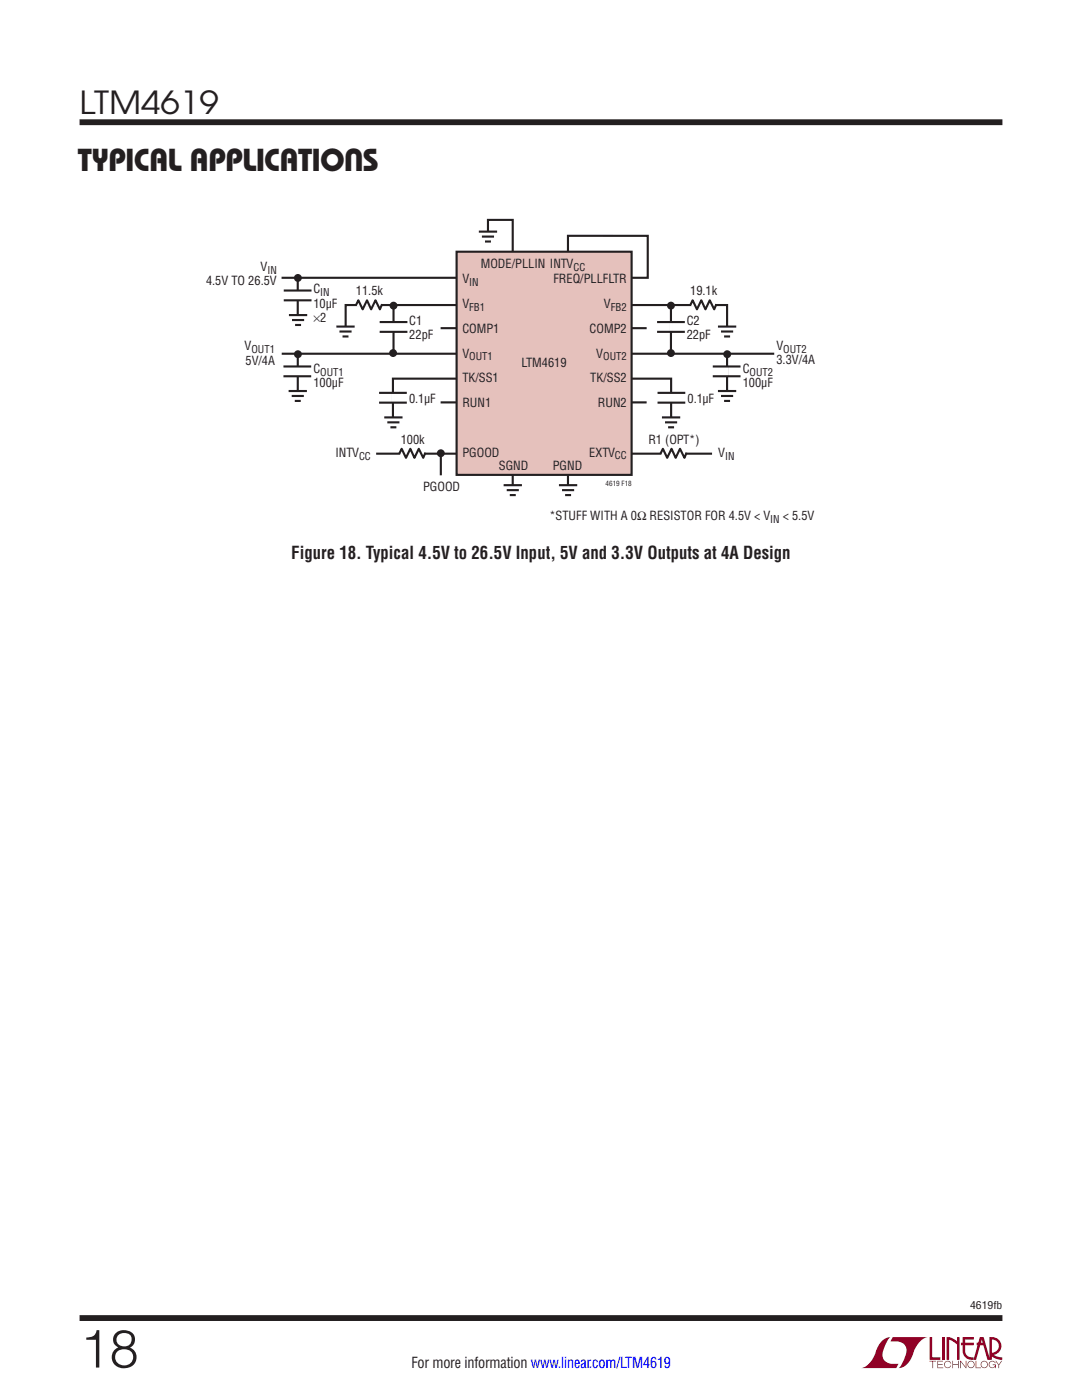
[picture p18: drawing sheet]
<svg xmlns="http://www.w3.org/2000/svg" width="216mm" height="279mm" viewBox="0 0 216 279" stroke-linecap="round" stroke-linejoin="round" font-family="sans-serif">
<defs><g id="words">
<text font-size="10.6" fill="#231f20" x="15.9" y="272.9">18</text>
<g font-size="6.3" fill="#231f20">
<text x="15.9" y="22.8">LTM4619</text>
<text x="15.6" y="34.1">Typical Applications</text>
</g>
<text font-size="3.5" fill="#231f20" x="58.1" y="111.5">Figure 18. Typical 4.5V to 26.5V Input, 5V and 3.3V Outputs at 4A Design</text>
<text font-size="3" fill="#231f20" x="82.1" y="273.1">For more information www.linear.com/LTM4619</text>
<g font-size="2.5" fill="#231f20">
<text x="95.9" y="53.5">MODE/PLLIN INTV</text>
<text x="41.1" y="56.9">4.5V TO 26.5V</text>
<text x="52" y="54.1">V</text>
<text x="62.5" y="58.6">C</text>
<text x="71" y="59">11.5k</text>
<text x="92.3" y="56.6">V</text>
<text x="110.4" y="56.6">FREQ/PLLFLTR</text>
<text x="137.7" y="59">19.1k</text>
<text x="62.5" y="61.4">10µF</text>
<text x="62.5" y="64.2">×2</text>
<text x="81.7" y="64.9">C1</text>
<text x="92.3" y="61.5">V</text>
<text x="120.5" y="61.5">V</text>
<text x="137" y="64.9">C2</text>
<text x="48.8" y="69.9">V</text>
<text x="81.7" y="67.7">22pF</text>
<text x="92.3" y="66.5">COMP1</text>
<text x="92.3" y="71.4">V</text>
<text x="117.7" y="66.5">COMP2</text>
<text x="119" y="71.4">V</text>
<text x="137" y="67.7">22pF</text>
<text x="154.9" y="69.9">V</text>
<text x="49" y="72.7">5V/4A</text>
<text x="62.5" y="74.4">C</text>
<text x="62.5" y="77.2">100µF</text>
<text x="92.3" y="76.3">TK/SS1</text>
<text x="104.1" y="73.3">LTM4619</text>
<text x="117.8" y="76.3">TK/SS2</text>
<text x="148.2" y="74.4">C</text>
<text x="148.2" y="77.2">100µF</text>
<text x="154.9" y="72.7">3.3V/4A</text>
<text x="81.6" y="80.4">0.1µF</text>
<text x="92.3" y="81.3">RUN1</text>
<text x="119.3" y="81.3">RUN2</text>
<text x="137.2" y="80.4">0.1µF</text>
<text x="80" y="88.6">100k</text>
<text x="129.4" y="88.6">R1 (OPT*)</text>
<text x="66.9" y="91.2">INTV</text>
<text x="92.3" y="91.1">PGOOD</text>
<text x="99.5" y="93.8">SGND</text>
<text x="110.3" y="93.8">PGND</text>
<text x="117.6" y="91.1">EXTV</text>
<text x="143.3" y="91.2">V</text>
<text x="84.4" y="97.9">PGOOD</text>
<text x="109.6" y="103.8">*STUFF WITH A 0Ω RESISTOR FOR 4.5V &lt; V</text>
<text x="156.2" y="103.8">&lt; 5.5V</text>
</g>
<g font-size="2.1" fill="#231f20">
<text x="53.4" y="54.6">IN</text>
<text x="63.9" y="59.1">IN</text>
<text x="93.6" y="57.1">IN</text>
<text x="114.4" y="54">CC</text>
<text x="93.6" y="62">FB1</text>
<text x="121.9" y="62">FB2</text>
<text x="50.2" y="70.5">OUT1</text>
<text x="93.6" y="71.9">OUT1</text>
<text x="120.4" y="71.9">OUT2</text>
<text x="156.3" y="70.4">OUT2</text>
<text x="63.9" y="74.9">OUT1</text>
<text x="149.6" y="74.9">OUT2</text>
<text x="71.6" y="91.7">CC</text>
<text x="122.7" y="91.7">CC</text>
<text x="144.7" y="91.7">IN</text>
<text x="153.7" y="104.3">IN</text>
<text x="193.6" y="261.2">4619fb</text>
</g>
<text font-size="1.4" fill="#231f20" x="120.9" y="96.9">4619 F18</text>
</g></defs>
<g fill="#900126">
<path d="M185.5 266.8h.5v4.1h1.6v.5h-2.1z"/>
<path d="M176.2 267.4l1-.5h.5h-.1a6.2 6.2 0 0 0-1.4 4 2.58 2.58 0 0 0 3.1 1.3l-.5 .8h-6.9a4.9 4.9 0 0 0 3-3.8l.4-.7z"/>
<path d="M178.1 266.9h7a4.9 4.9 0 0 0-3.1 3.7 3.2 3.2 0 0 1-2.7 2.4h.1a6.2 6.2 0 0 0 1.4-4.1 2.58 2.58 0 0 0-3.1-1.2z"/>
<path d="M188 266.8h.5v4.6h-.5z"/>
<path d="M188.9 266.8l1 .2 1.1 .7v-.9h.5v4.6h-.5v-3.1l-1.6-.9v4h-.5z"/>
<path d="M185.5 271.6h1.3v.1h-.6v1.3h-.1v-1.3h-.6z"/>
<path d="M187 271.6h1.2v.1h-1v.5h.9v.2h-.9v.5h1v.1h-1.2z"/>
<path d="M190 271.6h.2v.6h1v-.6h.1v1.4h-.1v-.6h-1v.6h-.2z"/>
<path d="M191.6 271.6h.1l1 1.2v-1.2h.1v1.4l-1.1-1.2v1.2h-.1z"/>
<path d="M194.7 271.6h.1v1.3h.9v.1h-1z"/>
<path d="M198.6 271.6h.2l.5 .7 .5-.7h.2l-.6 .8v.6h-.2v-.6z"/>
<path d="M192.1 266.8h2.2v.5h-1.7v.7h1.7v.5h-1.7v1.1a1.32 1.32 0 0 0 1.7 1.3v.5l1.2-4.6h.8l1.1 4.1v-4.1a1.84 1.84 0 0 1 2.4 1.4 1.84 1.84 0 0 1-1.5 2.2l.8 .4 .9 .1v.5l-1.2-.2-1-.6v-.6a1.34 1.34 0 0 0 1.5-1.2 1.34 1.34 0 0 0-1.4-1.5v4.1h-.9l-.8-2.9h-1.3v-.5h1.2l-.2-.7-1.1 4.1a2.06 2.06 0 0 1-2.7-1.3v-1.6h-.4v-.5h.4z"/>
<path d="M193.2 271.8a.72 .72 0 0 1 1.2 .1 .72 .72 0 0 1-.4 1.1 .72 .72 0 0 1-1-.7h.2a.59 .59 0 0 0 .8 .5 .59 .59 0 0 0 .2-.9 .59 .59 0 0 0-1 .2v.2h-.2z"/>
<path d="M195.9 271.8a.72 .72 0 0 1 1.1 .1 .72 .72 0 0 1-.4 1.1 .72 .72 0 0 1-.9-.7h.1a.59 .59 0 0 0 .8 .5 .59 .59 0 0 0 .2-.9 .59 .59 0 0 0-.9 .2l-.1 .2h-.1z"/>
<path d="M197.5 271.8a.72 .72 0 0 1 1.2 .2h-.2a.59 .59 0 0 0-.9-.1 .59 .59 0 0 0 .1 .9 .59 .59 0 0 0 .9-.4h-.5v-.1h.6v.7h-.1v-.3a.73 .73 0 0 1-1.1 .2 .73 .73 0 0 1 0-1.1z"/>
<path d="M188.6 271.8a.71 .71 0 0 1 1.2 .3h-.1a.59 .59 0 0 0-.9-.3 .59 .59 0 0 0-.1 1 .59 .59 0 0 0 1-.3h.1a.73 .73 0 0 1-1.1 .4 .73 .73 0 0 1-.1-1.1z"/>
</g>
<path d="M15.9 24.4h184.1M15.9 263h184.1" fill="none" stroke="#231f20" stroke-width="1.2" stroke-linecap="butt"/>
<path d="M56.2 55.4h73.1v-8.3h-16v51M97.4 47.2v-3.3h4.9v54.4M56.2 70.6h98.3M87.9 65.5h41.1M145.1 66.6v-5.7h-76.1v5.8M75.1 90.5h67M87.9 80.3h41.1M133.9 84.3v-8.7h-55.5v8.9" fill="none" stroke="#231f20" stroke-width=".42"/>
<path d="M91.1 50.2h34.9v44.6h-34.9z" fill="#e5c1bc"/>
<path d="M91.1 50.2h34.9v44.6h-34.9zM76.2 60.7l-.4 1-.9-1.8-.8 1.8-.9-1.8-.8 1.8-.9-1.8-.5 1M142.2 73.1h5.6M142.2 75.1h5.6M142.9 60.7l-.4 1-.9-1.8-.8 1.8-.9-1.8-.8 1.8-.9-1.8-.5 1M143.3 78h3.6M143.9 79h2.4M145.1 70.5v8.8M84.9 90.3l-.5 1.1-.8-1.8-.9 1.8-.8-1.8-.9 1.8-.9-1.8-.4 .9M137 90.3l-.4 1.1-.9-1.8-.9 1.8-.8-1.8-.9 1.8-.8-1.8-.5 .9M144.5 80h1.2" fill="none" stroke="#231f20" stroke-width=".42"/>
<path d="M71.2 60.8h4.8M137.9 60.8h4.8M145 73.2v1.9M79.9 90.5h4.8M132 90.5h4.8" fill="none" stroke="#fff" stroke-width=".71" stroke-linecap="butt"/>
<path d="M145.1 78.1v2.2" fill="none" stroke="#fff" stroke-width=".97" stroke-linecap="butt"/>
<circle cx="145.1" cy="70.7" r=".79" fill="#231f20"/>
<path d="M56.6 73.1h5.5M56.6 75.1h5.5M57.6 78h3.6M58.2 79h2.4M59.4 70.5v8.8M58.8 80h1.2" fill="none" stroke="#231f20" stroke-width=".42"/>
<path d="M59.3 73.2v1.9" fill="none" stroke="#fff" stroke-width=".71" stroke-linecap="butt"/>
<path d="M59.4 78.1v2.2" fill="none" stroke="#fff" stroke-width=".97" stroke-linecap="butt"/>
<circle cx="59.4" cy="70.7" r=".79" fill="#231f20"/>
<path d="M102.3 96.8v2.3M113.4 96.8v2.3" fill="none" stroke="#fff" stroke-width=".97" stroke-linecap="butt"/>
<path d="M59.4 55.6v8.7M100.5 96.8h3.6M101.1 97.8h2.4M101.7 98.8h1.2M111.5 96.8h3.7M112.1 97.8h2.5M112.8 98.8h1.2" fill="none" stroke="#231f20" stroke-width=".42"/>
<circle cx="59.4" cy="55.5" r=".79" fill="#231f20"/>
<path d="M59.4 58v1.9M78.4 78.4v2M134 78.4v2" fill="none" stroke="#fff" stroke-width=".71" stroke-linecap="butt"/>
<g fill="none" stroke="#231f20" stroke-width=".42">
<path d="M56.6 58h5.6M56.6 59.9h5.6M57.7 62.9h3.6M58.3 63.9h2.4M58.9 64.9h1.2M75.6 78.4h5.6M78.5 61v9.6M131.2 78.4h5.5M75.6 80.4h5.6M76.7 83.3h3.6M77.3 84.3h2.4M77.9 85.3h1.2"/>
<path d="M131.2 80.4h5.5M132.1 83.3h3.6M132.7 84.3h2.4M133.3 85.3h1.2"/>
</g>
<path d="M59.5 62.9v2.2M78.5 83.3v2.2M133.9 83.3v2.2" fill="none" stroke="#fff" stroke-width=".97" stroke-linecap="butt"/>
<circle cx="78.5" cy="61" r=".79" fill="#231f20"/>
<path d="M88 90.5v4.4" fill="none" stroke="#231f20" stroke-width=".42"/>
<g fill="#231f20">
<circle cx="88" cy="90.5" r=".79"/>
<circle cx="78.4" cy="70.5" r=".79"/>
</g>
<path d="M69 65.2v2.2M145.1 65.2v2.2" fill="none" stroke="#fff" stroke-width=".97" stroke-linecap="butt"/>
<path d="M67.1 65.2h3.7M67.7 66.2h2.5M68.3 67.2h1.2M75.8 64.3h5.5M75.8 66.2h5.5M133.9 61v9.6M143.3 65.2h3.6M143.9 66.2h2.4M144.5 67.2h1.2" fill="none" stroke="#231f20" stroke-width=".42"/>
<path d="M78.5 64.3v1.9" fill="none" stroke="#fff" stroke-width=".71" stroke-linecap="butt"/>
<g fill="#231f20">
<circle cx="133.9" cy="61" r=".79"/>
<circle cx="133.9" cy="70.5" r=".79"/>
</g>
<path d="M133.9 64.3v1.9" fill="none" stroke="#fff" stroke-width=".71" stroke-linecap="butt"/>
<path d="M95.5 46.2h3.7M96.2 47.2h2.4M96.8 48.2h1.2M131.1 64.3h5.6M131.1 66.2h5.6" fill="none" stroke="#231f20" stroke-width=".42"/>
<path d="M97.4 46.2v2.3" fill="none" stroke="#fff" stroke-width=".97" stroke-linecap="butt"/>
<use href="#words"/>
</svg>
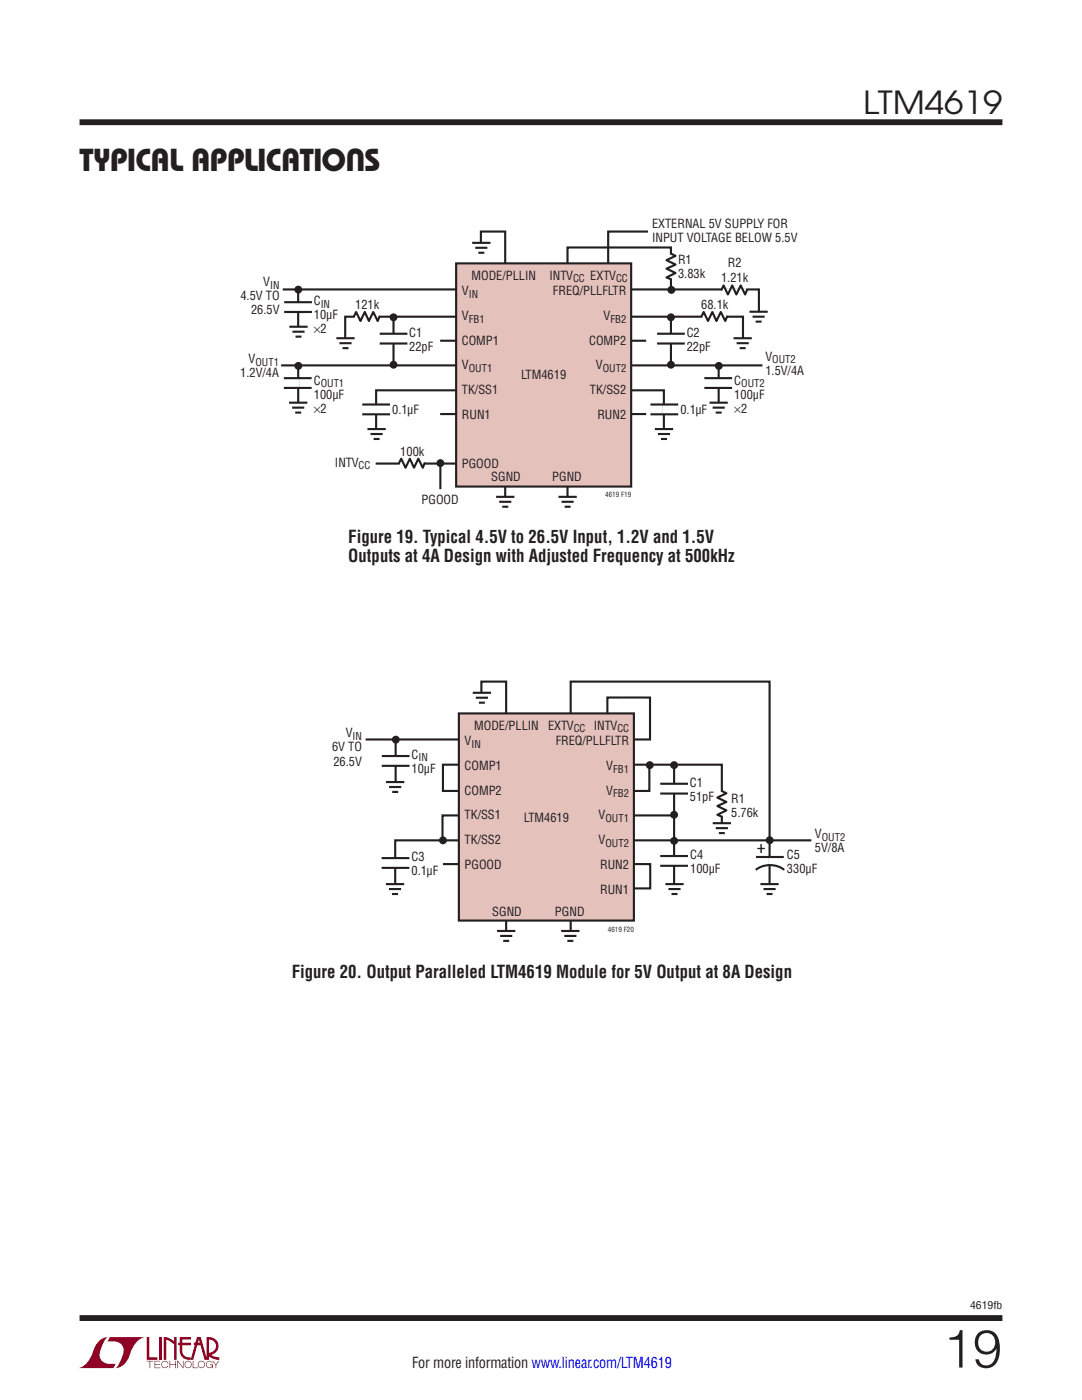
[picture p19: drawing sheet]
<svg xmlns="http://www.w3.org/2000/svg" width="216mm" height="279mm" viewBox="0 0 216 279" stroke-linecap="round" stroke-linejoin="round" font-family="sans-serif">
<defs><g id="words">
<text font-size="10.6" fill="#231f20" x="188.2" y="272.9">19</text>
<g font-size="6.3" fill="#231f20">
<text x="172.2" y="22.8">LTM4619</text>
<text x="15.9" y="34.1">TY</text>
<text x="18.6" y="34.1">P</text>
<text x="18.6" y="34.1">I</text>
<text x="18.6" y="34.1">C</text>
<text x="18.6" y="34.1">A</text>
<text x="18.6" y="34.1">L</text>
<text x="38.1" y="34.1">applications</text>
</g>
<g font-size="3.5" fill="#231f20">
<text x="69.5" y="108.4">Figure 19. Typical 4.5V to 26.5V Input, 1.2V and 1.5V</text>
<text x="69.5" y="112.2">Outputs at 4A Design with Adjusted Frequency at 500kHz</text>
<text x="58.2" y="195.2">Figure 20. Output Paralleled LTM4619 Module for 5V Output at 8A Design</text>
</g>
<text font-size="3.5" x="151" y="170.2">+</text>
<text font-size="3" fill="#231f20" x="82.2" y="273.1">For more information www.linear.com/LTM4619</text>
<g font-size="2.5" fill="#231f20">
<text x="130.1" y="45.5">EXTERNAL 5V SUPPLY FOR</text>
<text x="130.1" y="48.3">INPUT VOLTAGE BELOW 5.5V</text>
<text x="135.3" y="52.7">R1</text>
<text x="145.2" y="53.4">R2</text>
<text x="48" y="59.9">4.5V TO</text>
<text x="52.5" y="57.1">V</text>
<text x="92.2" y="58.9">V</text>
<text x="94.1" y="55.8">MODE/PLLIN</text>
<text x="109.6" y="55.8">INTV</text>
<text x="110.3" y="58.9">FREQ/PLLFLTR</text>
<text x="117.8" y="55.8">EXTV</text>
<text x="135.3" y="55.5">3.83k</text>
<text x="143.9" y="56.2">1.21k</text>
<text x="50.1" y="62.8">26.5V</text>
<text x="62.6" y="60.9">C</text>
<text x="62.6" y="63.7">10µF</text>
<text x="70.9" y="61.7">121k</text>
<text x="92.2" y="63.8">V</text>
<text x="120.4" y="63.8">V</text>
<text x="139.9" y="61.7">68.1k</text>
<text x="62.6" y="66.5">×2</text>
<text x="81.7" y="67.2">C1</text>
<text x="81.7" y="70">22pF</text>
<text x="92.2" y="68.8">COMP1</text>
<text x="117.6" y="68.8">COMP2</text>
<text x="137" y="67.2">C2</text>
<text x="137" y="70">22pF</text>
<text x="152.7" y="72">V</text>
<text x="47.9" y="75.3">1.2V/4A</text>
<text x="49.6" y="72.4">V</text>
<text x="62.6" y="76.7">C</text>
<text x="92.2" y="73.7">V</text>
<text x="104" y="75.6">LTM4619</text>
<text x="118.9" y="73.7">V</text>
<text x="146.5" y="76.7">C</text>
<text x="152.7" y="74.8">1.5V/4A</text>
<text x="62.6" y="79.6">100µF</text>
<text x="62.6" y="82.4">×2</text>
<text x="78.3" y="82.7">0.1µF</text>
<text x="92.2" y="78.7">TK/SS1</text>
<text x="92.2" y="83.6">RUN1</text>
<text x="117.7" y="78.7">TK/SS2</text>
<text x="119.2" y="83.6">RUN2</text>
<text x="135.8" y="82.7">0.1µF</text>
<text x="146.5" y="79.6">100µF</text>
<text x="146.5" y="82.4">×2</text>
<text x="66.8" y="93.2">INTV</text>
<text x="79.9" y="90.9">100k</text>
<text x="92.2" y="93.5">PGOOD</text>
<text x="84.1" y="100.6">PGOOD</text>
<text x="98" y="96.1">SGND</text>
<text x="110.2" y="96.1">PGND</text>
<text x="66.3" y="150">6V TO</text>
<text x="69" y="147.1">V</text>
<text x="92.7" y="148.7">V</text>
<text x="94.6" y="145.6">MODE/PLLIN</text>
<text x="109.4" y="145.6">EXTV</text>
<text x="110.9" y="148.7">FREQ/PLLFLTR</text>
<text x="118.5" y="145.6">INTV</text>
<text x="66.5" y="152.8">26.5V</text>
<text x="82.1" y="151.4">C</text>
<text x="82.1" y="154.2">10µF</text>
<text x="92.7" y="153.7">COMP1</text>
<text x="121" y="153.7">V</text>
<text x="92.7" y="158.6">COMP2</text>
<text x="121" y="158.6">V</text>
<text x="137.7" y="157">C1</text>
<text x="137.7" y="159.8">51pF</text>
<text x="145.9" y="160.3">R1</text>
<text x="92.7" y="163.5">TK/SS1</text>
<text x="104.5" y="164.1">LTM4619</text>
<text x="119.4" y="163.5">V</text>
<text x="145.9" y="163.1">5.76k</text>
<text x="162.6" y="167.3">V</text>
<text x="82.1" y="171.8">C3</text>
<text x="92.7" y="168.5">TK/SS2</text>
<text x="92.7" y="173.4">PGOOD</text>
<text x="119.4" y="168.5">V</text>
<text x="119.8" y="173.4">RUN2</text>
<text x="137.7" y="171.5">C4</text>
<text x="157" y="171.5">C5</text>
<text x="162.6" y="170.1">5V/8A</text>
<text x="82.1" y="174.6">0.1µF</text>
<text x="119.8" y="178.4">RUN1</text>
<text x="137.7" y="174.3">100µF</text>
<text x="157" y="174.3">330µF</text>
<text x="98.2" y="182.7">SGND</text>
<text x="110.7" y="182.7">PGND</text>
</g>
<g font-size="2.1" fill="#231f20">
<text x="53.9" y="57.6">IN</text>
<text x="93.5" y="59.4">IN</text>
<text x="114.4" y="56.3">CC</text>
<text x="122.9" y="56.4">CC</text>
<text x="64" y="61.4">IN</text>
<text x="93.5" y="64.4">FB1</text>
<text x="121.8" y="64.4">FB2</text>
<text x="51" y="73">OUT1</text>
<text x="64" y="77.3">OUT1</text>
<text x="93.5" y="74.3">OUT1</text>
<text x="120.3" y="74.3">OUT2</text>
<text x="147.9" y="77.3">OUT2</text>
<text x="154.1" y="72.5">OUT2</text>
<text x="71.6" y="93.7">CC</text>
<text x="70.3" y="147.7">IN</text>
<text x="94.1" y="149.2">IN</text>
<text x="114.5" y="146.2">CC</text>
<text x="123.2" y="146.2">CC</text>
<text x="83.5" y="151.9">IN</text>
<text x="122.3" y="154.2">FB1</text>
<text x="122.3" y="159.1">FB2</text>
<text x="120.8" y="164.1">OUT1</text>
<text x="164" y="167.8">OUT2</text>
<text x="120.8" y="169">OUT2</text>
<text x="193.6" y="261.2">4619fb</text>
</g>
<g font-size="1.4" fill="#231f20">
<text x="120.8" y="99.3">4619 F19</text>
<text x="121.3" y="185.9">4619 F20</text>
</g>
</g></defs>
<g fill="#900126">
<path d="M29.3 266.8h.5v4.1h1.6v.5h-2.1z"/>
<path d="M20 267.4l1-.5h.5h-.1a6.2 6.2 0 0 0-1.5 4 2.58 2.58 0 0 0 3.2 1.3l-.5 .8h-7a4.9 4.9 0 0 0 3.1-3.8l.4-.7z"/>
<path d="M21.9 266.9h7a4.9 4.9 0 0 0-3.1 3.7 3.2 3.2 0 0 1-2.7 2.4h.1a6.2 6.2 0 0 0 1.4-4.1 2.58 2.58 0 0 0-3.1-1.2z"/>
<path d="M31.8 266.8h.5v4.6h-.5z"/>
<path d="M32.7 266.8l1 .2 1 .7v-.9h.5v4.6h-.5v-3.1l-1.5-.9v4h-.5z"/>
<path d="M29.3 271.6h1.3v.1h-.6v1.3h-.2v-1.3h-.5z"/>
<path d="M30.8 271.6h1.2v.1h-1v.5h.9v.2h-.9v.5h1v.1h-1.2z"/>
<path d="M33.8 271.6h.2v.6h1v-.6h.1v1.4h-.1v-.6h-1v.6h-.2z"/>
<path d="M35.4 271.6h.1l1 1.2v-1.2h.1v1.4l-1.1-1.2v1.2h-.1z"/>
<path d="M38.5 271.6h.1v1.3h.9v.1h-1z"/>
<path d="M42.4 271.6h.1l.6 .7 .5-.7h.2l-.7 .8v.6h-.1v-.6z"/>
<path d="M35.9 266.8h2.2v.5h-1.7v.7h1.7v.5h-1.7v1.1a1.32 1.32 0 0 0 1.6 1.3v.5l1.3-4.6h.8l1.1 4.1v-4.1a1.84 1.84 0 0 1 2.3 1.4 1.84 1.84 0 0 1-1.4 2.2l.7 .4 1 .1v.5l-1.2-.2-1.1-.6v-.6a1.34 1.34 0 0 0 1.6-1.2 1.34 1.34 0 0 0-1.4-1.5v4.1h-.9l-.8-2.9h-1.3v-.5h1.2l-.2-.7-1.1 4.1a2.06 2.06 0 0 1-2.7-1.3v-1.6h-.4v-.5h.4z"/>
<path d="M37 271.8a.72 .72 0 0 1 1.2 .1 .72 .72 0 0 1-.4 1.1 .72 .72 0 0 1-1-.7h.2a.59 .59 0 0 0 .8 .5 .59 .59 0 0 0 .2-.9 .59 .59 0 0 0-1 .2v.2h-.2z"/>
<path d="M39.7 271.8a.72 .72 0 0 1 1.1 .1 .72 .72 0 0 1-.4 1.1 .72 .72 0 0 1-.9-.7h.1a.59 .59 0 0 0 .8 .5 .59 .59 0 0 0 .2-.9 .59 .59 0 0 0-1 .2v.2h-.1z"/>
<path d="M41.3 271.8a.72 .72 0 0 1 1.2 .2h-.2a.59 .59 0 0 0-.9-.1 .59 .59 0 0 0 .1 .9 .59 .59 0 0 0 .9-.4h-.5v-.1h.6v.7h-.1v-.3a.73 .73 0 0 1-1.1 .2 .73 .73 0 0 1 0-1.1z"/>
<path d="M32.4 271.8a.71 .71 0 0 1 1.2 .3h-.1a.59 .59 0 0 0-.9-.3 .59 .59 0 0 0-.1 1 .59 .59 0 0 0 .9-.3h.2a.73 .73 0 0 1-1.1 .4 .73 .73 0 0 1-.1-1.1z"/>
</g>
<path d="M15.9 24.4h184.1M15.9 263h184.1" fill="none" stroke="#231f20" stroke-width="1.2" stroke-linecap="butt"/>
<path d="M56.4 57.8h95v4.9M96 49.5v-3.3h4.8v54.4M129.3 46.2h-7.9v10.2M133.9 57.8v-8.4h-20.7v51.1M56.1 72.9h96M87.8 68h41.1M148.3 68.9v-5.7h-79.4v5.9M75 92.5h19.2M87.8 82.6h41.1M132.5 86.7v-8.8h-57.4v9" fill="none" stroke="#231f20" stroke-width=".42"/>
<path d="M91 52.6h34.9v44.5h-34.9z" fill="#e5c1bc" stroke="#231f20" stroke-width=".42"/>
<path d="M144.1 57.9h4.8M70.8 63.2h4.8M140.1 63.2h4.8M143.3 75.5v1.9M79.8 92.4h4.8" fill="none" stroke="#fff" stroke-width=".71" stroke-linecap="butt"/>
<path d="M149.1 57.7l-.4 1.1-.9-1.8-.9 1.8-.8-1.8-.9 1.8-.8-1.8-.5 .9M75.8 63l-.4 1.1-.9-1.8-.9 1.8-.8-1.8-.9 1.8-.8-1.8-.5 .9M140.5 75.5h5.6M140.5 77.4h5.6M143.4 72.8v8.8M145.1 63l-.4 1.1-.9-1.8-.8 1.8-.9-1.8-.8 1.8-.9-1.8-.5 .9M84.8 92.3l-.4 1-.9-1.8-.9 1.8-.8-1.8-.9 1.8-.8-1.8-.5 1M141.6 80.4h3.6M142.2 81.4h2.4M142.8 82.3h1.2" fill="none" stroke="#231f20" stroke-width=".42"/>
<path d="M143.4 80.4v2.2" fill="none" stroke="#fff" stroke-width=".97" stroke-linecap="butt"/>
<circle cx="143.4" cy="73" r=".79" fill="#231f20"/>
<path d="M56.6 75.5h5.6M56.6 77.4h5.6M59.5 72.8v8.8M57.7 80.4h3.6M58.3 81.4h2.4M58.9 82.3h1.2" fill="none" stroke="#231f20" stroke-width=".42"/>
<path d="M59.4 75.5v1.9" fill="none" stroke="#fff" stroke-width=".71" stroke-linecap="butt"/>
<path d="M59.5 80.4v2.2" fill="none" stroke="#fff" stroke-width=".97" stroke-linecap="butt"/>
<circle cx="59.5" cy="73" r=".79" fill="#231f20"/>
<path d="M100.8 99.2v2.2M113.3 99.2v2.2" fill="none" stroke="#fff" stroke-width=".97" stroke-linecap="butt"/>
<path d="M59.5 58v8.7M99 99.2h3.6M111.4 99.2h3.7M99.6 100.1h2.4M100.2 101.1h1.2M112.1 100.1h2.4M112.7 101.1h1.2" fill="none" stroke="#231f20" stroke-width=".42"/>
<circle cx="59.5" cy="57.8" r=".79" fill="#231f20"/>
<path d="M59.5 60.3v2M75.1 80.8v1.9M132.6 80.8v1.9" fill="none" stroke="#fff" stroke-width=".71" stroke-linecap="butt"/>
<g fill="none" stroke="#231f20" stroke-width=".42">
<path d="M56.7 60.3h5.5M56.7 62.3h5.5M57.7 65.2h3.7M58.4 66.2h2.4M59 67.2h1.2M78.5 63.3v9.6M72.3 80.7h5.5M72.3 82.7h5.5M73.3 85.6h3.7M73.9 86.6h2.5M74.5 87.6h1.2M129.8 80.7h5.5"/>
<path d="M129.8 82.7h5.5M130.7 85.6h3.6M131.3 86.6h2.4M131.9 87.6h1.2"/>
</g>
<path d="M59.6 65.2v2.2M75.1 85.6v2.3M132.5 85.6v2.3" fill="none" stroke="#fff" stroke-width=".97" stroke-linecap="butt"/>
<circle cx="78.5" cy="63.3" r=".79" fill="#231f20"/>
<path d="M87.9 92.4v5.2" fill="none" stroke="#231f20" stroke-width=".42"/>
<g fill="#231f20">
<circle cx="87.9" cy="92.4" r=".79"/>
<circle cx="78.5" cy="72.8" r=".79"/>
</g>
<path d="M68.9 67.5v2.2M148.2 67.5v2.2" fill="none" stroke="#fff" stroke-width=".97" stroke-linecap="butt"/>
<path d="M67.1 67.5h3.7M67.7 68.5h2.5M68.3 69.5h1.2M75.8 66.6h5.5M75.8 68.6h5.5M133.9 63.3v9.6M146.4 67.5h3.6M147 68.5h2.4M147.6 69.5h1.2" fill="none" stroke="#231f20" stroke-width=".42"/>
<path d="M78.5 66.6v1.9" fill="none" stroke="#fff" stroke-width=".71" stroke-linecap="butt"/>
<g fill="#231f20">
<circle cx="133.9" cy="63.3" r=".79"/>
<circle cx="134" cy="57.9" r=".79"/>
<circle cx="133.9" cy="72.8" r=".79"/>
</g>
<path d="M133.9 50.8v4.8M133.9 66.6v1.9" fill="none" stroke="#fff" stroke-width=".71" stroke-linecap="butt"/>
<g fill="none" stroke="#231f20" stroke-width=".42">
<path d="M94.2 48.5h3.7M94.8 49.5h2.5M95.4 50.4h1.2M133.8 50.6l1 .5-1.8 .8 1.8 .9-1.8 .8 1.8 .9-1.8 .9 1 .4M131.1 66.6h5.5M131.1 68.6h5.5M149.5 62.2h3.7M150.2 63.2h2.4M150.8 64.2h1.2M96.1 140v-4h4.9v51.1M73 147.6h56.7v-8.4h-8.5v10.7M129.6 152.6v5.3h-41.2v-5.3h55.6v13"/>
<path d="M88.4 172.5h41.3v4.8h-9.1M134.2 162.7h-45.9v5M153.6 177v-41h-39.7v50.5M161.9 167.7h-83v9.8"/>
</g>
<path d="M96.1 48.5v2.2M151.4 62.2v2.2" fill="none" stroke="#fff" stroke-width=".97" stroke-linecap="butt"/>
<path d="M91.6 142.4h34.9v41.3h-34.9z" fill="#e5c1bc" stroke="#231f20" stroke-width=".42"/>
<path d="M144 158v4.8" fill="none" stroke="#fff" stroke-width=".71" stroke-linecap="butt"/>
<path d="M144 157.8l.9 .5-1.8 .9 1.8 .8-1.8 .9 1.8 .8-1.8 .9 1.1 .4M77 176.4h3.6M77.6 177.4h2.4M78.2 178.4h1.2M151.7 176.4h3.7M152.3 177.4h2.5M153 178.4h1.2" fill="none" stroke="#231f20" stroke-width=".42"/>
<path d="M78.8 176.5v2.2M153.6 176.5v2.2" fill="none" stroke="#fff" stroke-width=".97" stroke-linecap="butt"/>
<circle cx="153.6" cy="167.7" r=".79" fill="#231f20"/>
<path d="M101 185.8v2.2M113.8 185.8v2.2" fill="none" stroke="#fff" stroke-width=".97" stroke-linecap="butt"/>
<path d="M78.9 147.8v8.7M99.2 185.8h3.6M99.8 186.8h2.4M100.4 187.8h1.2M112 185.8h3.6M112.6 186.8h2.4M113.2 187.8h1.2" fill="none" stroke="#231f20" stroke-width=".42"/>
<circle cx="79" cy="147.6" r=".79" fill="#231f20"/>
<path d="M79 150.9v1.9M78.9 171.3v1.9" fill="none" stroke="#fff" stroke-width=".71" stroke-linecap="butt"/>
<path d="M76.2 150.9h5.5M76.2 152.8h5.5M77 156.1h3.7M77.6 157.1h2.5M78.3 158.1h1.1M134.5 152.7v25M76.1 171.3h5.6M76.1 173.2h5.6M142.2 164.3h3.7M142.8 165.3h2.4M143.4 166.3h1.2" fill="none" stroke="#231f20" stroke-width=".42"/>
<path d="M78.9 156.1v2.2M144 164.3v2.2" fill="none" stroke="#fff" stroke-width=".97" stroke-linecap="butt"/>
<g fill="#231f20">
<circle cx="134.5" cy="152.7" r=".79"/>
<circle cx="129.7" cy="152.7" r=".79"/>
<circle cx="134.5" cy="162.6" r=".79"/>
<circle cx="134.5" cy="167.8" r=".79"/>
</g>
<path d="M134.5 156.4v2M134.5 170.9v1.9M153.6 171.1v1.6" fill="none" stroke="#fff" stroke-width=".71" stroke-linecap="butt"/>
<path d="M94.3 138.3h3.7M94.9 139.2h2.5M95.6 140.2h1.2M131.7 156.4h5.6M131.7 158.4h5.6M131.7 170.8h5.6M131.7 172.8h5.6M132.8 176.4h3.6M133.4 177.4h2.4M134 178.4h1.2M150.8 173.6a4.7 4.7 0 0 1 5.7 0M150.9 171h5.5" fill="none" stroke="#231f20" stroke-width=".42"/>
<path d="M96.2 138.3v2.2M134.6 176.5v2.2" fill="none" stroke="#fff" stroke-width=".97" stroke-linecap="butt"/>
<circle cx="88.4" cy="167.7" r=".79" fill="#231f20"/>
<use href="#words"/>
</svg>
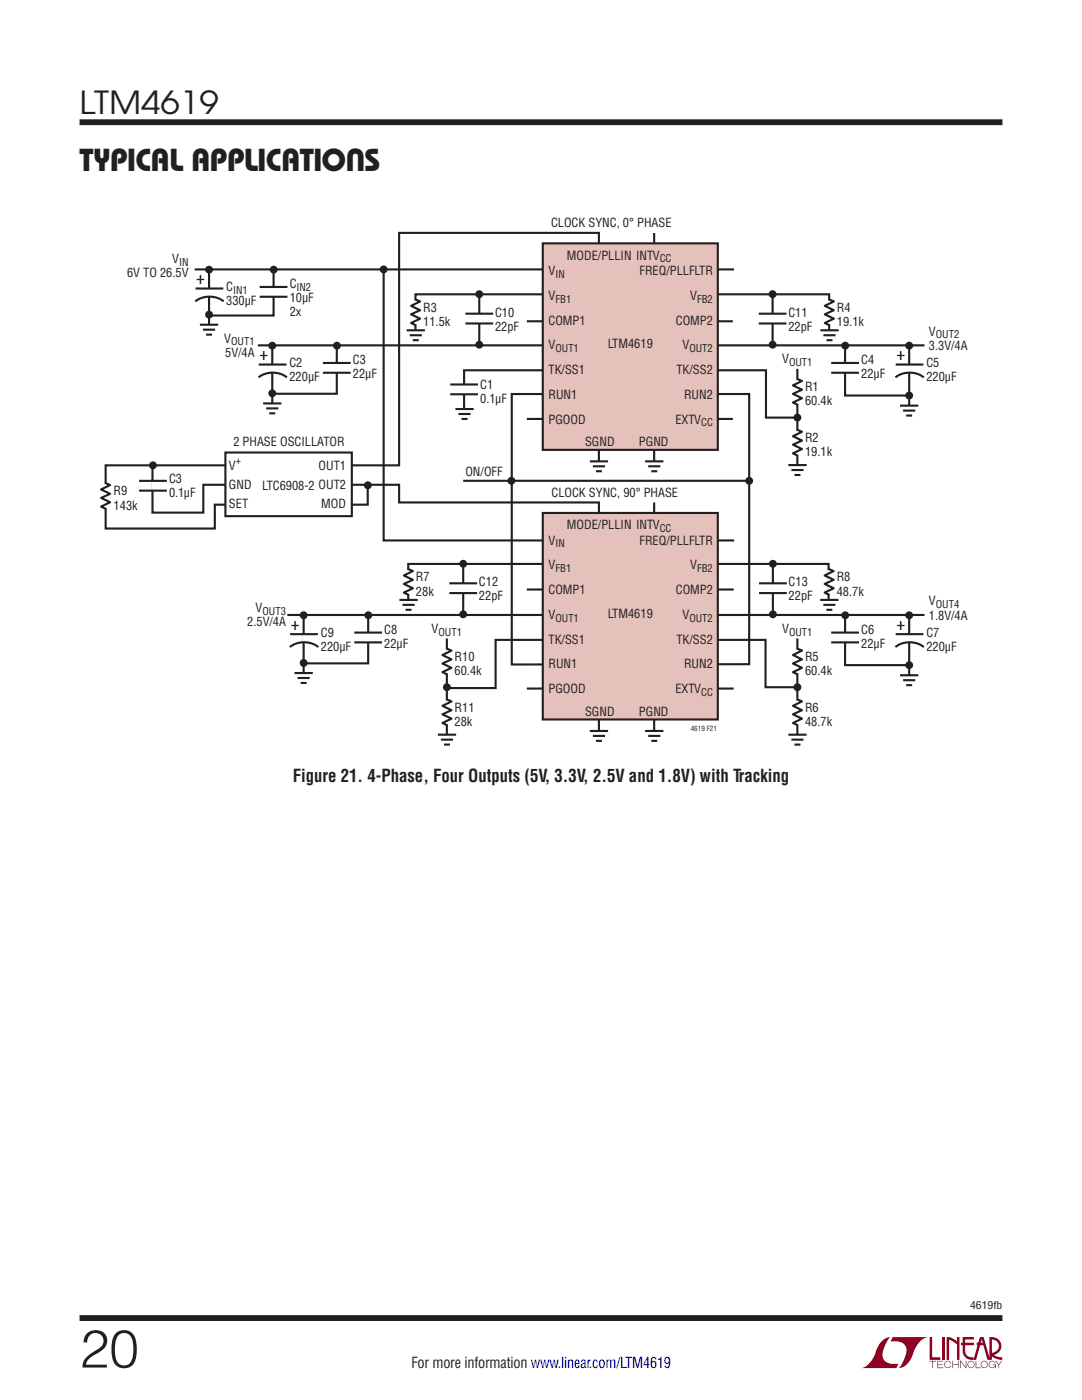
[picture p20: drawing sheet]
<svg xmlns="http://www.w3.org/2000/svg" width="216mm" height="279mm" viewBox="0 0 216 279" stroke-linecap="round" stroke-linejoin="round" font-family="sans-serif">
<defs><g id="words">
<text font-size="10.6" fill="#231f20" x="15.9" y="272.9">20</text>
<g font-size="6.3" fill="#231f20">
<text x="15.9" y="22.8">LTM4619</text>
<text x="15.9" y="34.1">TY</text>
<text x="18.6" y="34.1">P</text>
<text x="18.6" y="34.1">I</text>
<text x="18.6" y="34.1">C</text>
<text x="18.6" y="34.1">A</text>
<text x="18.6" y="34.1">L</text>
<text x="38.1" y="34.1">applications</text>
</g>
<g font-size="3.5">
<text x="39.2" y="56.7">+</text>
<text x="51.8" y="71.9">+</text>
<text x="178.9" y="71.9">+</text>
<text x="58" y="125.7">+</text>
<text x="178.9" y="125.7">+</text>
</g>
<text font-size="3.5" fill="#231f20" x="58.4" y="156">Figure 21. 4-Phase, Four Outputs (5V, 3.3V, 2.5V and 1.8V) with Tracking</text>
<text font-size="3" fill="#231f20" x="82.1" y="273.1">For more information www.linear.com/LTM4619</text>
<g font-size="2.5" fill="#231f20">
<text x="109.9" y="45.2">CLOCK SYNC, 0° PHASE</text>
<text x="34.4" y="52.5">V</text>
<text x="113.1" y="51.8">MODE/PLLIN INTV</text>
<text x="25.3" y="55.3">6V TO 26.5V</text>
<text x="45.1" y="58.1">C</text>
<text x="57.8" y="57.5">C</text>
<text x="109.4" y="54.9">V</text>
<text x="109.4" y="59.8">V</text>
<text x="127.6" y="54.9">FREQ/PLLFLTR</text>
<text x="137.7" y="59.8">V</text>
<text x="45.1" y="60.9">330µF</text>
<text x="57.8" y="60.3">10µF</text>
<text x="57.8" y="63.1">2x</text>
<text x="84.4" y="62.2">R3</text>
<text x="84.4" y="65">11.5k</text>
<text x="98.8" y="63.2">C10</text>
<text x="109.4" y="64.8">COMP1</text>
<text x="134.8" y="64.8">COMP2</text>
<text x="157.3" y="63.2">C11</text>
<text x="167" y="62.2">R4</text>
<text x="167" y="65">19.1k</text>
<text x="44.7" y="68.4">V</text>
<text x="44.9" y="71.2">5V/4A</text>
<text x="98.8" y="66">22pF</text>
<text x="109.4" y="69.7">V</text>
<text x="121.3" y="69.5">LTM4619</text>
<text x="136.2" y="69.7">V</text>
<text x="157.3" y="66">22pF</text>
<text x="185.4" y="67">V</text>
<text x="185.4" y="69.8">3.3V/4A</text>
<text x="57.8" y="73.2">C2</text>
<text x="57.8" y="76.1">220µF</text>
<text x="70.4" y="72.7">C3</text>
<text x="70.4" y="75.5">22µF</text>
<text x="95.8" y="77.6">C1</text>
<text x="109.4" y="74.7">TK/SS1</text>
<text x="135" y="74.7">TK/SS2</text>
<text x="156.1" y="72.5">V</text>
<text x="171.8" y="72.7">C4</text>
<text x="171.8" y="75.5">22µF</text>
<text x="184.8" y="73.2">C5</text>
<text x="184.8" y="76.1">220µF</text>
<text x="95.8" y="80.4">0.1µF</text>
<text x="109.4" y="79.6">RUN1</text>
<text x="136.5" y="79.6">RUN2</text>
<text x="160.6" y="78.1">R1</text>
<text x="160.6" y="80.9">60.4k</text>
<text x="46.6" y="89">2 PHASE OSCILLATOR</text>
<text x="109.4" y="84.5">PGOOD</text>
<text x="116.7" y="89">SGND</text>
<text x="127.5" y="89">PGND</text>
<text x="134.8" y="84.5">EXTV</text>
<text x="160.6" y="88.2">R2</text>
<text x="45.7" y="93.7">V</text>
<text x="63.6" y="93.7">OUT1</text>
<text x="92.9" y="94.9">ON/OFF</text>
<text x="160.6" y="91.1">19.1k</text>
<text x="22.7" y="98.9">R9</text>
<text x="22.7" y="101.7">143k</text>
<text x="33.7" y="96.4">C3</text>
<text x="33.7" y="99.2">0.1µF</text>
<text x="45.7" y="97.6">GND</text>
<text x="45.7" y="101.5">SET</text>
<text x="52.3" y="97.8">LTC6908-2 OUT2</text>
<text x="64.1" y="101.5">MOD</text>
<text x="110" y="99.2">CLOCK SYNC, 90° PHASE</text>
<text x="113.1" y="105.6">MODE/PLLIN INTV</text>
<text x="109.4" y="108.7">V</text>
<text x="109.4" y="113.7">V</text>
<text x="127.6" y="108.7">FREQ/PLLFLTR</text>
<text x="137.7" y="113.7">V</text>
<text x="83" y="116">R7</text>
<text x="83" y="118.9">28k</text>
<text x="95.6" y="117">C12</text>
<text x="95.6" y="119.8">22pF</text>
<text x="109.4" y="118.6">COMP1</text>
<text x="134.8" y="118.6">COMP2</text>
<text x="157.4" y="117">C13</text>
<text x="157.4" y="119.8">22pF</text>
<text x="167" y="116">R8</text>
<text x="167" y="118.9">48.7k</text>
<text x="49.3" y="125">2.5V/4A</text>
<text x="51" y="122.2">V</text>
<text x="109.4" y="123.5">V</text>
<text x="121.3" y="123.3">LTM4619</text>
<text x="136.2" y="123.5">V</text>
<text x="185.4" y="120.8">V</text>
<text x="185.4" y="123.7">1.8V/4A</text>
<text x="64" y="127">C9</text>
<text x="64" y="129.9">220µF</text>
<text x="76.7" y="126.5">C8</text>
<text x="76.7" y="129.3">22µF</text>
<text x="86.1" y="126.3">V</text>
<text x="90.7" y="131.9">R10</text>
<text x="109.4" y="128.5">TK/SS1</text>
<text x="135" y="128.5">TK/SS2</text>
<text x="156.1" y="126.3">V</text>
<text x="160.6" y="131.9">R5</text>
<text x="171.8" y="126.5">C6</text>
<text x="171.8" y="129.3">22µF</text>
<text x="184.8" y="127">C7</text>
<text x="184.8" y="129.9">220µF</text>
<text x="90.7" y="134.7">60.4k</text>
<text x="109.4" y="133.4">RUN1</text>
<text x="136.5" y="133.4">RUN2</text>
<text x="160.6" y="134.7">60.4k</text>
<text x="90.7" y="142">R11</text>
<text x="109.4" y="138.3">PGOOD</text>
<text x="116.7" y="142.8">SGND</text>
<text x="127.5" y="142.8">PGND</text>
<text x="134.8" y="138.3">EXTV</text>
<text x="160.6" y="142">R6</text>
<text x="90.7" y="144.9">28k</text>
<text x="160.6" y="144.9">48.7k</text>
</g>
<g font-size="2.1" fill="#231f20">
<text x="35.7" y="53">IN</text>
<text x="131.6" y="52.3">CC</text>
<text x="46.5" y="58.6">IN1</text>
<text x="59.2" y="58">IN2</text>
<text x="110.8" y="55.4">IN</text>
<text x="110.8" y="60.4">FB1</text>
<text x="139.1" y="60.4">FB2</text>
<text x="46.1" y="68.9">OUT1</text>
<text x="110.8" y="70.3">OUT1</text>
<text x="137.6" y="70.3">OUT2</text>
<text x="186.7" y="67.6">OUT2</text>
<text x="157.4" y="73">OUT1</text>
<text x="139.9" y="85.1">CC</text>
<text x="47.1" y="92.7">+</text>
<text x="131.6" y="106.2">CC</text>
<text x="110.8" y="109.2">IN</text>
<text x="110.8" y="114.2">FB1</text>
<text x="139.1" y="114.2">FB2</text>
<text x="52.4" y="122.7">OUT3</text>
<text x="110.8" y="124.1">OUT1</text>
<text x="137.6" y="124.1">OUT2</text>
<text x="186.7" y="121.4">OUT4</text>
<text x="87.5" y="126.8">OUT1</text>
<text x="157.4" y="126.8">OUT1</text>
<text x="139.9" y="138.9">CC</text>
<text x="193.6" y="261.2">4619fb</text>
</g>
<text font-size="1.4" fill="#231f20" x="137.8" y="145.9">4619 F21</text>
</g></defs>
<g fill="#900126">
<path d="M185.5 266.8h.5v4.1h1.6v.5h-2.1z"/>
<path d="M176.2 267.4l1-.5h.5h-.1a6.2 6.2 0 0 0-1.4 4 2.58 2.58 0 0 0 3.1 1.3l-.5 .8h-6.9a4.9 4.9 0 0 0 3-3.8l.4-.7z"/>
<path d="M178.1 266.9h7a4.9 4.9 0 0 0-3.1 3.7 3.2 3.2 0 0 1-2.7 2.4h.1a6.2 6.2 0 0 0 1.4-4.1 2.58 2.58 0 0 0-3.1-1.2z"/>
<path d="M188 266.8h.5v4.6h-.5z"/>
<path d="M188.9 266.8l1 .2 1.1 .7v-.9h.5v4.6h-.5v-3.1l-1.6-.9v4h-.5z"/>
<path d="M185.5 271.6h1.3v.1h-.6v1.3h-.1v-1.3h-.6z"/>
<path d="M187 271.6h1.2v.1h-1v.5h.9v.2h-.9v.5h1v.1h-1.2z"/>
<path d="M190 271.6h.2v.6h1v-.6h.1v1.4h-.1v-.6h-1v.6h-.2z"/>
<path d="M191.6 271.6h.1l1 1.2v-1.2h.1v1.4l-1.1-1.2v1.2h-.1z"/>
<path d="M194.7 271.6h.1v1.3h.9v.1h-1z"/>
<path d="M198.6 271.6h.2l.5 .7 .5-.7h.2l-.6 .8v.6h-.2v-.6z"/>
<path d="M192.1 266.8h2.2v.5h-1.7v.7h1.7v.5h-1.7v1.1a1.32 1.32 0 0 0 1.7 1.3v.5l1.2-4.6h.8l1.1 4.1v-4.1a1.84 1.84 0 0 1 2.4 1.4 1.84 1.84 0 0 1-1.5 2.2l.8 .4 .9 .1v.5l-1.2-.2-1-.6v-.6a1.34 1.34 0 0 0 1.5-1.2 1.34 1.34 0 0 0-1.4-1.5v4.1h-.9l-.8-2.9h-1.3v-.5h1.2l-.2-.7-1.1 4.1a2.06 2.06 0 0 1-2.7-1.3v-1.6h-.4v-.5h.4z"/>
<path d="M193.2 271.8a.72 .72 0 0 1 1.2 .1 .72 .72 0 0 1-.4 1.1 .72 .72 0 0 1-1-.7h.2a.59 .59 0 0 0 .8 .5 .59 .59 0 0 0 .2-.9 .59 .59 0 0 0-1 .2v.2h-.2z"/>
<path d="M195.9 271.8a.72 .72 0 0 1 1.1 .1 .72 .72 0 0 1-.4 1.1 .72 .72 0 0 1-.9-.7h.1a.59 .59 0 0 0 .8 .5 .59 .59 0 0 0 .2-.9 .59 .59 0 0 0-.9 .2l-.1 .2h-.1z"/>
<path d="M197.5 271.8a.72 .72 0 0 1 1.2 .2h-.2a.59 .59 0 0 0-.9-.1 .59 .59 0 0 0 .1 .9 .59 .59 0 0 0 .9-.4h-.5v-.1h.6v.7h-.1v-.3a.73 .73 0 0 1-1.1 .2 .73 .73 0 0 1 0-1.1z"/>
<path d="M188.6 271.8a.71 .71 0 0 1 1.2 .3h-.1a.59 .59 0 0 0-.9-.3 .59 .59 0 0 0-.1 1 .59 .59 0 0 0 1-.3h.1a.73 .73 0 0 1-1.1 .4 .73 .73 0 0 1-.1-1.1z"/>
</g>
<path d="M15.9 24.4h184.1M15.9 263h184.1" fill="none" stroke="#231f20" stroke-width="1.2" stroke-linecap="butt"/>
<path d="M38.8 53.8h107.6M76.6 53.8v54.1h69.9M130.5 46.5v47M51.4 68.9h133.1M102.1 78.6h47.4v54h-47.4zM105.1 64.1h41.1M165.5 67.3v-8.6h-82.6v8.8M92.4 96h57.1M92.6 82.9v-9h60.2v9.4h6.3M105.1 83.6h41.1M119.5 93.4v-46.9h-39.9v46.4h-58.5v12.6h21.8v-4.8h30.5v-3.8" fill="none" stroke="#231f20" stroke-width=".42"/>
<path d="M108.3 48.6h34.9v41.2h-34.9z" fill="#e5c1bc" stroke="#231f20" stroke-width=".42"/>
<path d="M82.9 59.9v4.9M168.6 72.5v1.9" fill="none" stroke="#fff" stroke-width=".71" stroke-linecap="butt"/>
<path d="M82.8 59.7l1 .5-1.8 .8 1.8 .9-1.8 .8 1.8 .9-1.8 .9 1 .4M165.9 72.4h5.5M165.9 74.4h5.5M168.6 69v9.9h12.8" fill="none" stroke="#231f20" stroke-width=".42"/>
<circle cx="168.7" cy="69" r=".79" fill="#231f20"/>
<path d="M92.7 81.6v2.3M119.5 92.1v2.2M130.6 92.1v2.2" fill="none" stroke="#fff" stroke-width=".97" stroke-linecap="butt"/>
<path d="M95.6 58.8v10.1M89.8 76.7h5.6M89.8 78.7h5.6M90.9 81.6h3.6M91.5 82.6h2.4M92.1 83.6h1.2M117.7 92.1h3.6M118.3 93.1h2.4M118.9 94h1.2M128.7 92.1h3.7M129.3 93.1h2.5M130 94h1.1" fill="none" stroke="#231f20" stroke-width=".42"/>
<path d="M92.6 76.8v1.9" fill="none" stroke="#fff" stroke-width=".71" stroke-linecap="butt"/>
<g fill="#231f20">
<circle cx="95.6" cy="58.7" r=".79"/>
<circle cx="95.6" cy="68.8" r=".79"/>
</g>
<path d="M83 65.9v2.2M165.5 65.9v2.2" fill="none" stroke="#fff" stroke-width=".97" stroke-linecap="butt"/>
<path d="M154.2 58.8v10.1M165.4 59.7l1 .5-1.8 .8 1.8 .9-1.8 .8 1.8 .9-1.8 .9 1 .4M81.1 65.9h3.7M81.8 66.9h2.4M82.4 67.9h1.2M92.9 62.6h5.5M92.9 64.6h5.5M163.7 65.9h3.6M164.3 66.9h2.4M164.9 67.9h1.2" fill="none" stroke="#231f20" stroke-width=".42"/>
<path d="M165.5 59.9v4.9M95.6 62.6v2" fill="none" stroke="#fff" stroke-width=".71" stroke-linecap="butt"/>
<g fill="#231f20">
<circle cx="154.2" cy="58.7" r=".79"/>
<circle cx="154.2" cy="68.8" r=".79"/>
</g>
<path d="M154.2 62.6v2" fill="none" stroke="#fff" stroke-width=".71" stroke-linecap="butt"/>
<path d="M151.4 62.6h5.5M151.4 64.6h5.5M159.1 73.6v20.6" fill="none" stroke="#231f20" stroke-width=".42"/>
<circle cx="159.1" cy="83.3" r=".79" fill="#231f20"/>
<path d="M159.1 75.8v4.8M159.1 86v4.8" fill="none" stroke="#fff" stroke-width=".71" stroke-linecap="butt"/>
<path d="M159 75.6l1 .4-1.8 .9 1.8 .9-1.8 .8 1.8 .9-1.8 .8 1 .5M181.4 69.1v12.7M157.3 92.8h3.7M157.9 93.8h2.4M158.5 94.8h1.2M159 85.7l1 .5-1.8 .9 1.8 .8-1.8 .8 1.8 .9-1.8 .9 1 .5" fill="none" stroke="#231f20" stroke-width=".42"/>
<path d="M159.1 92.8v2.2" fill="none" stroke="#fff" stroke-width=".97" stroke-linecap="butt"/>
<circle cx="181.4" cy="69" r=".79" fill="#231f20"/>
<path d="M181.5 72.8v1.6" fill="none" stroke="#fff" stroke-width=".71" stroke-linecap="butt"/>
<path d="M178.7 75.3a4.7 4.7 0 0 1 5.6 0M178.7 72.8h5.6" fill="none" stroke="#231f20" stroke-width=".42"/>
<circle cx="181.4" cy="78.9" r=".79" fill="#231f20"/>
<path d="M181.4 81v2.2" fill="none" stroke="#fff" stroke-width=".97" stroke-linecap="butt"/>
<path d="M64.4 72.4h5.6M64.4 74.4h5.6M67.2 69v9.6h-12.9M179.6 81h3.6M180.2 81.9h2.4M180.8 82.9h1.2" fill="none" stroke="#231f20" stroke-width=".42"/>
<path d="M67.2 72.5v1.9" fill="none" stroke="#fff" stroke-width=".71" stroke-linecap="butt"/>
<circle cx="67.2" cy="69" r=".79" fill="#231f20"/>
<path d="M54.3 69.1v12.4" fill="none" stroke="#231f20" stroke-width=".42"/>
<circle cx="54.3" cy="69" r=".79" fill="#231f20"/>
<path d="M54.4 72.8v1.6" fill="none" stroke="#fff" stroke-width=".71" stroke-linecap="butt"/>
<path d="M51.6 75.3a4.7 4.7 0 0 1 5.6 0M51.6 72.8h5.6" fill="none" stroke="#231f20" stroke-width=".42"/>
<circle cx="54.3" cy="78.5" r=".79" fill="#231f20"/>
<path d="M54.3 80.5v2.2" fill="none" stroke="#fff" stroke-width=".97" stroke-linecap="butt"/>
<path d="M30.4 92.9v9.4h10.2v-5.6h39v3.6h39.9v47M52.5 80.5h3.6M53.1 81.5h2.4M53.7 82.5h1.2M105.1 117.7h41.3M130.5 100.3v47M57.3 122.7h127.2M105.1 137.4h41.3M159.1 137.2h-6.3v-9.5h-53.9v9.6h-9.8M165.3 121.2v-8.7h-83.8v8.8" fill="none" stroke="#231f20" stroke-width=".42"/>
<path d="M108.3 102.4h34.9v41.2h-34.9z" fill="#e5c1bc" stroke="#231f20" stroke-width=".42"/>
<path d="M81.5 113.7v4.9M168.6 126.3v1.9" fill="none" stroke="#fff" stroke-width=".71" stroke-linecap="butt"/>
<path d="M81.4 113.5l1 .5-1.8 .8 1.8 .9-1.8 .8 1.8 .9-1.8 .9 1 .4M165.9 126.2h5.5M165.9 128.2h5.5M168.6 122.8v9.9h12.8" fill="none" stroke="#231f20" stroke-width=".42"/>
<circle cx="168.7" cy="122.8" r=".79" fill="#231f20"/>
<path d="M119.5 145.9v2.2M130.6 145.9v2.2" fill="none" stroke="#fff" stroke-width=".97" stroke-linecap="butt"/>
<path d="M92.4 112.6v10.1M117.7 145.9h3.6M118.3 146.9h2.4M118.9 147.9h1.2M128.7 145.9h3.7M129.3 146.9h2.5M130 147.9h1.1" fill="none" stroke="#231f20" stroke-width=".42"/>
<g fill="#231f20">
<circle cx="92.4" cy="112.5" r=".79"/>
<circle cx="92.4" cy="122.6" r=".79"/>
</g>
<path d="M81.5 119.7v2.3M165.5 119.7v2.3" fill="none" stroke="#fff" stroke-width=".97" stroke-linecap="butt"/>
<path d="M79.7 119.7h3.6M89.7 116.4h5.5M89.7 118.4h5.5M154.2 112.6v10.1M163.7 119.7h3.6M165.3 113.5l1 .5-1.8 .8 1.8 .9-1.8 .8 1.8 .9-1.8 .9 1 .4M80.3 120.7h2.4M80.9 121.7h1.2M164.3 120.7h2.4M164.9 121.7h1.2" fill="none" stroke="#231f20" stroke-width=".42"/>
<path d="M92.4 116.4v2M165.4 113.7v4.9" fill="none" stroke="#fff" stroke-width=".71" stroke-linecap="butt"/>
<g fill="#231f20">
<circle cx="154.2" cy="112.5" r=".79"/>
<circle cx="154.2" cy="122.6" r=".79"/>
</g>
<path d="M154.2 116.4v2" fill="none" stroke="#fff" stroke-width=".71" stroke-linecap="butt"/>
<path d="M151.5 116.4h5.5M151.5 118.4h5.5M159.1 127.4v20.6" fill="none" stroke="#231f20" stroke-width=".42"/>
<circle cx="159.1" cy="137.2" r=".79" fill="#231f20"/>
<path d="M159.1 129.6v4.8M159.1 139.8v4.8" fill="none" stroke="#fff" stroke-width=".71" stroke-linecap="butt"/>
<path d="M89.2 127.4v20.6M159 129.4l1 .4-1.8 .9 1.8 .9-1.8 .8 1.8 .9-1.8 .8 1 .5M159 139.6l1 .4-1.8 .9 1.8 .8-1.8 .9 1.8 .8-1.8 .9 1 .5M157.3 146.6h3.7M157.9 147.6h2.4M158.5 148.6h1.2" fill="none" stroke="#231f20" stroke-width=".42"/>
<path d="M159.1 146.6v2.3" fill="none" stroke="#fff" stroke-width=".97" stroke-linecap="butt"/>
<circle cx="89.2" cy="137.2" r=".79" fill="#231f20"/>
<path d="M89.2 129.6v4.8M89.2 139.8v4.8" fill="none" stroke="#fff" stroke-width=".71" stroke-linecap="butt"/>
<path d="M89.1 129.4l1 .4-1.8 .9 1.8 .9-1.8 .8 1.8 .9-1.8 .8 1 .5M89.1 139.6l1 .4-1.8 .9 1.8 .8-1.8 .9 1.8 .8-1.8 .9 1 .5M181.4 122.9v12.7M87.4 146.6h3.6M88 147.6h2.4M88.6 148.6h1.2" fill="none" stroke="#231f20" stroke-width=".42"/>
<path d="M89.2 146.6v2.3" fill="none" stroke="#fff" stroke-width=".97" stroke-linecap="butt"/>
<circle cx="181.4" cy="122.8" r=".79" fill="#231f20"/>
<path d="M181.5 126.6v1.6" fill="none" stroke="#fff" stroke-width=".71" stroke-linecap="butt"/>
<path d="M178.7 129.1a4.7 4.7 0 0 1 5.6 0M178.7 126.6h5.6" fill="none" stroke="#231f20" stroke-width=".42"/>
<circle cx="181.4" cy="132.7" r=".79" fill="#231f20"/>
<path d="M181.4 134.8v2.2" fill="none" stroke="#fff" stroke-width=".97" stroke-linecap="butt"/>
<path d="M70.7 126.2h5.5M70.7 128.2h5.5M73.5 122.8v9.6h-12.9M179.6 134.8h3.6M180.2 135.7h2.4M180.8 136.7h1.2" fill="none" stroke="#231f20" stroke-width=".42"/>
<path d="M73.5 126.3v1.9" fill="none" stroke="#fff" stroke-width=".71" stroke-linecap="butt"/>
<circle cx="73.5" cy="122.8" r=".79" fill="#231f20"/>
<path d="M60.6 122.9v12.4" fill="none" stroke="#231f20" stroke-width=".42"/>
<circle cx="60.6" cy="122.8" r=".79" fill="#231f20"/>
<path d="M60.7 126.6v1.6" fill="none" stroke="#fff" stroke-width=".71" stroke-linecap="butt"/>
<path d="M57.8 129.1a4.7 4.7 0 0 1 5.7 0M57.9 126.6h5.5" fill="none" stroke="#231f20" stroke-width=".42"/>
<circle cx="60.6" cy="132.3" r=".79" fill="#231f20"/>
<path d="M60.6 134.3v2.3" fill="none" stroke="#fff" stroke-width=".97" stroke-linecap="butt"/>
<path d="M51.8 57.3h5.6M51.8 59.2h5.6M54.6 53.8v9.2h-12.9M58.8 134.3h3.6M59.4 135.3h2.4M60 136.3h1.2" fill="none" stroke="#231f20" stroke-width=".42"/>
<path d="M54.6 57.3v1.9" fill="none" stroke="#fff" stroke-width=".71" stroke-linecap="butt"/>
<circle cx="54.6" cy="53.8" r=".79" fill="#231f20"/>
<path d="M41.7 53.9v12.2" fill="none" stroke="#231f20" stroke-width=".42"/>
<circle cx="41.7" cy="53.8" r=".79" fill="#231f20"/>
<path d="M41.8 57.6v1.6" fill="none" stroke="#fff" stroke-width=".71" stroke-linecap="butt"/>
<path d="M39 57.6h5.6M39 60.2a4.7 4.7 0 0 1 5.6 0" fill="none" stroke="#231f20" stroke-width=".42"/>
<circle cx="41.7" cy="62.8" r=".79" fill="#231f20"/>
<path d="M41.7 64.8v2.2" fill="none" stroke="#fff" stroke-width=".97" stroke-linecap="butt"/>
<path d="M39.9 64.8h3.6M40.5 65.8h2.4M41.1 66.8h1.2" fill="none" stroke="#231f20" stroke-width=".42"/>
<circle cx="76.6" cy="53.8" r=".79" fill="#231f20"/>
<path d="M45 90.3h25.2v12.7h-25.2z" fill="#fff" stroke="#231f20" stroke-width=".42"/>
<g fill="#231f20">
<circle cx="149.5" cy="96" r=".79"/>
<circle cx="102" cy="96" r=".79"/>
<circle cx="73.4" cy="96.9" r=".79"/>
</g>
<path d="M30.5 96v1.9" fill="none" stroke="#fff" stroke-width=".71" stroke-linecap="butt"/>
<path d="M27.7 96h5.6M27.7 97.9h5.6" fill="none" stroke="#231f20" stroke-width=".42"/>
<circle cx="30.5" cy="92.9" r=".79" fill="#231f20"/>
<path d="M21.1 96.6v4.8" fill="none" stroke="#fff" stroke-width=".71" stroke-linecap="butt"/>
<path d="M21 96.4l1 .4-1.8 .9 1.8 .8-1.8 .9 1.8 .8-1.8 .9 .9 .5" fill="none" stroke="#231f20" stroke-width=".42"/>
<use href="#words"/>
</svg>
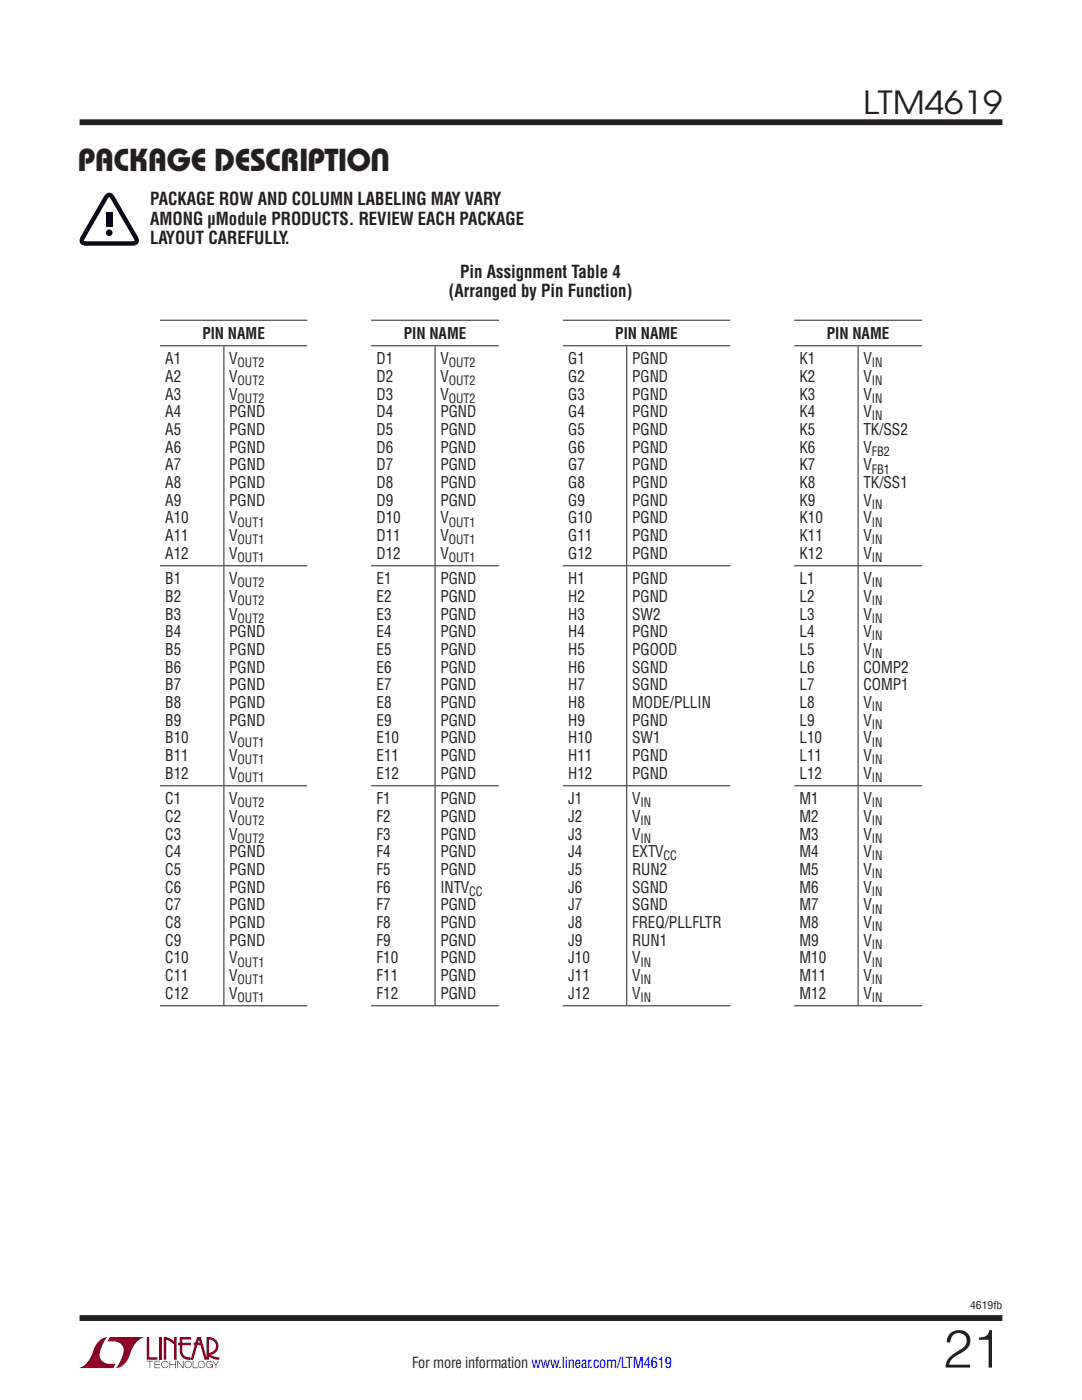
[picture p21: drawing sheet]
<svg xmlns="http://www.w3.org/2000/svg" width="216mm" height="279mm" viewBox="0 0 216 279" stroke-linecap="round" stroke-linejoin="round" font-family="sans-serif">
<defs><g id="words">
<text font-size="10.6" fill="#231f20" x="188.2" y="272.9">21</text>
<g font-size="6.3" fill="#231f20">
<text x="172.2" y="22.8">LTM4619</text>
<text x="15.5" y="34.1">Package Description</text>
</g>
<g font-size="3.5" fill="#231f20">
<text x="30" y="41">PACKAGE ROW AND COLUMN LABELING MAY VARY</text>
<text x="30" y="44.9">AMONG µModule PRODUCTS. REVIEW EACH PACKAGE</text>
<text x="30" y="48.7">LAYOUT CAREFULLY.</text>
<text x="89.6" y="59.3">(Arranged by Pin Function)</text>
<text x="91.8" y="55.4">Pin Assignment Table 4</text>
</g>
<g font-size="3.2" fill="#231f20">
<text x="40.4" y="67.6">PIN NAME</text>
<text x="80.6" y="67.6">PIN NAME</text>
<text x="122.8" y="67.6">PIN NAME</text>
<text x="165" y="67.6">PIN NAME</text>
<text x="33" y="76.2">A2</text>
<text x="33" y="72.7">A1</text>
<text x="45.7" y="72.7">V</text>
<text x="45.7" y="76.2">V</text>
<text x="75.1" y="72.7">D1</text>
<text x="75.1" y="76.2">D2</text>
<text x="87.9" y="76.2">V</text>
<text x="87.9" y="72.7">V</text>
<text x="113.4" y="72.7">G1</text>
<text x="113.4" y="76.2">G2</text>
<text x="126.1" y="72.7">PGND</text>
<text x="126.1" y="76.2">PGND</text>
<text x="159.5" y="72.7">K1</text>
<text x="159.5" y="76.2">K2</text>
<text x="172.3" y="72.7">V</text>
<text x="172.3" y="76.2">V</text>
<text x="33" y="79.8">A3</text>
<text x="33" y="83.3">A4</text>
<text x="45.7" y="79.8">V</text>
<text x="45.7" y="83.3">PGND</text>
<text x="75.1" y="79.8">D3</text>
<text x="75.1" y="83.3">D4</text>
<text x="87.9" y="79.8">V</text>
<text x="87.9" y="83.3">PGND</text>
<text x="113.4" y="79.8">G3</text>
<text x="113.4" y="83.3">G4</text>
<text x="126.1" y="79.7">PGND</text>
<text x="126.1" y="83.3">PGND</text>
<text x="159.5" y="79.7">K3</text>
<text x="159.5" y="83.3">K4</text>
<text x="172.3" y="83.3">V</text>
<text x="172.3" y="79.8">V</text>
<text x="33" y="86.8">A5</text>
<text x="45.7" y="86.8">PGND</text>
<text x="75.1" y="86.8">D5</text>
<text x="87.9" y="86.8">PGND</text>
<text x="113.4" y="86.8">G5</text>
<text x="126.1" y="86.8">PGND</text>
<text x="159.5" y="86.8">K5</text>
<text x="172.3" y="86.8">TK/SS2</text>
<text x="33" y="90.3">A6</text>
<text x="33" y="93.9">A7</text>
<text x="45.7" y="90.3">PGND</text>
<text x="45.7" y="93.9">PGND</text>
<text x="75.1" y="90.3">D6</text>
<text x="75.1" y="93.9">D7</text>
<text x="87.9" y="90.3">PGND</text>
<text x="87.9" y="93.9">PGND</text>
<text x="113.4" y="90.3">G6</text>
<text x="113.4" y="93.9">G7</text>
<text x="126.1" y="90.3">PGND</text>
<text x="126.1" y="93.9">PGND</text>
<text x="159.5" y="90.3">K6</text>
<text x="159.5" y="93.9">K7</text>
<text x="172.3" y="93.9">V</text>
<text x="172.3" y="90.3">V</text>
<text x="33" y="97.4">A8</text>
<text x="33" y="100.9">A9</text>
<text x="45.7" y="97.4">PGND</text>
<text x="45.7" y="100.9">PGND</text>
<text x="75.1" y="97.4">D8</text>
<text x="75.1" y="100.9">D9</text>
<text x="87.9" y="97.4">PGND</text>
<text x="87.9" y="100.9">PGND</text>
<text x="113.4" y="97.4">G8</text>
<text x="113.4" y="100.9">G9</text>
<text x="126.1" y="97.4">PGND</text>
<text x="126.1" y="100.9">PGND</text>
<text x="159.5" y="97.4">K8</text>
<text x="159.5" y="100.9">K9</text>
<text x="172.3" y="97.4">TK/SS1</text>
<text x="172.3" y="100.9">V</text>
<text x="33" y="104.4">A10</text>
<text x="33" y="108">A11</text>
<text x="45.7" y="104.4">V</text>
<text x="45.7" y="108">V</text>
<text x="75.1" y="104.4">D10</text>
<text x="75.1" y="108">D11</text>
<text x="87.9" y="104.4">V</text>
<text x="87.9" y="108">V</text>
<text x="113.4" y="104.4">G10</text>
<text x="113.4" y="108">G11</text>
<text x="126.1" y="104.4">PGND</text>
<text x="126.1" y="108">PGND</text>
<text x="159.5" y="104.4">K10</text>
<text x="159.5" y="108">K11</text>
<text x="172.3" y="104.4">V</text>
<text x="172.3" y="108">V</text>
<text x="33" y="111.5">A12</text>
<text x="45.7" y="111.5">V</text>
<text x="75.1" y="111.5">D12</text>
<text x="87.9" y="111.5">V</text>
<text x="113.4" y="111.5">G12</text>
<text x="126.1" y="111.5">PGND</text>
<text x="159.5" y="111.5">K12</text>
<text x="172.3" y="111.5">V</text>
<text x="33" y="116.6">B1</text>
<text x="45.7" y="116.6">V</text>
<text x="75.1" y="116.6">E1</text>
<text x="87.9" y="116.6">PGND</text>
<text x="113.4" y="116.6">H1</text>
<text x="126.1" y="116.6">PGND</text>
<text x="159.5" y="116.6">L1</text>
<text x="172.3" y="116.6">V</text>
<text x="33" y="120.1">B2</text>
<text x="33" y="123.7">B3</text>
<text x="45.7" y="120.1">V</text>
<text x="45.7" y="123.7">V</text>
<text x="75.1" y="120.1">E2</text>
<text x="75.1" y="123.7">E3</text>
<text x="87.9" y="120.1">PGND</text>
<text x="87.9" y="123.7">PGND</text>
<text x="113.4" y="120.1">H2</text>
<text x="113.4" y="123.7">H3</text>
<text x="126.1" y="120.1">PGND</text>
<text x="126.1" y="123.6">SW2</text>
<text x="159.5" y="120.1">L2</text>
<text x="159.5" y="123.6">L3</text>
<text x="172.3" y="120.1">V</text>
<text x="172.3" y="123.7">V</text>
<text x="33" y="127.2">B4</text>
<text x="33" y="130.7">B5</text>
<text x="45.7" y="127.2">PGND</text>
<text x="45.7" y="130.7">PGND</text>
<text x="75.1" y="127.2">E4</text>
<text x="75.1" y="130.7">E5</text>
<text x="87.9" y="127.2">PGND</text>
<text x="87.9" y="130.7">PGND</text>
<text x="113.4" y="127.2">H4</text>
<text x="113.4" y="130.7">H5</text>
<text x="126.1" y="127.2">PGND</text>
<text x="126.1" y="130.7">PGOOD</text>
<text x="159.5" y="127.2">L4</text>
<text x="159.5" y="130.7">L5</text>
<text x="172.3" y="127.2">V</text>
<text x="172.3" y="130.7">V</text>
<text x="33" y="134.2">B6</text>
<text x="33" y="137.8">B7</text>
<text x="45.7" y="134.2">PGND</text>
<text x="45.7" y="137.8">PGND</text>
<text x="75.1" y="134.2">E6</text>
<text x="75.1" y="137.8">E7</text>
<text x="87.9" y="134.2">PGND</text>
<text x="87.9" y="137.8">PGND</text>
<text x="113.4" y="134.2">H6</text>
<text x="113.4" y="137.8">H7</text>
<text x="126.1" y="134.2">SGND</text>
<text x="126.1" y="137.8">SGND</text>
<text x="159.5" y="134.2">L6</text>
<text x="159.5" y="137.8">L7</text>
<text x="172.3" y="134.2">COMP2</text>
<text x="172.3" y="137.8">COMP1</text>
<text x="33" y="141.3">B8</text>
<text x="45.7" y="141.3">PGND</text>
<text x="75.1" y="141.3">E8</text>
<text x="87.9" y="141.3">PGND</text>
<text x="113.4" y="141.3">H8</text>
<text x="126.1" y="141.3">MODE/PLLIN</text>
<text x="159.5" y="141.3">L8</text>
<text x="172.3" y="141.3">V</text>
<text x="33" y="144.8">B9</text>
<text x="33" y="148.3">B10</text>
<text x="45.7" y="144.8">PGND</text>
<text x="45.7" y="148.4">V</text>
<text x="75.1" y="144.8">E9</text>
<text x="75.1" y="148.3">E10</text>
<text x="87.9" y="144.8">PGND</text>
<text x="87.9" y="148.3">PGND</text>
<text x="113.4" y="144.8">H9</text>
<text x="113.4" y="148.3">H10</text>
<text x="126.1" y="144.8">PGND</text>
<text x="126.1" y="148.3">SW1</text>
<text x="159.5" y="144.8">L9</text>
<text x="159.5" y="148.3">L10</text>
<text x="172.3" y="144.8">V</text>
<text x="172.3" y="148.4">V</text>
<text x="33" y="151.9">B11</text>
<text x="33" y="155.4">B12</text>
<text x="45.7" y="151.9">V</text>
<text x="45.7" y="155.4">V</text>
<text x="75.1" y="151.9">E11</text>
<text x="75.1" y="155.4">E12</text>
<text x="87.9" y="151.9">PGND</text>
<text x="87.9" y="155.4">PGND</text>
<text x="113.4" y="151.9">H11</text>
<text x="113.4" y="155.4">H12</text>
<text x="126.1" y="151.9">PGND</text>
<text x="126.1" y="155.4">PGND</text>
<text x="159.5" y="151.9">L11</text>
<text x="159.5" y="155.4">L12</text>
<text x="172.3" y="151.9">V</text>
<text x="172.3" y="155.4">V</text>
<text x="33" y="160.5">C1</text>
<text x="45.7" y="160.5">V</text>
<text x="75.1" y="160.5">F1</text>
<text x="87.9" y="160.5">PGND</text>
<text x="113.4" y="160.5">J1</text>
<text x="126.1" y="160.5">V</text>
<text x="159.5" y="160.5">M1</text>
<text x="172.3" y="160.5">V</text>
<text x="33" y="164">C2</text>
<text x="33" y="167.6">C3</text>
<text x="45.7" y="164">V</text>
<text x="45.7" y="167.6">V</text>
<text x="75.1" y="164">F2</text>
<text x="75.1" y="167.6">F3</text>
<text x="87.9" y="164">PGND</text>
<text x="87.9" y="167.6">PGND</text>
<text x="113.4" y="164">J2</text>
<text x="113.4" y="167.6">J3</text>
<text x="126.1" y="164">V</text>
<text x="126.1" y="167.6">V</text>
<text x="159.5" y="164">M2</text>
<text x="159.5" y="167.6">M3</text>
<text x="172.3" y="164">V</text>
<text x="172.3" y="167.6">V</text>
<text x="33" y="171.1">C4</text>
<text x="45.7" y="171.1">PGND</text>
<text x="75.1" y="171.1">F4</text>
<text x="87.9" y="171.1">PGND</text>
<text x="113.4" y="171.1">J4</text>
<text x="126.1" y="171.1">EXTV</text>
<text x="159.5" y="171.1">M4</text>
<text x="172.3" y="171.1">V</text>
<text x="33" y="174.6">C5</text>
<text x="33" y="178.1">C6</text>
<text x="45.7" y="174.6">PGND</text>
<text x="45.7" y="178.1">PGND</text>
<text x="75.1" y="174.6">F5</text>
<text x="75.1" y="178.1">F6</text>
<text x="87.9" y="174.6">PGND</text>
<text x="87.9" y="178.1">INTV</text>
<text x="113.4" y="174.6">J5</text>
<text x="113.4" y="178.1">J6</text>
<text x="126.1" y="174.6">RUN2</text>
<text x="126.1" y="178.1">SGND</text>
<text x="159.5" y="174.6">M5</text>
<text x="159.5" y="178.1">M6</text>
<text x="172.3" y="174.6">V</text>
<text x="172.3" y="178.1">V</text>
<text x="33" y="181.7">C7</text>
<text x="33" y="185.2">C8</text>
<text x="45.7" y="181.7">PGND</text>
<text x="45.7" y="185.2">PGND</text>
<text x="75.1" y="181.7">F7</text>
<text x="75.1" y="185.2">F8</text>
<text x="87.9" y="181.7">PGND</text>
<text x="87.9" y="185.2">PGND</text>
<text x="113.4" y="181.7">J7</text>
<text x="113.4" y="185.2">J8</text>
<text x="126.1" y="181.7">SGND</text>
<text x="126.1" y="185.2">FREQ/PLLFLTR</text>
<text x="159.5" y="181.7">M7</text>
<text x="159.5" y="185.2">M8</text>
<text x="172.3" y="181.7">V</text>
<text x="172.3" y="185.2">V</text>
<text x="33" y="188.7">C9</text>
<text x="45.7" y="188.7">PGND</text>
<text x="75.1" y="188.7">F9</text>
<text x="87.9" y="188.7">PGND</text>
<text x="113.4" y="188.7">J9</text>
<text x="126.1" y="188.7">RUN1</text>
<text x="159.5" y="188.7">M9</text>
<text x="172.3" y="188.7">V</text>
<text x="33" y="192.3">C10</text>
<text x="33" y="195.8">C11</text>
<text x="45.7" y="192.3">V</text>
<text x="45.7" y="195.8">V</text>
<text x="75.1" y="192.3">F10</text>
<text x="75.1" y="195.8">F11</text>
<text x="87.9" y="192.3">PGND</text>
<text x="87.9" y="195.8">PGND</text>
<text x="113.4" y="192.3">J10</text>
<text x="113.4" y="195.8">J11</text>
<text x="126.1" y="192.3">V</text>
<text x="126.1" y="195.8">V</text>
<text x="159.5" y="192.3">M10</text>
<text x="159.5" y="195.8">M11</text>
<text x="172.3" y="192.3">V</text>
<text x="172.3" y="195.8">V</text>
<text x="33" y="199.3">C12</text>
<text x="45.7" y="199.3">V</text>
<text x="75.1" y="199.3">F12</text>
<text x="87.9" y="199.3">PGND</text>
<text x="113.4" y="199.3">J12</text>
<text x="126.1" y="199.3">V</text>
<text x="159.5" y="199.3">M12</text>
<text x="172.3" y="199.3">V</text>
</g>
<text font-size="3" fill="#231f20" x="82.2" y="273.1">For more information www.linear.com/LTM4619</text>
<g font-size="2.5" fill="#231f20">
<text x="47.4" y="73.3">OUT2</text>
<text x="47.4" y="76.9">OUT2</text>
<text x="89.5" y="73.3">OUT2</text>
<text x="89.5" y="76.9">OUT2</text>
<text x="174" y="73.3">IN</text>
<text x="174" y="76.9">IN</text>
<text x="47.4" y="80.4">OUT2</text>
<text x="89.5" y="80.4">OUT2</text>
<text x="174" y="80.4">IN</text>
<text x="174" y="83.9">IN</text>
<text x="174" y="91">FB2</text>
<text x="174" y="94.5">FB1</text>
<text x="174" y="101.6">IN</text>
<text x="47.4" y="105.1">OUT1</text>
<text x="89.5" y="105.1">OUT1</text>
<text x="174" y="105.1">IN</text>
<text x="47.4" y="108.6">OUT1</text>
<text x="47.4" y="112.1">OUT1</text>
<text x="89.5" y="108.6">OUT1</text>
<text x="89.5" y="112.1">OUT1</text>
<text x="174" y="108.6">IN</text>
<text x="174" y="112.1">IN</text>
<text x="47.4" y="117.2">OUT2</text>
<text x="174" y="117.2">IN</text>
<text x="47.4" y="120.8">OUT2</text>
<text x="47.4" y="124.3">OUT2</text>
<text x="174" y="120.8">IN</text>
<text x="174" y="124.3">IN</text>
<text x="174" y="127.8">IN</text>
<text x="174" y="131.3">IN</text>
<text x="174" y="141.9">IN</text>
<text x="47.4" y="149">OUT1</text>
<text x="174" y="145.5">IN</text>
<text x="174" y="149">IN</text>
<text x="47.4" y="152.5">OUT1</text>
<text x="174" y="152.5">IN</text>
<text x="47.4" y="156">OUT1</text>
<text x="47.4" y="161.1">OUT2</text>
<text x="127.8" y="161.1">IN</text>
<text x="174" y="156">IN</text>
<text x="174" y="161.1">IN</text>
<text x="47.4" y="164.7">OUT2</text>
<text x="127.8" y="164.7">IN</text>
<text x="174" y="164.7">IN</text>
<text x="47.4" y="168.2">OUT2</text>
<text x="127.8" y="168.2">IN</text>
<text x="132.4" y="171.7">CC</text>
<text x="174" y="168.2">IN</text>
<text x="174" y="171.7">IN</text>
<text x="93.6" y="178.8">CC</text>
<text x="174" y="175.3">IN</text>
<text x="174" y="178.8">IN</text>
<text x="174" y="182.3">IN</text>
<text x="174" y="185.8">IN</text>
<text x="174" y="189.4">IN</text>
<text x="47.4" y="192.9">OUT1</text>
<text x="47.4" y="196.4">OUT1</text>
<text x="127.8" y="192.9">IN</text>
<text x="127.8" y="196.4">IN</text>
<text x="174" y="192.9">IN</text>
<text x="174" y="196.4">IN</text>
<text x="47.4" y="200">OUT1</text>
<text x="127.8" y="200">IN</text>
<text x="174" y="200">IN</text>
</g>
<text font-size="2.1" fill="#231f20" x="193.6" y="261.2">4619fb</text>
</g></defs>
<g fill="#900126">
<path d="M29.3 266.8h.5v4.1h1.6v.5h-2.1z"/>
<path d="M20 267.4l1-.5h.5h-.1a6.2 6.2 0 0 0-1.5 4 2.58 2.58 0 0 0 3.2 1.3l-.5 .8h-7a4.9 4.9 0 0 0 3.1-3.8l.4-.7z"/>
<path d="M21.9 266.9h7a4.9 4.9 0 0 0-3.1 3.7 3.2 3.2 0 0 1-2.7 2.4h.1a6.2 6.2 0 0 0 1.4-4.1 2.58 2.58 0 0 0-3.1-1.2z"/>
<path d="M31.8 266.8h.5v4.6h-.5z"/>
<path d="M32.7 266.8l1 .2 1 .7v-.9h.5v4.6h-.5v-3.1l-1.5-.9v4h-.5z"/>
<path d="M29.3 271.6h1.3v.1h-.6v1.3h-.2v-1.3h-.5z"/>
<path d="M30.8 271.6h1.2v.1h-1v.5h.9v.2h-.9v.5h1v.1h-1.2z"/>
<path d="M33.8 271.6h.2v.6h1v-.6h.1v1.4h-.1v-.6h-1v.6h-.2z"/>
<path d="M35.4 271.6h.1l1 1.2v-1.2h.1v1.4l-1.1-1.2v1.2h-.1z"/>
<path d="M38.5 271.6h.1v1.3h.9v.1h-1z"/>
<path d="M42.4 271.6h.1l.6 .7 .5-.7h.2l-.7 .8v.6h-.1v-.6z"/>
<path d="M35.9 266.8h2.2v.5h-1.7v.7h1.7v.5h-1.7v1.1a1.32 1.32 0 0 0 1.6 1.3v.5l1.3-4.6h.8l1.1 4.1v-4.1a1.84 1.84 0 0 1 2.3 1.4 1.84 1.84 0 0 1-1.4 2.2l.7 .4 1 .1v.5l-1.2-.2-1.1-.6v-.6a1.34 1.34 0 0 0 1.6-1.2 1.34 1.34 0 0 0-1.4-1.5v4.1h-.9l-.8-2.9h-1.3v-.5h1.2l-.2-.7-1.1 4.1a2.06 2.06 0 0 1-2.7-1.3v-1.6h-.4v-.5h.4z"/>
<path d="M37 271.8a.72 .72 0 0 1 1.2 .1 .72 .72 0 0 1-.4 1.1 .72 .72 0 0 1-1-.7h.2a.59 .59 0 0 0 .8 .5 .59 .59 0 0 0 .2-.9 .59 .59 0 0 0-1 .2v.2h-.2z"/>
<path d="M39.7 271.8a.72 .72 0 0 1 1.1 .1 .72 .72 0 0 1-.4 1.1 .72 .72 0 0 1-.9-.7h.1a.59 .59 0 0 0 .8 .5 .59 .59 0 0 0 .2-.9 .59 .59 0 0 0-1 .2v.2h-.1z"/>
<path d="M41.3 271.8a.72 .72 0 0 1 1.2 .2h-.2a.59 .59 0 0 0-.9-.1 .59 .59 0 0 0 .1 .9 .59 .59 0 0 0 .9-.4h-.5v-.1h.6v.7h-.1v-.3a.73 .73 0 0 1-1.1 .2 .73 .73 0 0 1 0-1.1z"/>
<path d="M32.4 271.8a.71 .71 0 0 1 1.2 .3h-.1a.59 .59 0 0 0-.9-.3 .59 .59 0 0 0-.1 1 .59 .59 0 0 0 .9-.3h.2a.73 .73 0 0 1-1.1 .4 .73 .73 0 0 1-.1-1.1z"/>
</g>
<path d="M15.9 24.4h184.1M15.9 263h184.1" fill="none" stroke="#231f20" stroke-width="1.2" stroke-linecap="butt"/>
<g fill="none" stroke="#231f20" stroke-width=".2">
<path d="M31.9 69h29.4M31.9 63.9h29.4M44.7 69.1v43.7M74.1 69h25.5M74.1 63.9h25.5M86.8 69.1v43.7M112.3 69h33.4M112.3 63.9h33.4M125.1 69.1v43.7M158.5 69h25.5M158.5 63.9h25.5M171.2 69.1v43.7"/>
<path d="M31.9 112.9h29.4M44.7 113v43.7M74.1 112.9h25.5M86.8 113v43.7M112.3 112.9h33.4M125.1 113v43.7M158.5 112.9h25.5M171.2 113v43.7M31.9 156.8h29.4M44.7 156.9v43.7M74.1 156.8h25.5M86.8 156.9v43.7"/>
<path d="M112.3 156.8h33.4M125.1 156.9v43.7M158.5 156.8h25.5M171.2 156.9v43.7M31.9 200.7h29.4M74.1 200.7h25.5M112.3 200.7h33.4M158.5 200.7h25.5"/>
</g>
<g fill="#040503">
<path d="M21.2 42.5h1.2v2.8h-1.2z"/>
<path d="M21.7 39.4h.2l.2 .2 4.7 8.5h-10zM21 38.9l-4.9 8.3a1.11 1.11 0 0 0-.1 1.3 1.11 1.11 0 0 0 1.2 .5h9.2a1.11 1.11 0 0 0 1.2-.5 1.11 1.11 0 0 0-.1-1.3l-4.7-8a1.08 1.08 0 0 0-1.8-.3z"/>
<circle cx="21.8" cy="46.5" r=".66"/>
</g>
<use href="#words"/>
</svg>
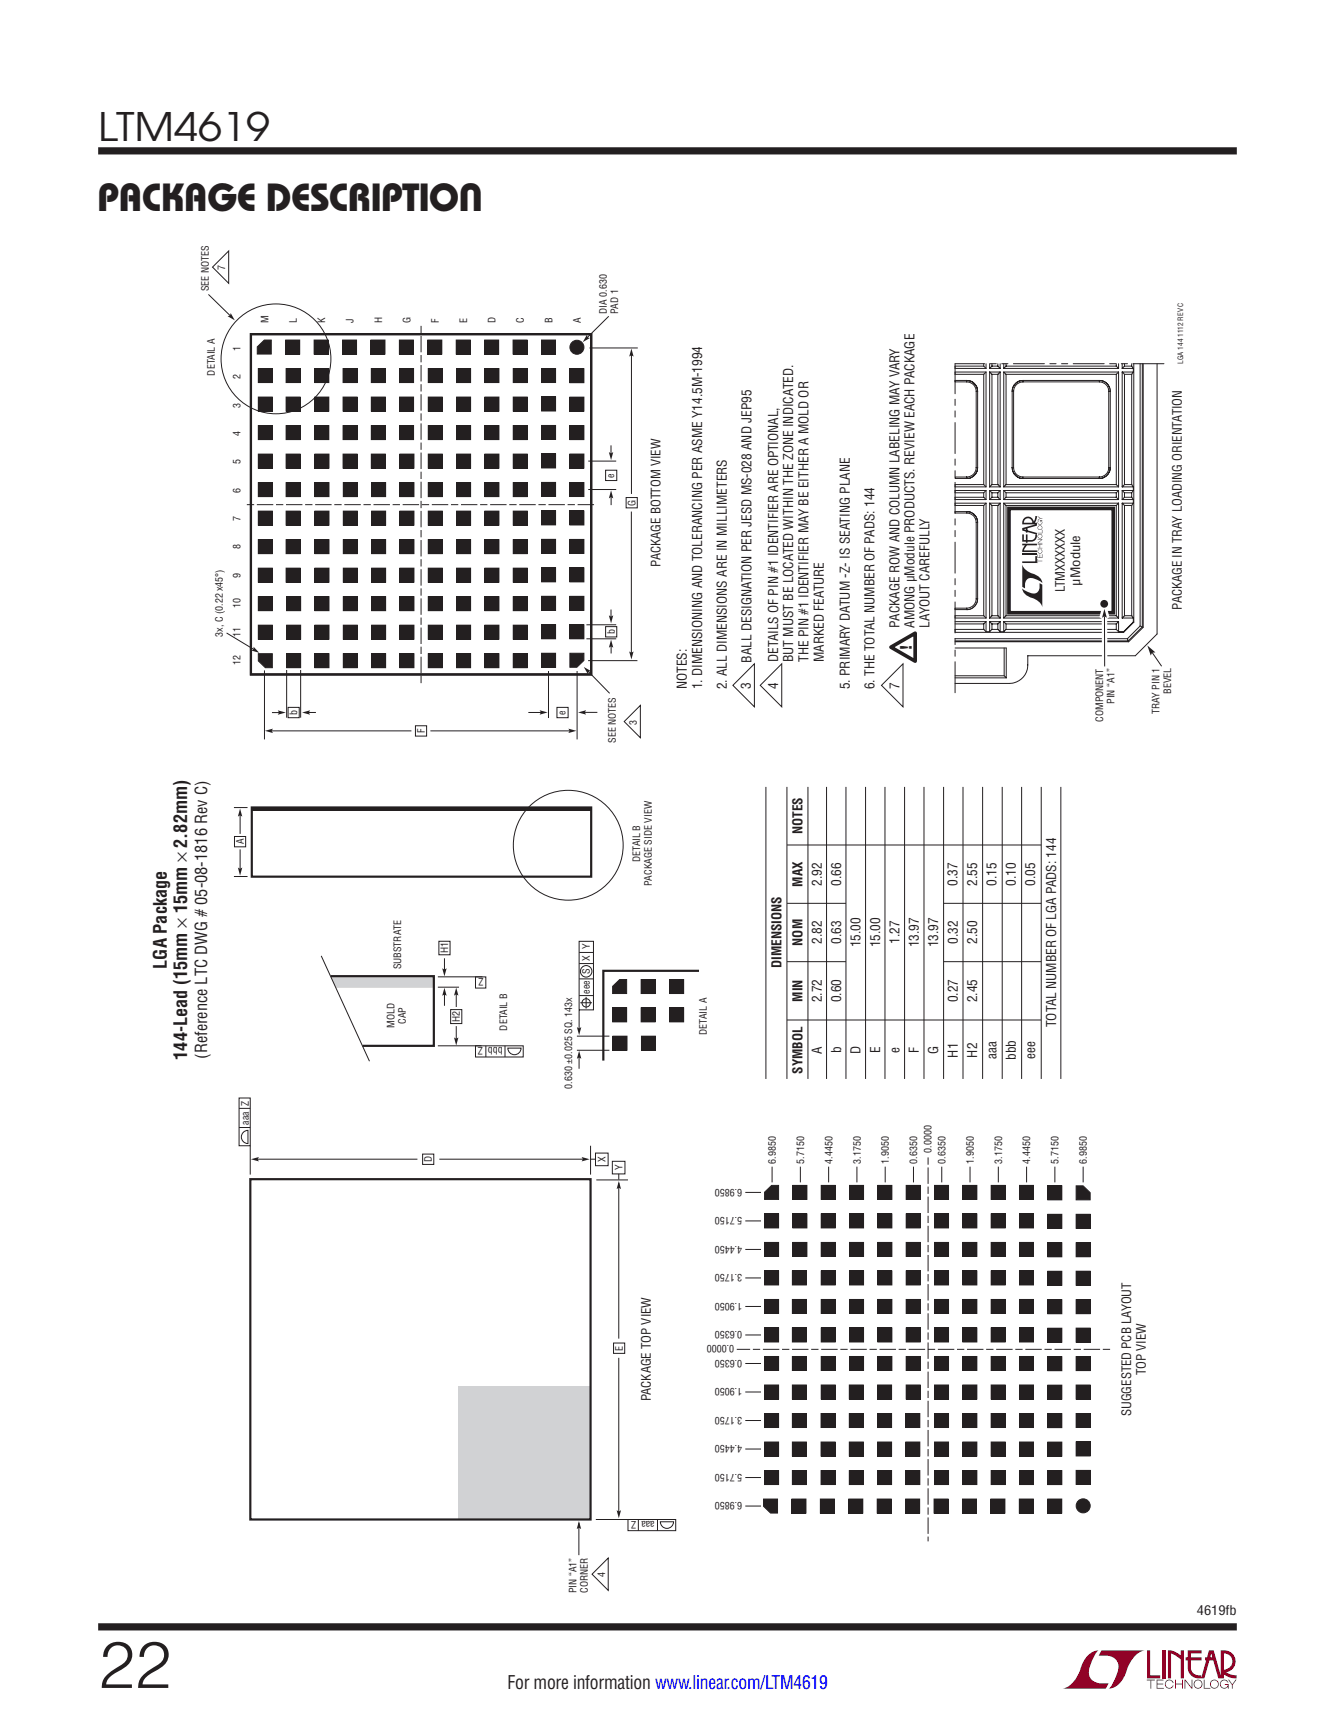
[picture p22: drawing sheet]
<svg xmlns="http://www.w3.org/2000/svg" width="216mm" height="279mm" viewBox="0 0 216 279" stroke-linecap="round" stroke-linejoin="round" font-family="sans-serif">
<defs><g id="words">
<text font-size="10.6" fill="#231f20" x="15.9" y="272.9">22</text>
<g font-size="6.3" fill="#231f20">
<text x="15.9" y="22.8">LTM4619</text>
<text x="15.8" y="34.1">Package Description</text>
</g>
<text font-size="3" fill="#231f20" x="82.1" y="273.1">For more information www.linear.com/LTM4619</text>
<g font-size="2.9" fill="#231f20">
<text x="27" y="156.6" transform="rotate(-90 27 156.6)">LGA Package</text>
<text x="30.2" y="171.3" transform="rotate(-90 30.2 171.3)">144-Lead (15mm × 15mm × 2.82mm)</text>
</g>
<text font-size="2.7" fill="#231f20" x="33.5" y="171.2" transform="rotate(-90 33.5 171.2)">(Reference LTC DWG # 05-08-1816 Rev C)</text>
<text font-size="2.5" fill="#231f20" x="147.5" y="105.1" transform="rotate(-90 147.5 105.1)">!</text>
<g font-size="2.2" fill="#231f20">
<text x="145.4" y="101.5" transform="rotate(-90 145.4 101.5)">PACKAGE ROW AND COLUMN LABELING MAY VARY</text>
<text x="147.9" y="101.5" transform="rotate(-90 147.9 101.5)">AMONG µModule PRODUCTS. REVIEW EACH PACKAGE</text>
<text x="150.3" y="101.5" transform="rotate(-90 150.3 101.5)">LAYOUT CAREFULLY</text>
<text x="121.5" y="107.1" transform="rotate(-90 121.5 107.1)">BALL DESIGNATION PER JESD MS-028 AND JEP95</text>
<text x="125.8" y="107.1" transform="rotate(-90 125.8 107.1)">DETAILS OF PIN #1 IDENTIFIER ARE OPTIONAL,</text>
<text x="128.3" y="107.1" transform="rotate(-90 128.3 107.1)">BUT MUST BE LOCATED WITHIN THE ZONE INDICATED.</text>
<text x="130.8" y="107.1" transform="rotate(-90 130.8 107.1)">THE PIN #1 IDENTIFIER MAY BE EITHER A MOLD OR</text>
<text x="133.2" y="107.1" transform="rotate(-90 133.2 107.1)">MARKED FEATURE</text>
<text x="111.1" y="111.5" transform="rotate(-90 111.1 111.5)">NOTES:</text>
<text x="113.5" y="111.5" transform="rotate(-90 113.5 111.5)">1. DIMENSIONING AND TOLERANCING PER ASME Y14.5M-1994</text>
<text x="117.5" y="111.5" transform="rotate(-90 117.5 111.5)">2. ALL DIMENSIONS ARE IN MILLIMETERS</text>
<text x="121.4" y="111.4" transform="rotate(-90 121.4 111.4)">3</text>
<text x="125.8" y="111.4" transform="rotate(-90 125.8 111.4)">4</text>
<text x="137.4" y="111.5" transform="rotate(-90 137.4 111.5)">5. PRIMARY DATUM -Z- IS SEATING PLANE</text>
<text x="141.4" y="111.5" transform="rotate(-90 141.4 111.5)">6. THE TOTAL NUMBER OF PADS: 144</text>
<text x="145.4" y="111.4" transform="rotate(-90 145.4 111.4)">7</text>
<text x="129.8" y="134.9" transform="rotate(-90 129.8 134.9)">NOTES</text>
<text x="129.8" y="143.4" transform="rotate(-90 129.8 143.4)">MAX</text>
<text x="132.9" y="143.2" transform="rotate(-90 132.9 143.2)">2.92</text>
<text x="136" y="143.2" transform="rotate(-90 136 143.2)">0.66</text>
<text x="154.9" y="143.2" transform="rotate(-90 154.9 143.2)">0.37</text>
<text x="158" y="143.2" transform="rotate(-90 158 143.2)">2.55</text>
<text x="161.2" y="143.2" transform="rotate(-90 161.2 143.2)">0.15</text>
<text x="164.3" y="143.2" transform="rotate(-90 164.3 143.2)">0.10</text>
<text x="167.4" y="143.2" transform="rotate(-90 167.4 143.2)">0.05</text>
<text x="129.8" y="152.9" transform="rotate(-90 129.8 152.9)">NOM</text>
<text x="132.9" y="152.6" transform="rotate(-90 132.9 152.6)">2.82</text>
<text x="136" y="152.6" transform="rotate(-90 136 152.6)">0.63</text>
<text x="139.2" y="153.2" transform="rotate(-90 139.2 153.2)">15.00</text>
<text x="142.3" y="153.2" transform="rotate(-90 142.3 153.2)">15.00</text>
<text x="145.5" y="152.6" transform="rotate(-90 145.5 152.6)">1.27</text>
<text x="148.6" y="153.2" transform="rotate(-90 148.6 153.2)">13.97</text>
<text x="151.7" y="153.2" transform="rotate(-90 151.7 153.2)">13.97</text>
<text x="154.9" y="152.6" transform="rotate(-90 154.9 152.6)">0.32</text>
<text x="158" y="152.6" transform="rotate(-90 158 152.6)">2.50</text>
<text x="126.4" y="156.6" transform="rotate(-90 126.4 156.6)">DIMENSIONS</text>
<text x="129.8" y="162" transform="rotate(-90 129.8 162)">MIN</text>
<text x="132.9" y="162.1" transform="rotate(-90 132.9 162.1)">2.72</text>
<text x="136.1" y="162.1" transform="rotate(-90 136.1 162.1)">0.60</text>
<text x="154.9" y="162.1" transform="rotate(-90 154.9 162.1)">0.27</text>
<text x="158" y="162.1" transform="rotate(-90 158 162.1)">2.45</text>
<text x="170.8" y="166.1" transform="rotate(-90 170.8 166.1)">TOTAL NUMBER OF LGA PADS: 144</text>
<text x="129.8" y="173.6" transform="rotate(-90 129.8 173.6)">SYMBOL</text>
<text x="132.9" y="170.4" transform="rotate(-90 132.9 170.4)">A</text>
<text x="136" y="170.3" transform="rotate(-90 136 170.3)">b</text>
<text x="139.2" y="170.5" transform="rotate(-90 139.2 170.5)">D</text>
<text x="142.3" y="170.3" transform="rotate(-90 142.3 170.3)">E</text>
<text x="145.5" y="170.3" transform="rotate(-90 145.5 170.3)">e</text>
<text x="148.6" y="170.3" transform="rotate(-90 148.6 170.3)">F</text>
<text x="151.7" y="170.5" transform="rotate(-90 151.7 170.5)">G</text>
<text x="154.9" y="171" transform="rotate(-90 154.9 171)">H1</text>
<text x="158" y="171" transform="rotate(-90 158 171)">H2</text>
<text x="161.2" y="171.2" transform="rotate(-90 161.2 171.2)">aaa</text>
<text x="164.3" y="171.4" transform="rotate(-90 164.3 171.4)">bbb</text>
<text x="167.4" y="171.2" transform="rotate(-90 167.4 171.2)">eee</text>
</g>
<g font-size="2.1" fill="#231f20">
<text x="106.8" y="91.6" transform="rotate(-90 106.8 91.6)">PACKAGE BOTTOM VIEW</text>
<text x="172.2" y="95.7" transform="rotate(-90 172.2 95.7)">LTMXXXXXX</text>
<text x="174.7" y="94.7" transform="rotate(-90 174.7 94.7)">µModule</text>
<text x="191.1" y="98.6" transform="rotate(-90 191.1 98.6)">PACKAGE IN TRAY LOADING ORIENTATION</text>
<text x="105.2" y="226.6" transform="rotate(-90 105.2 226.6)">PACKAGE TOP VIEW</text>
<text x="185.3" y="222.4" transform="rotate(-90 185.3 222.4)">TOP VIEW</text>
<text x="183" y="229" transform="rotate(-90 183 229)">SUGGESTED PCB LAYOUT</text>
<text x="193.6" y="261.2">4619fb</text>
</g>
<g font-size="1.6" fill="#231f20">
<text x="33.7" y="47.1" transform="rotate(-90 33.7 47.1)">SEE NOTES</text>
<text x="36.4" y="43.7" transform="rotate(-90 36.4 43.7)">7</text>
<text x="43.4" y="52.2" transform="rotate(-90 43.4 52.2)">M</text>
<text x="48" y="52.2" transform="rotate(-90 48 52.2)">L</text>
<text x="52.6" y="52.2" transform="rotate(-90 52.6 52.2)">K</text>
<text x="57.2" y="52.2" transform="rotate(-90 57.2 52.2)">J</text>
<text x="61.8" y="52.2" transform="rotate(-90 61.8 52.2)">H</text>
<text x="66.4" y="52.2" transform="rotate(-90 66.4 52.2)">G</text>
<text x="71" y="52.2" transform="rotate(-90 71 52.2)">F</text>
<text x="75.6" y="52.2" transform="rotate(-90 75.6 52.2)">E</text>
<text x="80.1" y="52.2" transform="rotate(-90 80.1 52.2)">D</text>
<text x="84.7" y="52.2" transform="rotate(-90 84.7 52.2)">C</text>
<text x="89.3" y="52.2" transform="rotate(-90 89.3 52.2)">B</text>
<text x="93.9" y="52.2" transform="rotate(-90 93.9 52.2)">A</text>
<text x="98.1" y="50.7" transform="rotate(-90 98.1 50.7)">DIA 0.630</text>
<text x="100" y="50.7" transform="rotate(-90 100 50.7)">PAD 1</text>
<text x="38.9" y="56.8" transform="rotate(-90 38.9 56.8)">1</text>
<text x="34.8" y="60.7" transform="rotate(-90 34.8 60.7)">DETAIL A</text>
<text x="38.9" y="65.9" transform="rotate(-90 38.9 65.9)">3</text>
<text x="38.9" y="61.3" transform="rotate(-90 38.9 61.3)">2</text>
<text x="38.9" y="70.5" transform="rotate(-90 38.9 70.5)">4</text>
<text x="38.9" y="75.1" transform="rotate(-90 38.9 75.1)">5</text>
<text x="99.3" y="77.2" transform="rotate(-90 99.3 77.2)">e</text>
<text x="38.9" y="79.7" transform="rotate(-90 38.9 79.7)">6</text>
<text x="102.8" y="81.8" transform="rotate(-90 102.8 81.8)">G</text>
<text x="38.9" y="88.8" transform="rotate(-90 38.9 88.8)">8</text>
<text x="38.9" y="84.2" transform="rotate(-90 38.9 84.2)">7</text>
<text x="38.9" y="93.4" transform="rotate(-90 38.9 93.4)">9</text>
<text x="38.9" y="98.4" transform="rotate(-90 38.9 98.4)">10</text>
<text x="36" y="103" transform="rotate(-90 36 103)">3x, C (0.22 x45°)</text>
<text x="38.9" y="107.5" transform="rotate(-90 38.9 107.5)">12</text>
<text x="38.9" y="103" transform="rotate(-90 38.9 103)">11</text>
<text x="99.4" y="102.5" transform="rotate(-90 99.4 102.5)">b</text>
<text x="180.2" y="113.8" transform="rotate(-90 180.2 113.8)">PIN “A1”</text>
<text x="189.4" y="112.2" transform="rotate(-90 189.4 112.2)">BEVEL</text>
<text x="48.1" y="115.6" transform="rotate(-90 48.1 115.6)">b</text>
<text x="68.7" y="118.5" transform="rotate(-90 68.7 118.5)">F</text>
<text x="91.4" y="115.6" transform="rotate(-90 91.4 115.6)">e</text>
<text x="103" y="117.2" transform="rotate(-90 103 117.2)">3</text>
<text x="178.4" y="116.7" transform="rotate(-90 178.4 116.7)">COMPONENT</text>
<text x="187.5" y="115.4" transform="rotate(-90 187.5 115.4)">TRAY PIN 1</text>
<text x="99.6" y="120.1" transform="rotate(-90 99.6 120.1)">SEE NOTES</text>
<text x="39.4" y="136.5" transform="rotate(-90 39.4 136.5)">A</text>
<text x="103.5" y="139.4" transform="rotate(-90 103.5 139.4)">DETAIL B</text>
<text x="105.4" y="143.2" transform="rotate(-90 105.4 143.2)">PACKAGE SIDE VIEW</text>
<text x="72.5" y="154.1" transform="rotate(-90 72.5 154.1)">H1</text>
<text x="95.4" y="155.4" transform="rotate(-90 95.4 155.4)">X</text>
<text x="95.4" y="153.5" transform="rotate(-90 95.4 153.5)">Y</text>
<text x="64.9" y="156.7" transform="rotate(-90 64.9 156.7)">SUBSTRATE</text>
<text x="78.2" y="158.2" transform="rotate(-180 78.2 158.2)">Z</text>
<text x="95.4" y="157.5" transform="rotate(-90 95.4 157.5)">S</text>
<text x="95.4" y="160.7" transform="rotate(-90 95.4 160.7)">eee</text>
<text x="63.8" y="166.2" transform="rotate(-90 63.8 166.2)">MOLD</text>
<text x="65.6" y="165.5" transform="rotate(-90 65.6 165.5)">CAP</text>
<text x="74.4" y="165.3" transform="rotate(-90 74.4 165.3)">H2</text>
<text x="82" y="166.6" transform="rotate(-90 82 166.6)">DETAIL B</text>
<text x="114.3" y="167.3" transform="rotate(-90 114.3 167.3)">DETAIL A</text>
<text x="81.3" y="169.3" transform="rotate(-180 81.3 169.3)">bbb Z</text>
<text x="92.5" y="176" transform="rotate(-90 92.5 176)">0.630 ±0.025 SQ. 143x</text>
<text x="40.2" y="181.8" transform="rotate(-90 40.2 181.8)">aaa Z</text>
<text x="69.8" y="187.9" transform="rotate(-90 69.8 187.9)">D</text>
<text x="97.9" y="187.9" transform="rotate(-90 97.9 187.9)">X</text>
<text x="100.7" y="189.2" transform="rotate(-90 100.7 189.2)">Y</text>
<text x="125.5" y="188.1" transform="rotate(-90 125.5 188.1)">6.9850</text>
<text x="130.1" y="188.1" transform="rotate(-90 130.1 188.1)">5.7150</text>
<text x="134.6" y="188.1" transform="rotate(-90 134.6 188.1)">4.4450</text>
<text x="139.2" y="188.1" transform="rotate(-90 139.2 188.1)">3.1750</text>
<text x="143.8" y="188.1" transform="rotate(-90 143.8 188.1)">1.9050</text>
<text x="148.3" y="188.1" transform="rotate(-90 148.3 188.1)">0.6350</text>
<text x="150.6" y="186.4" transform="rotate(-90 150.6 186.4)">0.0000</text>
<text x="152.9" y="188.1" transform="rotate(-90 152.9 188.1)">0.6350</text>
<text x="157.5" y="188.1" transform="rotate(-90 157.5 188.1)">1.9050</text>
<text x="162.1" y="188.1" transform="rotate(-90 162.1 188.1)">3.1750</text>
<text x="166.6" y="188.1" transform="rotate(-90 166.6 188.1)">4.4450</text>
<text x="171.2" y="188.1" transform="rotate(-90 171.2 188.1)">5.7150</text>
<text x="175.8" y="188.1" transform="rotate(-90 175.8 188.1)">6.9850</text>
<text x="120.1" y="192.2" transform="rotate(-180 120.1 192.2)">6.9850</text>
<text x="120.1" y="196.8" transform="rotate(-180 120.1 196.8)">5.7150</text>
<text x="120.1" y="201.4" transform="rotate(-180 120.1 201.4)">4.4450</text>
<text x="120.1" y="206" transform="rotate(-180 120.1 206)">3.1750</text>
<text x="120.1" y="210.6" transform="rotate(-180 120.1 210.6)">1.9050</text>
<text x="120.1" y="215.2" transform="rotate(-180 120.1 215.2)">0.6350</text>
<text x="100.7" y="218.4" transform="rotate(-90 100.7 218.4)">E</text>
<text x="118.7" y="217.5" transform="rotate(-180 118.7 217.5)">0.0000</text>
<text x="120.1" y="219.9" transform="rotate(-180 120.1 219.9)">0.6350</text>
<text x="120.1" y="224.5" transform="rotate(-180 120.1 224.5)">1.9050</text>
<text x="120.1" y="233.7" transform="rotate(-180 120.1 233.7)">4.4450</text>
<text x="120.1" y="229.1" transform="rotate(-180 120.1 229.1)">3.1750</text>
<text x="120.1" y="238.3" transform="rotate(-180 120.1 238.3)">5.7150</text>
<text x="105.9" y="245.9" transform="rotate(-180 105.9 245.9)">aaa Z</text>
<text x="120.1" y="242.9" transform="rotate(-180 120.1 242.9)">6.9850</text>
<text x="93.2" y="257.6" transform="rotate(-90 93.2 257.6)">PIN “A1”</text>
<text x="95.1" y="257.6" transform="rotate(-90 95.1 257.6)">CORNER</text>
<text x="97.9" y="255" transform="rotate(-90 97.9 255)">4</text>
</g>
<text font-size="1.2" fill="#231f20" x="191.3" y="58.8" transform="rotate(-90 191.3 58.8)">LGA 144 1112 REV C</text>
</g></defs>
<g fill="#900126">
<path d="M185.5 266.8h.5v4.1h1.6v.5h-2.1z"/>
<path d="M176.2 267.4a2.28 2.28 0 0 1 1.5-.5 5.1 5.1 0 0 0-1.5 4 2.58 2.58 0 0 0 3.1 1.3l-.5 .8h-6.9a4.2 4.2 0 0 0 2.7-2.9 5.1 5.1 0 0 1 1.6-2.7z"/>
<path d="M178.1 266.9h7a4.2 4.2 0 0 0-2.8 2.8 4.1 4.1 0 0 1-2.5 3.3h-.5a5.1 5.1 0 0 0 1.5-4.1 2.58 2.58 0 0 0-3.1-1.2z"/>
<path d="M188 266.8h.5v4.6h-.5z"/>
<path d="M188.9 266.8a2.92 2.92 0 0 1 2.1 .9v-.9h.5v4.6h-.5v-3.1l-.9-.6-.7-.3v4h-.5z"/>
<path d="M185.5 271.6h1.3v.1h-.6v1.3h-.1v-1.3h-.6z"/>
<path d="M187 271.6h1.2v.1h-1v.5h.9v.2h-.9v.5h1v.1h-1.2z"/>
<path d="M190 271.6h.2v.6h1v-.6h.1v1.4h-.1v-.6h-1v.6h-.2z"/>
<path d="M191.6 271.6h.1l1 1.2v-1.2h.1v1.4h-.1l-1-1.2v1.2h-.1z"/>
<path d="M194.7 271.6h.1v1.3h.9v.1h-1z"/>
<path d="M198.6 271.6h.2l.5 .7 .5-.7h.2l-.6 .8v.6h-.2v-.6z"/>
<path d="M192.1 266.8h2.2v.5h-1.7v.7h1.7v.5h-1.7v1.1a1.32 1.32 0 0 0 1.7 1.3v.5l1.2-4.6h.8l1.1 4.1v-4.1a1.84 1.84 0 0 1 2.2 1 1.84 1.84 0 0 1-.6 2.3l-.7 .3 .8 .4 .9 .1v.5a3.2 3.2 0 0 1-2.2-.8v-.6a1.34 1.34 0 0 0 1.5-1.2 1.34 1.34 0 0 0-1.4-1.5v4.1h-.9l-.8-2.9h-1.3v-.5h1.2l-.2-.7-1.1 4.1a2.25 2.25 0 0 1-2.5-.9l-.2-.9v-1.1h-.4v-.5h.4z"/>
<path d="M193.2 271.8a.72 .72 0 0 1 1.2 .1 .72 .72 0 0 1-.4 1.1 .72 .72 0 0 1-1-.7h.2a.59 .59 0 0 0 .8 .5 .59 .59 0 0 0 .2-.9 .59 .59 0 0 0-1 .2v.2h-.2z"/>
<path d="M195.9 271.8a.72 .72 0 0 1 1.1 .1 .72 .72 0 0 1-.4 1.1 .72 .72 0 0 1-.9-.7h.1a.59 .59 0 0 0 .8 .5 .59 .59 0 0 0 .2-.9 .59 .59 0 0 0-.9 .2l-.1 .2h-.1z"/>
<path d="M197.5 271.8a.72 .72 0 0 1 1.2 .2h-.2a.59 .59 0 0 0-.9-.1 .59 .59 0 0 0 .1 .9 .59 .59 0 0 0 .9-.4h-.5v-.1h.6v.7h-.1v-.3a.73 .73 0 0 1-1.1 .2 .73 .73 0 0 1 0-1.1z"/>
<path d="M188.6 271.8a.71 .71 0 0 1 1.2 .3h-.1a.59 .59 0 0 0-.9-.3 .59 .59 0 0 0-.1 1 .59 .59 0 0 0 1-.3h.1a.73 .73 0 0 1-1.1 .4 .73 .73 0 0 1-.1-1.1z"/>
</g>
<path d="M15.9 24.4h184.1M15.9 263h184.1" fill="none" stroke="#231f20" stroke-width="1.2" stroke-linecap="butt"/>
<path d="M74.1 224.1h21.3v21.6h-21.3z" fill="#d1d2d4"/>
<path d="M39.9 81.6h56.2M68.1 110.5v-57.9" fill="none" stroke="#231f20" stroke-width=".16" stroke-dasharray="1.2 .4 2.7 .4" stroke-linecap="butt"/>
<path d="M122 107.3v7l-3.5-3.5zM126.4 107.3v7l-3.5-3.5zM100.1 191.3v25.1M100.1 219.5v25.4" fill="none" stroke="#231f20" stroke-width=".16"/>
<g fill="#231f20">
<path d="M99.7 244.2l.4 .2 .3-.2-.3 1.3z"/>
<path d="M100.1 191l.3 1.3-.3-.3-.4 .3z"/>
</g>
<path d="M93.6 246.2v5.3" fill="none" stroke="#231f20" stroke-width=".16"/>
<path d="M93.6 245.9l.4 1.3-.4-.2-.3 .2z" fill="#231f20"/>
<path d="M40.5 185.3v4.6M41.5 187.4h26" fill="none" stroke="#231f20" stroke-width=".16"/>
<path d="M40.6 187.4l1.3-.3-.2 .3 .2 .4z" fill="#231f20"/>
<path d="M71.1 187.4h23.3" fill="none" stroke="#231f20" stroke-width=".16"/>
<path d="M94.1 187.1l1.3 .3-1.3 .4 .2-.4z" fill="#231f20"/>
<g fill="none" stroke="#231f20" stroke-width=".16">
<path d="M159.1 59.2l.4 .4M159.1 59.2h-4.6v.4h5M159.1 58.8v.4M159.5 58.8v.8M160 58.8v.8M160 59.6h1.7M160.4 58.8v.4M160.4 59.2h1M160.4 59.2l-.4 .4M161.4 58.8v.4M161.4 59.2l.3 .4M161.7 58.8v.8"/>
<path d="M162.3 58.8v.8M162.3 59.6h18.6M162.7 58.8v.4M162.7 59.2h17.8M162.7 59.2l-.4 .4M180.5 58.8v.4M180.5 59.2l.4 .4M180.9 58.8v.8M181.5 58.8v.8M181.5 59.6h1.8M181.9 59.2l-.4 .4M181.9 58.8v.4"/>
<path d="M181.9 59.2h1.1M183 58.8v.4M183 59.2l.3 .4M183.3 59.6v.6l-.3 .3M183.4 58.8v41.8M184.4 58.8v42.4M184.7 58.8v42.6l-2.2 2.2h-28M184.9 58.8v42.6M187.1 58.8v43.7l-3.5 3.5M156.3 61.7a1.53 1.53 0 0 1 1.6 1.6M156.3 77.1h-1.8v.3h1.9M156.3 77.1l.1 .3"/>
<path d="M156.4 61.5v.2M156.4 61.5a1.75 1.75 0 0 1 1.7 1.8M156.4 61.5h-1.9v.2h1.8M157.9 75.6a1.53 1.53 0 0 1-1.6 1.5M157.9 63.3v12.3M157.9 75.6h.2M157.9 63.3h.2M158.1 75.6a1.75 1.75 0 0 1-1.7 1.8M158.1 63.3v12.3M159.1 78.4l.4 .3M159.1 78.4h-4.6v.3h5M159.1 60.5v17.9"/>
<path d="M159.1 79.7v.7M159.5 60.2v18.5M159.5 79.3v1.5M159.5 79.3l-.4 .4M159.5 60.2l-.4 .3M159.5 60.2h-5v.3h4.6M159.5 79.3h-5v.4h4.6M160 79.3l.4 .4M160 79.3v1.5M160 60.2v18.5M160 60.2h1.7M160 78.7h1.7"/>
<path d="M160 79.3h1.7M160 60.2l.4 .3M160.4 78.4l-.4 .3M160.4 60.5v17.9M160.4 60.5h1M160.4 78.4h1M160.4 79.7h1M160.4 79.7v.7M161.4 79.7v.7M161.4 78.4l.3 .3M161.4 60.5v17.9M161.7 60.2v18.5"/>
<path d="M161.7 60.2l-.3 .3M161.7 79.3v1.5M161.7 79.3l-.3 .4M162.3 79.3l.4 .4M162.3 60.2v18.5M162.3 60.2l.4 .3M162.3 79.3v1.5M162.3 60.2h18.6M162.3 78.7h18.6M162.3 79.3h18.6M162.7 79.7v.7M162.7 78.4l-.4 .3"/>
<path d="M162.7 60.5v17.9M162.7 60.5h17.8M162.7 78.4h17.8M162.7 79.7h17.8M163.7 75.6a1.75 1.75 0 0 0 1.7 1.8v-.3M163.7 75.6a1.75 1.75 0 0 0 1.7 1.8h12.4M163.7 75.6h.2M163.9 75.6a1.53 1.53 0 0 0 1.5 1.5M163.9 63.3v12.3M165.4 61.5a1.74 1.74 0 0 0-1.7 1.8h.2M165.4 61.5a1.74 1.74 0 0 0-1.7 1.8v12.3M165.4 61.7a1.53 1.53 0 0 0-1.5 1.6"/>
<path d="M165.4 61.5h12.4M165.4 61.7h12.4M165.4 61.5v.2M165.4 77.1h12.4M177.8 61.5a1.78 1.78 0 0 1 1.8 1.8M177.8 61.7a1.52 1.52 0 0 1 1.5 1.6M177.8 61.5a1.76 1.76 0 0 1 1.8 1.8M177.8 61.5v.2M177.8 77.1v.3M179.3 75.6a1.5 1.5 0 0 1-1.5 1.5M179.3 63.3h.3M179.3 75.6h.3"/>
<path d="M179.3 63.3v12.3M179.6 75.6a1.77 1.77 0 0 1-1.8 1.8M179.6 63.3v12.3M180.5 79.7v.7M180.5 78.4l.4 .3M180.5 60.5v17.9M180.9 79.3v1.5M180.9 79.3l-.4 .4M180.9 60.2l-.4 .3M180.9 60.2v18.5M181.5 79.3l.4 .4M181.5 60.2l.4 .3h1.1"/>
<path d="M181.5 60.2v18.5M181.5 60.2h1.8M181.5 78.7h1.8M181.5 79.3h1.8M181.5 79.3v1.5M181.9 79.7h1.1M181.9 79.7v.7M181.9 78.4l-.4 .3M181.9 60.5v17.9M181.9 78.4h1.1M183 60.5v17.9M183 78.4l.3 .3"/>
<path d="M183 79.7v.7M183.3 78.7v.6M183.3 79.3l-.3 .4M156.3 83a1.51 1.51 0 0 1 1.6 1.5M156.4 82.7a1.74 1.74 0 0 1 1.7 1.8h-.2M156.4 82.7a1.74 1.74 0 0 1 1.7 1.8v12.3M156.4 82.7h-1.9v.3h1.8M156.4 82.7v.3M157.9 96.8a1.53 1.53 0 0 1-1.6 1.5M157.9 84.5v12.3M157.9 96.8h.2M158.1 96.8a1.75 1.75 0 0 1-1.7 1.8h-1.9v-.3h1.8"/>
<path d="M158.1 96.8a1.75 1.75 0 0 1-1.7 1.8l-.1-.3M159.1 80.4h-4.6v.4h5M159.1 99.6h-4.6v.3h5M159.1 81.7v17.9M159.1 80.4l.4 .4M159.1 99.6l.4 .3M159.5 81.4l-.4 .3M159.5 81.4h-5v.3h4.6M159.5 81.4v18.5M160 81.4v18.5M160 80.8h1.7M160 81.4h1.7"/>
<path d="M160 99.9h1.7M160 81.4l.4 .3M160.4 80.4h1M160.4 99.6h1M160.4 81.7h1M160.4 99.6l-.4 .3M160.4 80.4l-.4 .4M160.4 81.7v17.9M161.4 80.4l.3 .4M161.4 81.7v17.9M161.4 99.6l.3 .3M161.7 81.4v18.5"/>
<path d="M161.7 81.4l-.3 .3M162.3 81.4v18.5M162.3 81.4l.4 .3M162.3 80.8h18.6M162.3 81.4h18.6M162.3 99.9h18.6M162.7 99.6l-.4 .3M162.7 80.4l-.4 .4M162.7 81.7v17.9M162.7 80.4h17.8M162.7 99.6h17.8M162.7 81.7h17.8"/>
<path d="M180.5 80.4l.4 .4M180.5 81.7v17.9M180.5 99.6l.4 .3M180.9 81.4v18.5M180.9 81.4l-.4 .3M181.5 81.4l.4 .3h1.1M181.5 81.4v18.5M181.5 80.8h1.8M181.5 81.4h1.8M181.5 99.9h1.8M181.9 80.4l-.4 .4M181.9 80.4h1.1"/>
<path d="M181.9 81.7v17.9M181.9 99.6l-.4 .3M181.9 99.6h1.1M183 80.4l.3 .4M183 81.7v17.9M183 99.6l.3 .3M183.3 80.8v.6l-.3 .3M183.3 99.9v.7M100.9 116.7l2.7-2.6v5.2zM154.5 109.3h7.9M154.5 104.8h8.2v4.8M154.5 109.6h8.2"/>
<path d="M154.5 100.5h5M154.5 100.9h4.6M154.5 102.2h27.2M154.5 103.3h27.8M154.5 103.8h28M159.1 101.8h-4.6v.3M159.1 101.8l.4 .3M159.1 100.9v.9M159.5 102.1h.5M159.5 100.5v1.6M159.5 100.5l-.4 .4M160 100.5v1.6"/>
<path d="M160 100.5h1.7M160 100.5l.4 .4M160.4 100.9h1M160.4 101.8h1M160.4 100.9v.9M160.4 101.8l-.4 .3M161.4 100.9v.9M161.4 101.8l.3 .3M161.7 100.5v1.6M161.7 102.1h.6M161.7 100.5l-.3 .4M162.3 100.5v1.6"/>
<path d="M162.3 100.5l.4 .4M162.3 100.5h18.6M162.4 104.8v4.5l.3 .3M162.7 100.9v.9M162.7 101.8l-.4 .3M162.7 100.9h17.8M162.7 101.8h17.8M180.5 100.9v.9M180.5 101.8l.4 .3M180.9 100.5v1.6M180.9 102.1h.8M180.9 100.5l-.4 .4"/>
<path d="M181.7 102.1v.1M182.3 103.3l.2 .5M183.3 100.6l-1.6 1.5M183.3 100.6h.1M183.4 100.6l-1.7 1.6M183.6 106h-17.4a4.4 4.4 0 0 1-.7 3.4 3.1 3.1 0 0 1-2.3 1.1h-8.7M184.4 101.2l-2.1 2.1M184.4 101.2l.5 .2-2.4 2.4M38.7 179.2h1.8M38.7 177.5h1.8v7.8h-1.8zM38.7 182.3h1.8M39.5 183l.6-.2v2.1a1.07 1.07 0 0 1-1-.7 1.07 1.07 0 0 1 .4-1.2z"/>
<path d="M95.5 187.4h.8M95.5 185.3v4.6M96.3 186.4h2v2.1h-2zM96.4 190.8h5.2M99 187.8h2.1v2h-2.1zM100.1 189.8v.9M95.7 254.5l2.7-2.6v5.2zM96.4 245.7h5.2M101.6 245.7h7.7v1.8h-7.7zM103.2 245.7v1.8M106.3 245.7v1.8M106.8 246.1h2.1a1.07 1.07 0 0 1-1 1 1.07 1.07 0 0 1-1.1-1z"/>
</g>
<path d="M40.6 54h55v55.1h-55z" fill="none" stroke="#231f20" stroke-width=".35"/>
<path d="M163.2 82.2h16.8v16.9h-16.8z" fill="none" stroke="#231f20" stroke-width=".59"/>
<g fill="#231f20">
<path d="M167.8 83.4l.5 .4h.3h-.3l-.5 .4 .4-.4z"/>
<path d="M165.3 90.8h2.1v-.9h.3v1.1h-2.4z"/>
<path d="M165.3 95.1a2.57 2.57 0 0 0 2 .9 .99 .99 0 0 0 .8-1v-.7l.5 .2v3.7a2.76 2.76 0 0 0-2.2-1.7 1.62 1.62 0 0 1-1.1-1.4z"/>
<path d="M165.3 91.2a2.76 2.76 0 0 0 2.2 1.7 1.62 1.62 0 0 1 1.1 1.4 2.58 2.58 0 0 0-2-.8 .99 .99 0 0 0-.8 .9v.7l-.5-.2z"/>
</g>
<path d="M165.3 89.6h2.4" fill="none" stroke="#231f20" stroke-width=".26"/>
<g fill="#231f20">
<path d="M165.3 87.9h2.4v.3h-1.6l-.5 .8h2.1v.3h-2.4l.1-.4 .4-.7h-.5z"/>
<path d="M167.8 90.4l.1 .3h.7h-.7l-.1 .4z"/>
<path d="M167.8 89.6l.1 .6h.2v-.5l.1 .5h.3l.1-.6v.6h-.8z"/>
<path d="M167.8 88h.8l-.4 .1v.5l.4 .1h-.8l.3-.1v-.5z"/>
<path d="M167.8 87.2h.8l-.7 .6 .7 .1h-.8l.7-.6z"/>
<path d="M167.8 86.2h.7l.1-.5v.5z"/>
<path d="M165.6 83.8a.94 .94 0 0 1 1.6 .5l.2-.9h.3l-.1 .6-.3 .6h-.3a.78 .78 0 0 0-.8-.8l-.3 .1-.2 .2-.1 .4h2.1v.5l-1.5 .4v.7h-.3v-.6l-.3 .1 2.1 .6a1.14 1.14 0 0 1-.3 1.2 1.14 1.14 0 0 1-1.2 .2v.2h-.3v-.2h-.6v-1.2h.3v.9h.3v-.9h.3v.9h.6a.69 .69 0 0 0 .6-.9h.3l-2.4-.6v-.4l2.2-.6h-2.2l.1-.7z"/>
<path d="M167.9 86.5a.38 .38 0 0 1 .6 0 .38 .38 0 0 1-.3 .6 .34 .34 0 0 0 .3-.4 .34 .34 0 0 0-.5-.3 .36 .36 0 0 0-.1 .4 .36 .36 0 0 0 .3 .3 .37 .37 0 0 1-.3-.6z"/>
<path d="M167.9 85.1a.38 .38 0 0 1 .6 0 .38 .38 0 0 1-.3 .6 .34 .34 0 0 0 .3-.4 .34 .34 0 0 0-.5-.2 .36 .36 0 0 0-.1 .3 .36 .36 0 0 0 .3 .3 .37 .37 0 0 1-.3-.6z"/>
<path d="M167.9 84.2l.1-.1a.34 .34 0 0 0-.1 .6 .34 .34 0 0 0 .6-.1 .3 .3 0 0 0-.2-.4l-.1 .2v-.3h.4l-.2 .1a.38 .38 0 0 1 .1 .5 .38 .38 0 0 1-.6 .1 .38 .38 0 0 1 0-.6z"/>
<path d="M167.9 88.9l.2-.1-.2 .3a.31 .31 0 0 0 .5 .3 .31 .31 0 0 0-.1-.5v-.1a.38 .38 0 0 1 .2 .5 .38 .38 0 0 1-.6 .1 .38 .38 0 0 1 0-.5z"/>
</g>
<path d="M186.2 105.3l1.7 2.4" fill="none" stroke="#231f20" stroke-width=".16"/>
<path d="M185.6 104.4l1.3 1.1h-.6l-.2 .5z" fill="#231f20"/>
<path d="M178.6 99.7v8.1" fill="none" stroke="#fff" stroke-width=".88" stroke-linecap="butt"/>
<path d="M178.6 98.5l.4 1.4-.4-.2-.4 .2z" fill="#fff"/>
<path d="M178.6 98.5l.4 1.4-.4-.2-.4 .2z" fill="none" stroke="#fff" stroke-width=".88" stroke-linecap="butt"/>
<path d="M178.6 98.5l.4 1.4-.4-.2-.4 .2z" fill="#231f20"/>
<path d="M95.3 56.3h7.8M178.6 99.7v8.1M95.1 108.5l3.5 3.6M95.1 106.8h8" fill="none" stroke="#231f20" stroke-width=".16"/>
<path d="M94.4 107.8l1.2 .7-.4 .1-.1 .4z" fill="#231f20"/>
<path d="M69.6 118.2h22.7M93.3 108.5v11.1" fill="none" stroke="#231f20" stroke-width=".16"/>
<path d="M91.9 117.8l1.3 .4-1.3 .3 .2-.3z" fill="#231f20"/>
<path d="M98.8 80.2v1.5" fill="none" stroke="#231f20" stroke-width=".16"/>
<path d="M98.8 79.3l.4 1.3-.4-.2-.3 .2z" fill="#231f20"/>
<path d="M98.8 72v1.5" fill="none" stroke="#231f20" stroke-width=".16"/>
<path d="M98.5 73.1l.3 .2 .4-.2-.4 1.3z" fill="#231f20"/>
<path d="M102.1 57.3v22.6" fill="none" stroke="#231f20" stroke-width=".16"/>
<path d="M102.1 56.4l.4 1.3-.4-.3-.3 .3z" fill="#231f20"/>
<path d="M102.1 82.7v23" fill="none" stroke="#231f20" stroke-width=".16"/>
<path d="M101.8 105.3l.3 .2 .4-.2-.4 1.3z" fill="#231f20"/>
<path d="M98.8 104.3v1.4" fill="none" stroke="#231f20" stroke-width=".16"/>
<path d="M98.8 103.4l.4 1.3-.4-.2-.3 .2z" fill="#231f20"/>
<path d="M98.8 98.6v1.3" fill="none" stroke="#231f20" stroke-width=".16"/>
<path d="M98.5 99.5l.3 .2 .4-.2-.4 1.3z" fill="#231f20"/>
<path d="M43.8 118.2h22.7" fill="none" stroke="#231f20" stroke-width=".16"/>
<path d="M42.8 118.2l1.3-.4-.2 .4 .2 .3z" fill="#231f20"/>
<path d="M95.1 79.1h4.6M95.1 74.6h4.6M42.8 108.4v11.2M44 115.2h1.3M94.8 103.3h4.9M94.8 101h4.9" fill="none" stroke="#231f20" stroke-width=".16"/>
<path d="M44.9 114.9l1.3 .3-1.3 .4 .2-.4z" fill="#231f20"/>
<path d="M49.8 115.2h1.3" fill="none" stroke="#231f20" stroke-width=".16"/>
<path d="M48.9 115.2l1.3-.4-.3 .4 .3 .4z" fill="#231f20"/>
<path d="M46.4 108.3v7.7M48.6 108.3v7.7M85.4 115.2h2.3M68.3 186.6h1.9v1.7h-1.9z" fill="none" stroke="#231f20" stroke-width=".16"/>
<path d="M150.1 187.1v62.1M179.5 218.2h-60.3" fill="none" stroke="#231f20" stroke-width=".16" stroke-dasharray="1.2 .4 2.7 .4" stroke-linecap="butt"/>
<path d="M87.3 114.8l1.3 .4-1.3 .4 .2-.4z" fill="#231f20"/>
<path d="M94.4 115.2h2.2" fill="none" stroke="#231f20" stroke-width=".16"/>
<path d="M93.5 115.2l1.3-.4-.2 .4 .2 .3z" fill="#231f20"/>
<path d="M88.7 108.5v7.6" fill="none" stroke="#231f20" stroke-width=".16"/>
<circle cx="178.6" cy="97.6" r=".63" fill="#231f20"/>
<g fill="none" stroke="#231f20" stroke-width=".16">
<path d="M97.9 76h1.8v1.7h-1.8zM101.3 80.4h1.8v1.7h-1.8zM46.6 114.4h1.8v1.6h-1.8zM67.2 117.3h1.8v1.7h-1.8zM90.1 114.4h1.8v1.6h-1.8zM97.9 101.3h1.8v1.7h-1.8zM120.5 197.4h2.6M120.5 192.8h2.6M124.9 188.6v2.6M129.4 188.6v2.6M134 188.6v2.6M138.6 188.6v2.6"/>
<path d="M143.2 188.6v2.6M147.7 188.6v2.6M152.3 188.6v2.6M156.9 188.6v2.6M161.5 188.6v2.6M166 188.6v2.6M170.6 188.6v2.6M175.2 188.6v2.6M99.2 217.2h1.8v1.6h-1.8zM120.5 215.9h2.6M120.5 211.2h2.6M120.5 206.6h2.6"/>
<path d="M120.5 202h2.6M120.5 238.9h2.6M120.5 234.3h2.6M120.5 229.7h2.6M120.5 225.1h2.6M120.5 220.5h2.6M120.5 243.5h2.6"/>
</g>
<path d="M188.2 58.8h-33.7M154.5 112v-53.2" fill="none" stroke="#231f20" stroke-width=".16" stroke-dasharray="5 .9 1 .9 1 .9"/>
<path d="M40.7 130.6h54.9v11.1h-54.9zM40.5 190.7h55v55h-55z" fill="none" stroke="#231f20" stroke-width=".35"/>
<path d="M40.7 130.6h54.8v.6h-54.8z" fill="#231f20"/>
<g fill="none" stroke="#231f20" stroke-width=".16">
<path d="M123.9 127.2v47.3M127.3 127.2v47.3M127.3 136.6h41.1M130.7 127.2v47.3M133.7 127.2v47.3M136.8 127.2v47.3M140 127.2v47.3M143.1 127.2v47.3M146.3 127.2v47.3M149.4 127.2v47.3M152.6 127.2v47.3M155.7 127.2v47.3"/>
<path d="M158.9 127.2v47.3M162.1 127.2v47.3M165.2 127.2v47.3M168.4 127.2v47.3M171.6 127.2v47.3M127.3 155.5h9.5M127.3 146.1h9.5M152.6 155.5h15.8M152.6 146.1h15.8M70.8 169.1h7.1M76.9 169.1h7.7v1.8h-7.7zM78.6 169.1v1.8"/>
<path d="M81.7 169.1v1.8M82.1 169.5h2.2a1.07 1.07 0 0 1-1.1 1 1.07 1.07 0 0 1-1.1-1zM127.3 164.9h41.1"/>
<circle cx="91.9" cy="136.7" r="8.9"/>
</g>
<path d="M53.5 157.9h16.7v1.8h-15.9z" fill="#d1d2d4"/>
<path d="M53.5 157.8h16.7v11.3h-11.6" fill="none" stroke="#231f20" stroke-width=".35"/>
<path d="M52 154.6l7.8 17M70.8 159.6h3.4M70.8 157.9h7.2M71.9 160.6v2" fill="none" stroke="#231f20" stroke-width=".16"/>
<path d="M71.9 159.7l.3 1.3-.3-.2-.4 .2z" fill="#231f20"/>
<path d="M71.9 154.9v2" fill="none" stroke="#231f20" stroke-width=".16"/>
<path d="M71.5 156.6l.4 .2 .3-.2-.3 1.3z" fill="#231f20"/>
<path d="M76.9 158h1.7v1.8h-1.7zM73.8 160.6v2.2M73.8 165.9v2.2" fill="none" stroke="#231f20" stroke-width=".16"/>
<g fill="#231f20">
<path d="M73.8 159.7l.3 1.3-.3-.2-.4 .2z"/>
<path d="M73.4 167.7l.4 .3 .3-.3-.3 1.3z"/>
</g>
<path d="M38.8 131.7v3.1M38.8 137.3v3.4M71 152.2h1.8v2.2h-1.8zM72.9 163.2h1.8v2.3h-1.8z" fill="none" stroke="#231f20" stroke-width=".16"/>
<g fill="#231f20">
<path d="M38.8 130.7l.4 1.3-.4-.2-.3 .2z"/>
<path d="M38.5 140.3l.3 .2 .4-.2-.4 1.3z"/>
</g>
<path d="M37.8 130.6h2.2M37.9 135.3h1.8v1.6h-1.8zM37.8 141.7h2.2" fill="none" stroke="#231f20" stroke-width=".16"/>
<path d="M169.5 191.7h2.2v2.3h-2.2z" fill="#231f20"/>
<path d="M169.5 191.7h2.2v2.3h-2.2z" fill="none" stroke="#231f20" stroke-width=".16"/>
<path d="M128.2 191.7h2.3v2.2h-2.3z" fill="#231f20"/>
<path d="M128.2 191.7h2.3v2.2h-2.3z" fill="none" stroke="#231f20" stroke-width=".16"/>
<path d="M132.8 191.7h2.3v2.2h-2.3z" fill="#231f20"/>
<path d="M132.8 191.7h2.3v2.2h-2.3z" fill="none" stroke="#231f20" stroke-width=".16"/>
<path d="M137.4 191.7h2.3v2.2h-2.3z" fill="#231f20"/>
<path d="M137.4 191.7h2.3v2.2h-2.3z" fill="none" stroke="#231f20" stroke-width=".16"/>
<path d="M142 191.7h2.2v2.2h-2.2z" fill="#231f20"/>
<path d="M142 191.7h2.2v2.2h-2.2z" fill="none" stroke="#231f20" stroke-width=".16"/>
<path d="M146.6 191.7h2.2v2.2h-2.2z" fill="#231f20"/>
<path d="M146.6 191.7h2.2v2.2h-2.2z" fill="none" stroke="#231f20" stroke-width=".16"/>
<path d="M151.1 191.7h2.3v2.2h-2.3z" fill="#231f20"/>
<path d="M151.1 191.7h2.3v2.2h-2.3z" fill="none" stroke="#231f20" stroke-width=".16"/>
<path d="M155.7 191.7h2.3v2.2h-2.3z" fill="#231f20"/>
<path d="M155.7 191.7h2.3v2.2h-2.3z" fill="none" stroke="#231f20" stroke-width=".16"/>
<path d="M160.3 191.7h2.3v2.2h-2.3z" fill="#231f20"/>
<path d="M160.3 191.7h2.3v2.2h-2.3z" fill="none" stroke="#231f20" stroke-width=".16"/>
<path d="M164.9 191.7h2.2v2.2h-2.2z" fill="#231f20"/>
<path d="M164.9 191.7h2.2v2.2h-2.2z" fill="none" stroke="#231f20" stroke-width=".16"/>
<path d="M169.5 196.3h2.2v2.3h-2.2z" fill="#231f20"/>
<path d="M169.5 196.3h2.2v2.3h-2.2z" fill="none" stroke="#231f20" stroke-width=".16"/>
<path d="M174 196.3h2.3v2.3h-2.3z" fill="#231f20"/>
<path d="M174 196.3h2.3v2.3h-2.3z" fill="none" stroke="#231f20" stroke-width=".16"/>
<path d="M123.6 196.3h2.3v2.2h-2.3z" fill="#231f20"/>
<path d="M123.6 196.3h2.3v2.2h-2.3z" fill="none" stroke="#231f20" stroke-width=".16"/>
<path d="M128.2 196.3h2.3v2.2h-2.3z" fill="#231f20"/>
<path d="M128.2 196.3h2.3v2.2h-2.3z" fill="none" stroke="#231f20" stroke-width=".16"/>
<path d="M132.8 196.3h2.3v2.2h-2.3z" fill="#231f20"/>
<path d="M132.8 196.3h2.3v2.2h-2.3z" fill="none" stroke="#231f20" stroke-width=".16"/>
<path d="M137.4 196.3h2.3v2.2h-2.3z" fill="#231f20"/>
<path d="M137.4 196.3h2.3v2.2h-2.3z" fill="none" stroke="#231f20" stroke-width=".16"/>
<path d="M142 196.3h2.2v2.2h-2.2z" fill="#231f20"/>
<path d="M142 196.3h2.2v2.2h-2.2z" fill="none" stroke="#231f20" stroke-width=".16"/>
<path d="M146.6 196.3h2.2v2.2h-2.2z" fill="#231f20"/>
<path d="M146.6 196.3h2.2v2.2h-2.2z" fill="none" stroke="#231f20" stroke-width=".16"/>
<path d="M151.1 196.3h2.3v2.2h-2.3z" fill="#231f20"/>
<path d="M151.1 196.3h2.3v2.2h-2.3z" fill="none" stroke="#231f20" stroke-width=".16"/>
<path d="M155.7 196.3h2.3v2.2h-2.3z" fill="#231f20"/>
<path d="M155.7 196.3h2.3v2.2h-2.3z" fill="none" stroke="#231f20" stroke-width=".16"/>
<path d="M160.3 196.3h2.3v2.2h-2.3z" fill="#231f20"/>
<path d="M160.3 196.3h2.3v2.2h-2.3z" fill="none" stroke="#231f20" stroke-width=".16"/>
<path d="M164.9 196.3h2.2v2.2h-2.2z" fill="#231f20"/>
<path d="M164.9 196.3h2.2v2.2h-2.2z" fill="none" stroke="#231f20" stroke-width=".16"/>
<path d="M169.5 200.9h2.2v2.3h-2.2z" fill="#231f20"/>
<path d="M169.5 200.9h2.2v2.3h-2.2z" fill="none" stroke="#231f20" stroke-width=".16"/>
<path d="M174 200.9h2.3v2.3h-2.3z" fill="#231f20"/>
<path d="M174 200.9h2.3v2.3h-2.3z" fill="none" stroke="#231f20" stroke-width=".16"/>
<path d="M123.6 200.9h2.3v2.3h-2.3z" fill="#231f20"/>
<path d="M123.6 200.9h2.3v2.3h-2.3z" fill="none" stroke="#231f20" stroke-width=".16"/>
<path d="M128.2 200.9h2.3v2.3h-2.3z" fill="#231f20"/>
<path d="M128.2 200.9h2.3v2.3h-2.3z" fill="none" stroke="#231f20" stroke-width=".16"/>
<path d="M132.8 200.9h2.3v2.3h-2.3z" fill="#231f20"/>
<path d="M132.8 200.9h2.3v2.3h-2.3z" fill="none" stroke="#231f20" stroke-width=".16"/>
<path d="M137.4 200.9h2.3v2.3h-2.3z" fill="#231f20"/>
<path d="M137.4 200.9h2.3v2.3h-2.3z" fill="none" stroke="#231f20" stroke-width=".16"/>
<path d="M142 200.9h2.2v2.3h-2.2z" fill="#231f20"/>
<path d="M142 200.9h2.2v2.3h-2.2z" fill="none" stroke="#231f20" stroke-width=".16"/>
<path d="M146.6 200.9h2.2v2.3h-2.2z" fill="#231f20"/>
<path d="M146.6 200.9h2.2v2.3h-2.2z" fill="none" stroke="#231f20" stroke-width=".16"/>
<path d="M151.1 200.9h2.3v2.3h-2.3z" fill="#231f20"/>
<path d="M151.1 200.9h2.3v2.3h-2.3z" fill="none" stroke="#231f20" stroke-width=".16"/>
<path d="M155.7 200.9h2.3v2.3h-2.3z" fill="#231f20"/>
<path d="M155.7 200.9h2.3v2.3h-2.3z" fill="none" stroke="#231f20" stroke-width=".16"/>
<path d="M160.3 200.9h2.3v2.3h-2.3z" fill="#231f20"/>
<path d="M160.3 200.9h2.3v2.3h-2.3z" fill="none" stroke="#231f20" stroke-width=".16"/>
<path d="M164.9 200.9h2.2v2.3h-2.2z" fill="#231f20"/>
<path d="M164.9 200.9h2.2v2.3h-2.2z" fill="none" stroke="#231f20" stroke-width=".16"/>
<path d="M169.5 205.6h2.2v2.2h-2.2z" fill="#231f20"/>
<path d="M169.5 205.6h2.2v2.2h-2.2z" fill="none" stroke="#231f20" stroke-width=".16"/>
<path d="M174 205.5h2.3v2.3h-2.3z" fill="#231f20"/>
<path d="M174 205.5h2.3v2.3h-2.3z" fill="none" stroke="#231f20" stroke-width=".16"/>
<path d="M123.6 205.5h2.3v2.3h-2.3z" fill="#231f20"/>
<path d="M123.6 205.5h2.3v2.3h-2.3z" fill="none" stroke="#231f20" stroke-width=".16"/>
<path d="M132.8 205.5h2.3v2.3h-2.3z" fill="#231f20"/>
<path d="M132.8 205.5h2.3v2.3h-2.3z" fill="none" stroke="#231f20" stroke-width=".16"/>
<path d="M137.4 205.5h2.3v2.3h-2.3z" fill="#231f20"/>
<path d="M137.4 205.5h2.3v2.3h-2.3z" fill="none" stroke="#231f20" stroke-width=".16"/>
<path d="M142 205.5h2.2v2.3h-2.2z" fill="#231f20"/>
<path d="M142 205.5h2.2v2.3h-2.2z" fill="none" stroke="#231f20" stroke-width=".16"/>
<path d="M146.6 205.5h2.2v2.3h-2.2z" fill="#231f20"/>
<path d="M146.6 205.5h2.2v2.3h-2.2z" fill="none" stroke="#231f20" stroke-width=".16"/>
<path d="M155.7 205.5h2.3v2.3h-2.3z" fill="#231f20"/>
<path d="M155.7 205.5h2.3v2.3h-2.3z" fill="none" stroke="#231f20" stroke-width=".16"/>
<path d="M160.3 205.5h2.3v2.3h-2.3z" fill="#231f20"/>
<path d="M160.3 205.5h2.3v2.3h-2.3z" fill="none" stroke="#231f20" stroke-width=".16"/>
<path d="M164.9 205.5h2.2v2.3h-2.2z" fill="#231f20"/>
<path d="M164.9 205.5h2.2v2.3h-2.2z" fill="none" stroke="#231f20" stroke-width=".16"/>
<path d="M169.5 210.2h2.2v2.2h-2.2z" fill="#231f20"/>
<path d="M169.5 210.2h2.2v2.2h-2.2z" fill="none" stroke="#231f20" stroke-width=".16"/>
<path d="M174 210.1h2.3v2.3h-2.3z" fill="#231f20"/>
<path d="M174 210.1h2.3v2.3h-2.3z" fill="none" stroke="#231f20" stroke-width=".16"/>
<path d="M123.6 210.1h2.3v2.3h-2.3z" fill="#231f20"/>
<path d="M123.6 210.1h2.3v2.3h-2.3z" fill="none" stroke="#231f20" stroke-width=".16"/>
<path d="M137.4 210.1h2.3v2.3h-2.3z" fill="#231f20"/>
<path d="M137.4 210.1h2.3v2.3h-2.3z" fill="none" stroke="#231f20" stroke-width=".16"/>
<path d="M142 210.1h2.2v2.3h-2.2z" fill="#231f20"/>
<path d="M142 210.1h2.2v2.3h-2.2z" fill="none" stroke="#231f20" stroke-width=".16"/>
<path d="M146.6 210.1h2.2v2.3h-2.2z" fill="#231f20"/>
<path d="M146.6 210.1h2.2v2.3h-2.2z" fill="none" stroke="#231f20" stroke-width=".16"/>
<path d="M155.7 210.1h2.3v2.3h-2.3z" fill="#231f20"/>
<path d="M155.7 210.1h2.3v2.3h-2.3z" fill="none" stroke="#231f20" stroke-width=".16"/>
<path d="M160.3 210.1h2.3v2.3h-2.3z" fill="#231f20"/>
<path d="M160.3 210.1h2.3v2.3h-2.3z" fill="none" stroke="#231f20" stroke-width=".16"/>
<path d="M164.9 210.1h2.2v2.3h-2.2z" fill="#231f20"/>
<path d="M164.9 210.1h2.2v2.3h-2.2z" fill="none" stroke="#231f20" stroke-width=".16"/>
<path d="M169.5 214.8h2.2v2.2h-2.2z" fill="#231f20"/>
<path d="M169.5 214.8h2.2v2.2h-2.2z" fill="none" stroke="#231f20" stroke-width=".16"/>
<path d="M174 214.7h2.3v2.3h-2.3z" fill="#231f20"/>
<path d="M174 214.7h2.3v2.3h-2.3z" fill="none" stroke="#231f20" stroke-width=".16"/>
<path d="M123.6 214.7h2.3v2.3h-2.3z" fill="#231f20"/>
<path d="M123.6 214.7h2.3v2.3h-2.3z" fill="none" stroke="#231f20" stroke-width=".16"/>
<path d="M137.4 214.7h2.3v2.3h-2.3z" fill="#231f20"/>
<path d="M137.4 214.7h2.3v2.3h-2.3z" fill="none" stroke="#231f20" stroke-width=".16"/>
<path d="M142 214.7h2.2v2.3h-2.2z" fill="#231f20"/>
<path d="M142 214.7h2.2v2.3h-2.2z" fill="none" stroke="#231f20" stroke-width=".16"/>
<path d="M146.6 214.7h2.2v2.3h-2.2z" fill="#231f20"/>
<path d="M146.6 214.7h2.2v2.3h-2.2z" fill="none" stroke="#231f20" stroke-width=".16"/>
<path d="M155.7 214.7h2.3v2.3h-2.3z" fill="#231f20"/>
<path d="M155.7 214.7h2.3v2.3h-2.3z" fill="none" stroke="#231f20" stroke-width=".16"/>
<path d="M160.3 214.7h2.3v2.3h-2.3z" fill="#231f20"/>
<path d="M160.3 214.7h2.3v2.3h-2.3z" fill="none" stroke="#231f20" stroke-width=".16"/>
<path d="M164.9 214.7h2.2v2.3h-2.2z" fill="#231f20"/>
<path d="M164.9 214.7h2.2v2.3h-2.2z" fill="none" stroke="#231f20" stroke-width=".16"/>
<path d="M169.5 219.4h2.2v2.2h-2.2z" fill="#231f20"/>
<path d="M169.5 219.4h2.2v2.2h-2.2z" fill="none" stroke="#231f20" stroke-width=".16"/>
<path d="M174 219.3h2.3v2.3h-2.3z" fill="#231f20"/>
<path d="M174 219.3h2.3v2.3h-2.3z" fill="none" stroke="#231f20" stroke-width=".16"/>
<path d="M123.6 219.3h2.3v2.3h-2.3z" fill="#231f20"/>
<path d="M123.6 219.3h2.3v2.3h-2.3z" fill="none" stroke="#231f20" stroke-width=".16"/>
<path d="M128.1 210.1h2.3v2.3h-2.3z" fill="#231f20"/>
<path d="M128.1 210.1h2.3v2.3h-2.3z" fill="none" stroke="#231f20" stroke-width=".16"/>
<path d="M128.1 214.7h2.3v2.3h-2.3z" fill="#231f20"/>
<path d="M128.1 214.7h2.3v2.3h-2.3z" fill="none" stroke="#231f20" stroke-width=".16"/>
<path d="M128.1 219.3h2.3v2.3h-2.3z" fill="#231f20"/>
<path d="M128.1 219.3h2.3v2.3h-2.3z" fill="none" stroke="#231f20" stroke-width=".16"/>
<path d="M137.4 219.3h2.3v2.3h-2.3z" fill="#231f20"/>
<path d="M137.4 219.3h2.3v2.3h-2.3z" fill="none" stroke="#231f20" stroke-width=".16"/>
<path d="M142 219.3h2.2v2.3h-2.2z" fill="#231f20"/>
<path d="M142 219.3h2.2v2.3h-2.2z" fill="none" stroke="#231f20" stroke-width=".16"/>
<path d="M146.6 219.3h2.2v2.3h-2.2z" fill="#231f20"/>
<path d="M146.6 219.3h2.2v2.3h-2.2z" fill="none" stroke="#231f20" stroke-width=".16"/>
<path d="M151.1 205.5h2.3v2.3h-2.3z" fill="#231f20"/>
<path d="M151.1 205.5h2.3v2.3h-2.3z" fill="none" stroke="#231f20" stroke-width=".16"/>
<path d="M151.1 210.1h2.3v2.3h-2.3z" fill="#231f20"/>
<path d="M151.1 210.1h2.3v2.3h-2.3z" fill="none" stroke="#231f20" stroke-width=".16"/>
<path d="M151.1 214.7h2.3v2.3h-2.3z" fill="#231f20"/>
<path d="M151.1 214.7h2.3v2.3h-2.3z" fill="none" stroke="#231f20" stroke-width=".16"/>
<path d="M151.1 219.3h2.3v2.3h-2.3z" fill="#231f20"/>
<path d="M151.1 219.3h2.3v2.3h-2.3z" fill="none" stroke="#231f20" stroke-width=".16"/>
<path d="M155.7 219.3h2.3v2.3h-2.3z" fill="#231f20"/>
<path d="M155.7 219.3h2.3v2.3h-2.3z" fill="none" stroke="#231f20" stroke-width=".16"/>
<path d="M160.3 219.3h2.3v2.3h-2.3z" fill="#231f20"/>
<path d="M160.3 219.3h2.3v2.3h-2.3z" fill="none" stroke="#231f20" stroke-width=".16"/>
<path d="M164.9 219.3h2.2v2.3h-2.2z" fill="#231f20"/>
<path d="M164.9 219.3h2.2v2.3h-2.2z" fill="none" stroke="#231f20" stroke-width=".16"/>
<path d="M169.5 224h2.2v2.2h-2.2z" fill="#231f20"/>
<path d="M169.5 224h2.2v2.2h-2.2z" fill="none" stroke="#231f20" stroke-width=".16"/>
<path d="M174 223.9h2.3v2.3h-2.3z" fill="#231f20"/>
<path d="M174 223.9h2.3v2.3h-2.3z" fill="none" stroke="#231f20" stroke-width=".16"/>
<path d="M123.6 223.9h2.3v2.3h-2.3z" fill="#231f20"/>
<path d="M123.6 223.9h2.3v2.3h-2.3z" fill="none" stroke="#231f20" stroke-width=".16"/>
<path d="M128.1 205.5h2.3v2.3h-2.3z" fill="#231f20"/>
<path d="M128.1 205.5h2.3v2.3h-2.3z" fill="none" stroke="#231f20" stroke-width=".16"/>
<path d="M128.1 223.9h2.3v2.3h-2.3z" fill="#231f20"/>
<path d="M128.1 223.9h2.3v2.3h-2.3z" fill="none" stroke="#231f20" stroke-width=".16"/>
<path d="M132.8 210.1h2.3v2.3h-2.3z" fill="#231f20"/>
<path d="M132.8 210.1h2.3v2.3h-2.3z" fill="none" stroke="#231f20" stroke-width=".16"/>
<path d="M132.8 214.7h2.3v2.3h-2.3z" fill="#231f20"/>
<path d="M132.8 214.7h2.3v2.3h-2.3z" fill="none" stroke="#231f20" stroke-width=".16"/>
<path d="M132.8 219.3h2.3v2.3h-2.3z" fill="#231f20"/>
<path d="M132.8 219.3h2.3v2.3h-2.3z" fill="none" stroke="#231f20" stroke-width=".16"/>
<path d="M132.8 223.9h2.3v2.3h-2.3z" fill="#231f20"/>
<path d="M132.8 223.9h2.3v2.3h-2.3z" fill="none" stroke="#231f20" stroke-width=".16"/>
<path d="M146.6 223.9h2.2v2.3h-2.2z" fill="#231f20"/>
<path d="M146.6 223.9h2.2v2.3h-2.2z" fill="none" stroke="#231f20" stroke-width=".16"/>
<path d="M151.1 223.9h2.3v2.3h-2.3z" fill="#231f20"/>
<path d="M151.1 223.9h2.3v2.3h-2.3z" fill="none" stroke="#231f20" stroke-width=".16"/>
<path d="M155.7 223.9h2.3v2.3h-2.3z" fill="#231f20"/>
<path d="M155.7 223.9h2.3v2.3h-2.3z" fill="none" stroke="#231f20" stroke-width=".16"/>
<path d="M160.3 223.9h2.3v2.3h-2.3z" fill="#231f20"/>
<path d="M160.3 223.9h2.3v2.3h-2.3z" fill="none" stroke="#231f20" stroke-width=".16"/>
<path d="M164.9 223.9h2.2v2.3h-2.2z" fill="#231f20"/>
<path d="M164.9 223.9h2.2v2.3h-2.2z" fill="none" stroke="#231f20" stroke-width=".16"/>
<path d="M169.5 228.6h2.2v2.2h-2.2z" fill="#231f20"/>
<path d="M169.5 228.6h2.2v2.2h-2.2z" fill="none" stroke="#231f20" stroke-width=".16"/>
<path d="M174 228.5h2.3v2.3h-2.3z" fill="#231f20"/>
<path d="M174 228.5h2.3v2.3h-2.3z" fill="none" stroke="#231f20" stroke-width=".16"/>
<path d="M123.6 228.6h2.3v2.2h-2.3z" fill="#231f20"/>
<path d="M123.6 228.6h2.3v2.2h-2.3z" fill="none" stroke="#231f20" stroke-width=".16"/>
<path d="M151.1 228.6h2.3v2.2h-2.3z" fill="#231f20"/>
<path d="M151.1 228.6h2.3v2.2h-2.3z" fill="none" stroke="#231f20" stroke-width=".16"/>
<path d="M155.7 228.6h2.3v2.2h-2.3z" fill="#231f20"/>
<path d="M155.7 228.6h2.3v2.2h-2.3z" fill="none" stroke="#231f20" stroke-width=".16"/>
<path d="M160.3 228.6h2.3v2.2h-2.3z" fill="#231f20"/>
<path d="M160.3 228.6h2.3v2.2h-2.3z" fill="none" stroke="#231f20" stroke-width=".16"/>
<path d="M164.9 228.6h2.2v2.2h-2.2z" fill="#231f20"/>
<path d="M164.9 228.6h2.2v2.2h-2.2z" fill="none" stroke="#231f20" stroke-width=".16"/>
<path d="M169.5 233.2h2.2v2.2h-2.2z" fill="#231f20"/>
<path d="M169.5 233.2h2.2v2.2h-2.2z" fill="none" stroke="#231f20" stroke-width=".16"/>
<path d="M174 233.1h2.3v2.3h-2.3z" fill="#231f20"/>
<path d="M174 233.1h2.3v2.3h-2.3z" fill="none" stroke="#231f20" stroke-width=".16"/>
<path d="M123.6 233.2h2.3v2.2h-2.3z" fill="#231f20"/>
<path d="M123.6 233.2h2.3v2.2h-2.3z" fill="none" stroke="#231f20" stroke-width=".16"/>
<path d="M151.1 233.2h2.3v2.2h-2.3z" fill="#231f20"/>
<path d="M151.1 233.2h2.3v2.2h-2.3z" fill="none" stroke="#231f20" stroke-width=".16"/>
<path d="M155.7 233.2h2.3v2.2h-2.3z" fill="#231f20"/>
<path d="M155.7 233.2h2.3v2.2h-2.3z" fill="none" stroke="#231f20" stroke-width=".16"/>
<path d="M160.3 233.2h2.3v2.2h-2.3z" fill="#231f20"/>
<path d="M160.3 233.2h2.3v2.2h-2.3z" fill="none" stroke="#231f20" stroke-width=".16"/>
<path d="M164.9 233.2h2.2v2.2h-2.2z" fill="#231f20"/>
<path d="M164.9 233.2h2.2v2.2h-2.2z" fill="none" stroke="#231f20" stroke-width=".16"/>
<path d="M169.5 237.8h2.2v2.2h-2.2z" fill="#231f20"/>
<path d="M169.5 237.8h2.2v2.2h-2.2z" fill="none" stroke="#231f20" stroke-width=".16"/>
<path d="M174 237.8h2.3v2.2h-2.3z" fill="#231f20"/>
<path d="M174 237.8h2.3v2.2h-2.3z" fill="none" stroke="#231f20" stroke-width=".16"/>
<path d="M123.6 237.8h2.3v2.2h-2.3z" fill="#231f20"/>
<path d="M123.6 237.8h2.3v2.2h-2.3z" fill="none" stroke="#231f20" stroke-width=".16"/>
<path d="M137.4 223.9h2.2v2.3h-2.2z" fill="#231f20"/>
<path d="M137.4 223.9h2.2v2.3h-2.2z" fill="none" stroke="#231f20" stroke-width=".16"/>
<path d="M137.4 228.6h2.2v2.2h-2.2z" fill="#231f20"/>
<path d="M137.4 228.6h2.2v2.2h-2.2z" fill="none" stroke="#231f20" stroke-width=".16"/>
<path d="M141.9 228.6h2.3v2.2h-2.3z" fill="#231f20"/>
<path d="M141.9 228.6h2.3v2.2h-2.3z" fill="none" stroke="#231f20" stroke-width=".16"/>
<path d="M137.4 233.2h2.2v2.2h-2.2z" fill="#231f20"/>
<path d="M137.4 233.2h2.2v2.2h-2.2z" fill="none" stroke="#231f20" stroke-width=".16"/>
<path d="M137.4 237.8h2.2v2.2h-2.2z" fill="#231f20"/>
<path d="M137.4 237.8h2.2v2.2h-2.2z" fill="none" stroke="#231f20" stroke-width=".16"/>
<path d="M132.8 237.8h2.3v2.2h-2.3z" fill="#231f20"/>
<path d="M132.8 237.8h2.3v2.2h-2.3z" fill="none" stroke="#231f20" stroke-width=".16"/>
<path d="M141.9 223.9h2.3v2.3h-2.3z" fill="#231f20"/>
<path d="M141.9 223.9h2.3v2.3h-2.3z" fill="none" stroke="#231f20" stroke-width=".16"/>
<path d="M141.9 233.2h2.3v2.2h-2.3z" fill="#231f20"/>
<path d="M141.9 233.2h2.3v2.2h-2.3z" fill="none" stroke="#231f20" stroke-width=".16"/>
<path d="M146.5 228.6h2.3v2.2h-2.3z" fill="#231f20"/>
<path d="M146.5 228.6h2.3v2.2h-2.3z" fill="none" stroke="#231f20" stroke-width=".16"/>
<path d="M141.9 237.8h2.3v2.2h-2.3z" fill="#231f20"/>
<path d="M141.9 237.8h2.3v2.2h-2.3z" fill="none" stroke="#231f20" stroke-width=".16"/>
<path d="M128.1 228.6h2.3v2.2h-2.3z" fill="#231f20"/>
<path d="M128.1 228.6h2.3v2.2h-2.3z" fill="none" stroke="#231f20" stroke-width=".16"/>
<path d="M128.1 233.2h2.3v2.2h-2.3z" fill="#231f20"/>
<path d="M128.1 233.2h2.3v2.2h-2.3z" fill="none" stroke="#231f20" stroke-width=".16"/>
<path d="M132.8 228.6h2.3v2.2h-2.3z" fill="#231f20"/>
<path d="M132.8 228.6h2.3v2.2h-2.3z" fill="none" stroke="#231f20" stroke-width=".16"/>
<path d="M132.8 233.2h2.3v2.2h-2.3z" fill="#231f20"/>
<path d="M132.8 233.2h2.3v2.2h-2.3z" fill="none" stroke="#231f20" stroke-width=".16"/>
<path d="M128.1 237.8h2.3v2.2h-2.3z" fill="#231f20"/>
<path d="M128.1 237.8h2.3v2.2h-2.3z" fill="none" stroke="#231f20" stroke-width=".16"/>
<path d="M151.1 237.8h2.3v2.2h-2.3z" fill="#231f20"/>
<path d="M151.1 237.8h2.3v2.2h-2.3z" fill="none" stroke="#231f20" stroke-width=".16"/>
<path d="M146.5 233.2h2.3v2.2h-2.3z" fill="#231f20"/>
<path d="M146.5 233.2h2.3v2.2h-2.3z" fill="none" stroke="#231f20" stroke-width=".16"/>
<path d="M146.5 237.8h2.3v2.2h-2.3z" fill="#231f20"/>
<path d="M146.5 237.8h2.3v2.2h-2.3z" fill="none" stroke="#231f20" stroke-width=".16"/>
<path d="M155.7 237.8h2.3v2.2h-2.3z" fill="#231f20"/>
<path d="M155.7 237.8h2.3v2.2h-2.3z" fill="none" stroke="#231f20" stroke-width=".16"/>
<path d="M160.3 237.8h2.3v2.2h-2.3z" fill="#231f20"/>
<path d="M160.3 237.8h2.3v2.2h-2.3z" fill="none" stroke="#231f20" stroke-width=".16"/>
<path d="M164.9 237.8h2.2v2.2h-2.2z" fill="#231f20"/>
<path d="M164.9 237.8h2.2v2.2h-2.2z" fill="none" stroke="#231f20" stroke-width=".16"/>
<path d="M169.4 242.4h2.3v2.2h-2.3z" fill="#231f20"/>
<path d="M169.4 242.4h2.3v2.2h-2.3z" fill="none" stroke="#231f20" stroke-width=".16"/>
<path d="M164.8 242.4h2.3v2.2h-2.3z" fill="#231f20"/>
<path d="M164.8 242.4h2.3v2.2h-2.3z" fill="none" stroke="#231f20" stroke-width=".16"/>
<path d="M160.3 242.4h2.2v2.2h-2.2z" fill="#231f20"/>
<path d="M160.3 242.4h2.2v2.2h-2.2z" fill="none" stroke="#231f20" stroke-width=".16"/>
<path d="M155.7 242.4h2.2v2.2h-2.2z" fill="#231f20"/>
<path d="M155.7 242.4h2.2v2.2h-2.2z" fill="none" stroke="#231f20" stroke-width=".16"/>
<path d="M151.1 242.4h2.2v2.2h-2.2z" fill="#231f20"/>
<path d="M151.1 242.4h2.2v2.2h-2.2z" fill="none" stroke="#231f20" stroke-width=".16"/>
<path d="M146.5 242.4h2.2v2.2h-2.2z" fill="#231f20"/>
<path d="M146.5 242.4h2.2v2.2h-2.2z" fill="none" stroke="#231f20" stroke-width=".16"/>
<path d="M141.9 242.4h2.2v2.2h-2.2z" fill="#231f20"/>
<path d="M141.9 242.4h2.2v2.2h-2.2z" fill="none" stroke="#231f20" stroke-width=".16"/>
<path d="M137.3 242.4h2.2v2.2h-2.2z" fill="#231f20"/>
<path d="M137.3 242.4h2.2v2.2h-2.2z" fill="none" stroke="#231f20" stroke-width=".16"/>
<path d="M132.7 242.4h2.2v2.2h-2.2z" fill="#231f20"/>
<path d="M132.7 242.4h2.2v2.2h-2.2z" fill="none" stroke="#231f20" stroke-width=".16"/>
<path d="M128.1 242.4h2.2v2.2h-2.2z" fill="#231f20"/>
<path d="M128.1 242.4h2.2v2.2h-2.2z" fill="none" stroke="#231f20" stroke-width=".16"/>
<path d="M123.5 242.4h2.2v2.2h-1.1l-1.1-1.1z" fill="#231f20"/>
<path d="M123.5 242.4h2.2v2.2h-1.1l-1.1-1.1z" fill="none" stroke="#231f20" stroke-width=".16"/>
<path d="M123.6 192.8l1.2-1.1h1.1v2.2h-2.3z" fill="#231f20"/>
<path d="M123.6 192.8l1.2-1.1h1.1v2.2h-2.3z" fill="none" stroke="#231f20" stroke-width=".16"/>
<path d="M174 191.7h1.2l1.1 1.1v1.2h-2.3z" fill="#231f20"/>
<path d="M174 191.7h1.2l1.1 1.1v1.2h-2.3z" fill="none" stroke="#231f20" stroke-width=".16"/>
<circle cx="175.2" cy="243.5" r="1.13" fill="#231f20"/>
<g fill="none" stroke="#231f20" stroke-width=".16">
<path d="M98.4 51.1l-3.5 3.6"/>
<circle cx="175.2" cy="243.5" r="1.13"/>
</g>
<path d="M94.9 54.1l.1 .5 .4 .1-1.2 .6z" fill="#231f20"/>
<path d="M36.6 102.3l4.6 2.8" fill="none" stroke="#231f20" stroke-width=".16"/>
<g fill="#231f20">
<path d="M41 104.6l.9 1-1.3-.4 .4-.2z"/>
<path d="M87.6 105.6h2.2v2.3h-2.2z"/>
</g>
<path d="M87.6 105.6h2.2v2.3h-2.2z" fill="none" stroke="#231f20" stroke-width=".16"/>
<path d="M46.4 105.7h2.2v2.3h-2.2z" fill="#231f20"/>
<path d="M46.4 105.7h2.2v2.3h-2.2z" fill="none" stroke="#231f20" stroke-width=".16"/>
<path d="M50.9 105.7h2.3v2.3h-2.3z" fill="#231f20"/>
<path d="M50.9 105.7h2.3v2.3h-2.3z" fill="none" stroke="#231f20" stroke-width=".16"/>
<path d="M55.5 105.7h2.3v2.3h-2.3z" fill="#231f20"/>
<path d="M55.5 105.7h2.3v2.3h-2.3z" fill="none" stroke="#231f20" stroke-width=".16"/>
<path d="M60.1 105.7h2.3v2.3h-2.3z" fill="#231f20"/>
<path d="M60.1 105.7h2.3v2.3h-2.3z" fill="none" stroke="#231f20" stroke-width=".16"/>
<path d="M64.7 105.7h2.2v2.3h-2.2z" fill="#231f20"/>
<path d="M64.7 105.7h2.2v2.3h-2.2z" fill="none" stroke="#231f20" stroke-width=".16"/>
<path d="M69.3 105.7h2.2v2.3h-2.2z" fill="#231f20"/>
<path d="M69.3 105.7h2.2v2.3h-2.2z" fill="none" stroke="#231f20" stroke-width=".16"/>
<path d="M73.8 105.7h2.3v2.3h-2.3z" fill="#231f20"/>
<path d="M73.8 105.7h2.3v2.3h-2.3z" fill="none" stroke="#231f20" stroke-width=".16"/>
<path d="M78.4 105.7h2.3v2.3h-2.3z" fill="#231f20"/>
<path d="M78.4 105.7h2.3v2.3h-2.3z" fill="none" stroke="#231f20" stroke-width=".16"/>
<path d="M83 105.7h2.3v2.3h-2.3z" fill="#231f20"/>
<path d="M83 105.7h2.3v2.3h-2.3z" fill="none" stroke="#231f20" stroke-width=".16"/>
<path d="M87.6 101h2.2v2.3h-2.2z" fill="#231f20"/>
<path d="M87.6 101h2.2v2.3h-2.2z" fill="none" stroke="#231f20" stroke-width=".16"/>
<path d="M92.2 101h2.2v2.3h-2.2z" fill="#231f20"/>
<path d="M92.2 101h2.2v2.3h-2.2z" fill="none" stroke="#231f20" stroke-width=".16"/>
<path d="M41.8 101.1h2.2v2.2h-2.2z" fill="#231f20"/>
<path d="M41.8 101.1h2.2v2.3h-2.2z" fill="none" stroke="#231f20" stroke-width=".16"/>
<path d="M46.4 101.1h2.2v2.2h-2.2z" fill="#231f20"/>
<path d="M46.4 101.1h2.2v2.3h-2.2z" fill="none" stroke="#231f20" stroke-width=".16"/>
<path d="M50.9 101.1h2.3v2.2h-2.3z" fill="#231f20"/>
<path d="M50.9 101.1h2.3v2.3h-2.3z" fill="none" stroke="#231f20" stroke-width=".16"/>
<path d="M55.5 101.1h2.3v2.2h-2.3z" fill="#231f20"/>
<path d="M55.5 101.1h2.3v2.3h-2.3z" fill="none" stroke="#231f20" stroke-width=".16"/>
<path d="M60.1 101.1h2.3v2.2h-2.3z" fill="#231f20"/>
<path d="M60.1 101.1h2.3v2.3h-2.3z" fill="none" stroke="#231f20" stroke-width=".16"/>
<path d="M64.7 101.1h2.2v2.2h-2.2z" fill="#231f20"/>
<path d="M64.7 101.1h2.2v2.3h-2.2z" fill="none" stroke="#231f20" stroke-width=".16"/>
<path d="M69.3 101.1h2.2v2.2h-2.2z" fill="#231f20"/>
<path d="M69.3 101.1h2.2v2.3h-2.2z" fill="none" stroke="#231f20" stroke-width=".16"/>
<path d="M73.8 101.1h2.3v2.2h-2.3z" fill="#231f20"/>
<path d="M73.8 101.1h2.3v2.3h-2.3z" fill="none" stroke="#231f20" stroke-width=".16"/>
<path d="M78.4 101.1h2.3v2.2h-2.3z" fill="#231f20"/>
<path d="M78.4 101.1h2.3v2.3h-2.3z" fill="none" stroke="#231f20" stroke-width=".16"/>
<path d="M83 101.1h2.3v2.2h-2.3z" fill="#231f20"/>
<path d="M83 101.1h2.3v2.3h-2.3z" fill="none" stroke="#231f20" stroke-width=".16"/>
<path d="M87.6 96.4h2.2v2.3h-2.2z" fill="#231f20"/>
<path d="M87.6 96.4h2.2v2.3h-2.2z" fill="none" stroke="#231f20" stroke-width=".16"/>
<path d="M92.2 96.4h2.2v2.3h-2.2z" fill="#231f20"/>
<path d="M92.2 96.4h2.2v2.3h-2.2z" fill="none" stroke="#231f20" stroke-width=".16"/>
<path d="M41.8 96.5h2.2v2.2h-2.2z" fill="#231f20"/>
<path d="M41.8 96.5h2.2v2.2h-2.2z" fill="none" stroke="#231f20" stroke-width=".16"/>
<path d="M46.4 96.5h2.2v2.2h-2.2z" fill="#231f20"/>
<path d="M46.4 96.5h2.2v2.2h-2.2z" fill="none" stroke="#231f20" stroke-width=".16"/>
<path d="M50.9 96.5h2.3v2.2h-2.3z" fill="#231f20"/>
<path d="M50.9 96.5h2.3v2.2h-2.3z" fill="none" stroke="#231f20" stroke-width=".16"/>
<path d="M55.5 96.5h2.3v2.2h-2.3z" fill="#231f20"/>
<path d="M55.5 96.5h2.3v2.2h-2.3z" fill="none" stroke="#231f20" stroke-width=".16"/>
<path d="M60.1 96.5h2.3v2.2h-2.3z" fill="#231f20"/>
<path d="M60.1 96.5h2.3v2.2h-2.3z" fill="none" stroke="#231f20" stroke-width=".16"/>
<path d="M64.7 96.5h2.2v2.2h-2.2z" fill="#231f20"/>
<path d="M64.7 96.5h2.2v2.2h-2.2z" fill="none" stroke="#231f20" stroke-width=".16"/>
<path d="M69.3 96.5h2.2v2.2h-2.2z" fill="#231f20"/>
<path d="M69.3 96.5h2.2v2.2h-2.2z" fill="none" stroke="#231f20" stroke-width=".16"/>
<path d="M73.8 96.5h2.3v2.2h-2.3z" fill="#231f20"/>
<path d="M73.8 96.5h2.3v2.2h-2.3z" fill="none" stroke="#231f20" stroke-width=".16"/>
<path d="M78.4 96.5h2.3v2.2h-2.3z" fill="#231f20"/>
<path d="M78.4 96.5h2.3v2.2h-2.3z" fill="none" stroke="#231f20" stroke-width=".16"/>
<path d="M83 96.5h2.3v2.2h-2.3z" fill="#231f20"/>
<path d="M83 96.5h2.3v2.2h-2.3z" fill="none" stroke="#231f20" stroke-width=".16"/>
<path d="M87.6 91.8h2.2v2.3h-2.2z" fill="#231f20"/>
<path d="M87.6 91.8h2.2v2.3h-2.2z" fill="none" stroke="#231f20" stroke-width=".16"/>
<path d="M92.2 91.8h2.2v2.3h-2.2z" fill="#231f20"/>
<path d="M92.2 91.8h2.2v2.3h-2.2z" fill="none" stroke="#231f20" stroke-width=".16"/>
<path d="M41.8 91.9h2.2v2.2h-2.2z" fill="#231f20"/>
<path d="M41.8 91.9h2.2v2.2h-2.2z" fill="none" stroke="#231f20" stroke-width=".16"/>
<path d="M50.9 91.9h2.3v2.2h-2.3z" fill="#231f20"/>
<path d="M50.9 91.9h2.3v2.2h-2.3z" fill="none" stroke="#231f20" stroke-width=".16"/>
<path d="M55.5 91.9h2.3v2.2h-2.3z" fill="#231f20"/>
<path d="M55.5 91.9h2.3v2.2h-2.3z" fill="none" stroke="#231f20" stroke-width=".16"/>
<path d="M60.1 91.9h2.3v2.2h-2.3z" fill="#231f20"/>
<path d="M60.1 91.9h2.3v2.2h-2.3z" fill="none" stroke="#231f20" stroke-width=".16"/>
<path d="M64.7 91.9h2.2v2.2h-2.2z" fill="#231f20"/>
<path d="M64.7 91.9h2.2v2.2h-2.2z" fill="none" stroke="#231f20" stroke-width=".16"/>
<path d="M73.8 91.9h2.3v2.2h-2.3z" fill="#231f20"/>
<path d="M73.8 91.9h2.3v2.2h-2.3z" fill="none" stroke="#231f20" stroke-width=".16"/>
<path d="M78.4 91.9h2.3v2.2h-2.3z" fill="#231f20"/>
<path d="M78.4 91.9h2.3v2.2h-2.3z" fill="none" stroke="#231f20" stroke-width=".16"/>
<path d="M83 91.9h2.3v2.2h-2.3z" fill="#231f20"/>
<path d="M83 91.9h2.3v2.2h-2.3z" fill="none" stroke="#231f20" stroke-width=".16"/>
<path d="M87.6 87.2h2.2v2.3h-2.2z" fill="#231f20"/>
<path d="M87.6 87.2h2.2v2.3h-2.2z" fill="none" stroke="#231f20" stroke-width=".16"/>
<path d="M92.2 87.2h2.2v2.3h-2.2z" fill="#231f20"/>
<path d="M92.2 87.2h2.2v2.3h-2.2z" fill="none" stroke="#231f20" stroke-width=".16"/>
<path d="M41.8 87.3h2.2v2.2h-2.2z" fill="#231f20"/>
<path d="M41.8 87.3h2.2v2.2h-2.2z" fill="none" stroke="#231f20" stroke-width=".16"/>
<path d="M55.5 87.3h2.3v2.2h-2.3z" fill="#231f20"/>
<path d="M55.5 87.3h2.3v2.2h-2.3z" fill="none" stroke="#231f20" stroke-width=".16"/>
<path d="M60.1 87.3h2.3v2.2h-2.3z" fill="#231f20"/>
<path d="M60.1 87.3h2.3v2.2h-2.3z" fill="none" stroke="#231f20" stroke-width=".16"/>
<path d="M64.7 87.3h2.2v2.2h-2.2z" fill="#231f20"/>
<path d="M64.7 87.3h2.2v2.2h-2.2z" fill="none" stroke="#231f20" stroke-width=".16"/>
<path d="M73.8 87.3h2.3v2.2h-2.3z" fill="#231f20"/>
<path d="M73.8 87.3h2.3v2.2h-2.3z" fill="none" stroke="#231f20" stroke-width=".16"/>
<path d="M78.4 87.3h2.3v2.2h-2.3z" fill="#231f20"/>
<path d="M78.4 87.3h2.3v2.2h-2.3z" fill="none" stroke="#231f20" stroke-width=".16"/>
<path d="M83 87.3h2.3v2.2h-2.3z" fill="#231f20"/>
<path d="M83 87.3h2.3v2.2h-2.3z" fill="none" stroke="#231f20" stroke-width=".16"/>
<path d="M87.6 82.6h2.2v2.3h-2.2z" fill="#231f20"/>
<path d="M87.6 82.6h2.2v2.3h-2.2z" fill="none" stroke="#231f20" stroke-width=".16"/>
<path d="M92.2 82.6h2.2v2.3h-2.2z" fill="#231f20"/>
<path d="M92.2 82.6h2.2v2.3h-2.2z" fill="none" stroke="#231f20" stroke-width=".16"/>
<path d="M41.8 82.6h2.2v2.3h-2.2z" fill="#231f20"/>
<path d="M41.8 82.6h2.2v2.3h-2.2z" fill="none" stroke="#231f20" stroke-width=".16"/>
<path d="M55.5 82.6h2.3v2.3h-2.3z" fill="#231f20"/>
<path d="M55.5 82.6h2.3v2.3h-2.3z" fill="none" stroke="#231f20" stroke-width=".16"/>
<path d="M60.1 82.6h2.3v2.3h-2.3z" fill="#231f20"/>
<path d="M60.1 82.6h2.3v2.3h-2.3z" fill="none" stroke="#231f20" stroke-width=".16"/>
<path d="M64.7 82.6h2.2v2.3h-2.2z" fill="#231f20"/>
<path d="M64.7 82.6h2.2v2.3h-2.2z" fill="none" stroke="#231f20" stroke-width=".16"/>
<path d="M73.8 82.6h2.3v2.3h-2.3z" fill="#231f20"/>
<path d="M73.8 82.6h2.3v2.3h-2.3z" fill="none" stroke="#231f20" stroke-width=".16"/>
<path d="M78.4 82.6h2.3v2.3h-2.3z" fill="#231f20"/>
<path d="M78.4 82.6h2.3v2.3h-2.3z" fill="none" stroke="#231f20" stroke-width=".16"/>
<path d="M83 82.6h2.3v2.3h-2.3z" fill="#231f20"/>
<path d="M83 82.6h2.3v2.3h-2.3z" fill="none" stroke="#231f20" stroke-width=".16"/>
<path d="M87.6 78h2.2v2.3h-2.2z" fill="#231f20"/>
<path d="M87.6 78h2.2v2.3h-2.2z" fill="none" stroke="#231f20" stroke-width=".16"/>
<path d="M92.2 78h2.2v2.3h-2.2z" fill="#231f20"/>
<path d="M92.2 78h2.2v2.3h-2.2z" fill="none" stroke="#231f20" stroke-width=".16"/>
<path d="M41.8 78h2.2v2.3h-2.2z" fill="#231f20"/>
<path d="M41.8 78h2.2v2.3h-2.2z" fill="none" stroke="#231f20" stroke-width=".16"/>
<path d="M46.3 87.3h2.2v2.2h-2.2z" fill="#231f20"/>
<path d="M46.3 87.3h2.2v2.2h-2.2z" fill="none" stroke="#231f20" stroke-width=".16"/>
<path d="M46.3 82.6h2.2v2.3h-2.2z" fill="#231f20"/>
<path d="M46.3 82.6h2.2v2.3h-2.2z" fill="none" stroke="#231f20" stroke-width=".16"/>
<path d="M46.3 78h2.2v2.3h-2.2z" fill="#231f20"/>
<path d="M46.3 78h2.2v2.3h-2.2z" fill="none" stroke="#231f20" stroke-width=".16"/>
<path d="M55.5 78h2.3v2.3h-2.3z" fill="#231f20"/>
<path d="M55.5 78h2.3v2.3h-2.3z" fill="none" stroke="#231f20" stroke-width=".16"/>
<path d="M60.1 78h2.3v2.3h-2.3z" fill="#231f20"/>
<path d="M60.1 78h2.3v2.3h-2.3z" fill="none" stroke="#231f20" stroke-width=".16"/>
<path d="M64.7 78h2.2v2.3h-2.2z" fill="#231f20"/>
<path d="M64.7 78h2.2v2.3h-2.2z" fill="none" stroke="#231f20" stroke-width=".16"/>
<path d="M69.3 91.9h2.2v2.2h-2.2z" fill="#231f20"/>
<path d="M69.3 91.9h2.2v2.2h-2.2z" fill="none" stroke="#231f20" stroke-width=".16"/>
<path d="M69.3 87.3h2.2v2.2h-2.2z" fill="#231f20"/>
<path d="M69.3 87.3h2.2v2.2h-2.2z" fill="none" stroke="#231f20" stroke-width=".16"/>
<path d="M69.3 82.6h2.2v2.3h-2.2z" fill="#231f20"/>
<path d="M69.3 82.6h2.2v2.3h-2.2z" fill="none" stroke="#231f20" stroke-width=".16"/>
<path d="M69.3 78h2.2v2.3h-2.2z" fill="#231f20"/>
<path d="M69.3 78h2.2v2.3h-2.2z" fill="none" stroke="#231f20" stroke-width=".16"/>
<path d="M73.8 78h2.3v2.3h-2.3z" fill="#231f20"/>
<path d="M73.8 78h2.3v2.3h-2.3z" fill="none" stroke="#231f20" stroke-width=".16"/>
<path d="M78.4 78h2.3v2.3h-2.3z" fill="#231f20"/>
<path d="M78.4 78h2.3v2.3h-2.3z" fill="none" stroke="#231f20" stroke-width=".16"/>
<path d="M83 78h2.3v2.3h-2.3z" fill="#231f20"/>
<path d="M83 78h2.3v2.3h-2.3z" fill="none" stroke="#231f20" stroke-width=".16"/>
<path d="M87.6 73.4h2.2v2.3h-2.2z" fill="#231f20"/>
<path d="M87.6 73.4h2.2v2.3h-2.2z" fill="none" stroke="#231f20" stroke-width=".16"/>
<path d="M92.2 73.4h2.2v2.3h-2.2z" fill="#231f20"/>
<path d="M92.2 73.4h2.2v2.3h-2.2z" fill="none" stroke="#231f20" stroke-width=".16"/>
<path d="M41.8 73.4h2.2v2.3h-2.2z" fill="#231f20"/>
<path d="M41.8 73.4h2.2v2.3h-2.2z" fill="none" stroke="#231f20" stroke-width=".16"/>
<path d="M46.3 91.9h2.2v2.2h-2.2z" fill="#231f20"/>
<path d="M46.3 91.9h2.2v2.2h-2.2z" fill="none" stroke="#231f20" stroke-width=".16"/>
<path d="M46.3 73.4h2.2v2.3h-2.2z" fill="#231f20"/>
<path d="M46.3 73.4h2.2v2.3h-2.2z" fill="none" stroke="#231f20" stroke-width=".16"/>
<path d="M50.9 87.3h2.3v2.2h-2.3z" fill="#231f20"/>
<path d="M50.9 87.3h2.3v2.2h-2.3z" fill="none" stroke="#231f20" stroke-width=".16"/>
<path d="M50.9 82.6h2.3v2.3h-2.3z" fill="#231f20"/>
<path d="M50.9 82.6h2.3v2.3h-2.3z" fill="none" stroke="#231f20" stroke-width=".16"/>
<path d="M50.9 78h2.3v2.3h-2.3z" fill="#231f20"/>
<path d="M50.9 78h2.3v2.3h-2.3z" fill="none" stroke="#231f20" stroke-width=".16"/>
<path d="M50.9 73.4h2.3v2.3h-2.3z" fill="#231f20"/>
<path d="M50.9 73.4h2.3v2.3h-2.3z" fill="none" stroke="#231f20" stroke-width=".16"/>
<path d="M64.7 73.4h2.2v2.3h-2.2z" fill="#231f20"/>
<path d="M64.7 73.4h2.2v2.3h-2.2z" fill="none" stroke="#231f20" stroke-width=".16"/>
<path d="M69.3 73.4h2.2v2.3h-2.2z" fill="#231f20"/>
<path d="M69.3 73.4h2.2v2.3h-2.2z" fill="none" stroke="#231f20" stroke-width=".16"/>
<path d="M73.8 73.4h2.3v2.3h-2.3z" fill="#231f20"/>
<path d="M73.8 73.4h2.3v2.3h-2.3z" fill="none" stroke="#231f20" stroke-width=".16"/>
<path d="M78.4 73.4h2.3v2.3h-2.3z" fill="#231f20"/>
<path d="M78.4 73.4h2.3v2.3h-2.3z" fill="none" stroke="#231f20" stroke-width=".16"/>
<path d="M83 73.4h2.3v2.3h-2.3z" fill="#231f20"/>
<path d="M83 73.4h2.3v2.3h-2.3z" fill="none" stroke="#231f20" stroke-width=".16"/>
<path d="M87.6 68.8h2.2v2.3h-2.2z" fill="#231f20"/>
<path d="M87.6 68.8h2.2v2.3h-2.2z" fill="none" stroke="#231f20" stroke-width=".16"/>
<path d="M92.2 68.8h2.2v2.3h-2.2z" fill="#231f20"/>
<path d="M92.2 68.8h2.2v2.3h-2.2z" fill="none" stroke="#231f20" stroke-width=".16"/>
<path d="M41.8 68.8h2.2v2.3h-2.2z" fill="#231f20"/>
<path d="M41.8 68.8h2.2v2.3h-2.2z" fill="none" stroke="#231f20" stroke-width=".16"/>
<path d="M69.3 68.8h2.2v2.3h-2.2z" fill="#231f20"/>
<path d="M69.3 68.8h2.2v2.3h-2.2z" fill="none" stroke="#231f20" stroke-width=".16"/>
<path d="M73.8 68.8h2.3v2.3h-2.3z" fill="#231f20"/>
<path d="M73.8 68.8h2.3v2.3h-2.3z" fill="none" stroke="#231f20" stroke-width=".16"/>
<path d="M78.4 68.8h2.3v2.3h-2.3z" fill="#231f20"/>
<path d="M78.4 68.8h2.3v2.3h-2.3z" fill="none" stroke="#231f20" stroke-width=".16"/>
<path d="M83 68.8h2.3v2.3h-2.3z" fill="#231f20"/>
<path d="M83 68.8h2.3v2.3h-2.3z" fill="none" stroke="#231f20" stroke-width=".16"/>
<path d="M87.6 64.2h2.2v2.3h-2.2z" fill="#231f20"/>
<path d="M87.6 64.2h2.2v2.3h-2.2z" fill="none" stroke="#231f20" stroke-width=".16"/>
<path d="M92.2 64.2h2.2v2.3h-2.2z" fill="#231f20"/>
<path d="M92.2 64.2h2.2v2.3h-2.2z" fill="none" stroke="#231f20" stroke-width=".16"/>
<path d="M41.8 64.2h2.2v2.3h-2.2z" fill="#231f20"/>
<path d="M41.8 64.2h2.2v2.3h-2.2z" fill="none" stroke="#231f20" stroke-width=".16"/>
<path d="M69.3 64.2h2.2v2.3h-2.2z" fill="#231f20"/>
<path d="M69.3 64.2h2.2v2.3h-2.2z" fill="none" stroke="#231f20" stroke-width=".16"/>
<path d="M73.8 64.2h2.3v2.3h-2.3z" fill="#231f20"/>
<path d="M73.8 64.2h2.3v2.3h-2.3z" fill="none" stroke="#231f20" stroke-width=".16"/>
<path d="M78.4 64.2h2.3v2.3h-2.3z" fill="#231f20"/>
<path d="M78.4 64.2h2.3v2.3h-2.3z" fill="none" stroke="#231f20" stroke-width=".16"/>
<path d="M83 64.2h2.3v2.3h-2.3z" fill="#231f20"/>
<path d="M83 64.2h2.3v2.3h-2.3z" fill="none" stroke="#231f20" stroke-width=".16"/>
<path d="M87.6 59.6h2.2v2.3h-2.2z" fill="#231f20"/>
<path d="M87.6 59.6h2.2v2.3h-2.2z" fill="none" stroke="#231f20" stroke-width=".16"/>
<path d="M92.2 59.6h2.2v2.3h-2.2z" fill="#231f20"/>
<path d="M92.2 59.6h2.2v2.3h-2.2z" fill="none" stroke="#231f20" stroke-width=".16"/>
<path d="M41.8 59.6h2.2v2.3h-2.2z" fill="#231f20"/>
<path d="M41.8 59.6h2.2v2.3h-2.2z" fill="none" stroke="#231f20" stroke-width=".16"/>
<path d="M55.5 73.4h2.2v2.3h-2.2z" fill="#231f20"/>
<path d="M55.5 73.4h2.2v2.3h-2.2z" fill="none" stroke="#231f20" stroke-width=".16"/>
<path d="M55.5 68.8h2.2v2.3h-2.2z" fill="#231f20"/>
<path d="M55.5 68.8h2.2v2.3h-2.2z" fill="none" stroke="#231f20" stroke-width=".16"/>
<path d="M60.1 68.8h2.2v2.3h-2.2z" fill="#231f20"/>
<path d="M60.1 68.8h2.2v2.3h-2.2z" fill="none" stroke="#231f20" stroke-width=".16"/>
<path d="M55.5 64.2h2.2v2.3h-2.2z" fill="#231f20"/>
<path d="M55.5 64.2h2.2v2.3h-2.2z" fill="none" stroke="#231f20" stroke-width=".16"/>
<path d="M55.5 59.6h2.2v2.3h-2.2z" fill="#231f20"/>
<path d="M55.5 59.6h2.2v2.3h-2.2z" fill="none" stroke="#231f20" stroke-width=".16"/>
<path d="M50.9 59.6h2.3v2.3h-2.3z" fill="#231f20"/>
<path d="M50.9 59.6h2.3v2.3h-2.3z" fill="none" stroke="#231f20" stroke-width=".16"/>
<path d="M60.1 73.4h2.2v2.3h-2.2z" fill="#231f20"/>
<path d="M60.1 73.4h2.2v2.3h-2.2z" fill="none" stroke="#231f20" stroke-width=".16"/>
<path d="M60.1 64.2h2.2v2.3h-2.2z" fill="#231f20"/>
<path d="M60.1 64.2h2.2v2.3h-2.2z" fill="none" stroke="#231f20" stroke-width=".16"/>
<path d="M64.6 68.8h2.3v2.3h-2.3z" fill="#231f20"/>
<path d="M64.6 68.8h2.3v2.3h-2.3z" fill="none" stroke="#231f20" stroke-width=".16"/>
<path d="M60.1 59.6h2.2v2.3h-2.2z" fill="#231f20"/>
<path d="M60.1 59.6h2.2v2.3h-2.2z" fill="none" stroke="#231f20" stroke-width=".16"/>
<path d="M46.3 68.8h2.2v2.3h-2.2z" fill="#231f20"/>
<path d="M46.3 68.8h2.2v2.3h-2.2z" fill="none" stroke="#231f20" stroke-width=".16"/>
<path d="M46.3 64.2h2.2v2.3h-2.2z" fill="#231f20"/>
<path d="M46.3 64.2h2.2v2.3h-2.2z" fill="none" stroke="#231f20" stroke-width=".16"/>
<path d="M50.9 68.8h2.3v2.3h-2.3z" fill="#231f20"/>
<path d="M50.9 68.8h2.3v2.3h-2.3z" fill="none" stroke="#231f20" stroke-width=".16"/>
<path d="M50.9 64.2h2.3v2.3h-2.3z" fill="#231f20"/>
<path d="M50.9 64.2h2.3v2.3h-2.3z" fill="none" stroke="#231f20" stroke-width=".16"/>
<path d="M46.3 59.6h2.2v2.3h-2.2z" fill="#231f20"/>
<path d="M46.3 59.6h2.2v2.3h-2.2z" fill="none" stroke="#231f20" stroke-width=".16"/>
<path d="M69.3 59.6h2.2v2.3h-2.2z" fill="#231f20"/>
<path d="M69.3 59.6h2.2v2.3h-2.2z" fill="none" stroke="#231f20" stroke-width=".16"/>
<path d="M64.6 64.2h2.3v2.3h-2.3z" fill="#231f20"/>
<path d="M64.6 64.2h2.3v2.3h-2.3z" fill="none" stroke="#231f20" stroke-width=".16"/>
<path d="M64.6 59.6h2.3v2.3h-2.3z" fill="#231f20"/>
<path d="M64.6 59.6h2.3v2.3h-2.3z" fill="none" stroke="#231f20" stroke-width=".16"/>
<path d="M73.8 59.6h2.3v2.3h-2.3z" fill="#231f20"/>
<path d="M73.8 59.6h2.3v2.3h-2.3z" fill="none" stroke="#231f20" stroke-width=".16"/>
<path d="M78.4 59.6h2.3v2.3h-2.3z" fill="#231f20"/>
<path d="M78.4 59.6h2.3v2.3h-2.3z" fill="none" stroke="#231f20" stroke-width=".16"/>
<path d="M83 59.6h2.3v2.3h-2.3z" fill="#231f20"/>
<path d="M83 59.6h2.3v2.3h-2.3z" fill="none" stroke="#231f20" stroke-width=".16"/>
<path d="M87.6 55h2.2v2.2h-2.2z" fill="#231f20"/>
<path d="M87.6 55h2.2v2.2h-2.2z" fill="none" stroke="#231f20" stroke-width=".16"/>
<path d="M83 55h2.2v2.2h-2.2z" fill="#231f20"/>
<path d="M83 55h2.2v2.2h-2.2z" fill="none" stroke="#231f20" stroke-width=".16"/>
<path d="M78.4 55h2.2v2.2h-2.2z" fill="#231f20"/>
<path d="M78.4 55h2.2v2.2h-2.2z" fill="none" stroke="#231f20" stroke-width=".16"/>
<path d="M73.8 55h2.2v2.2h-2.2z" fill="#231f20"/>
<path d="M73.8 55h2.2v2.2h-2.2z" fill="none" stroke="#231f20" stroke-width=".16"/>
<path d="M69.2 55h2.3v2.2h-2.3z" fill="#231f20"/>
<path d="M69.2 55h2.3v2.2h-2.3z" fill="none" stroke="#231f20" stroke-width=".16"/>
<path d="M64.6 55h2.3v2.2h-2.3z" fill="#231f20"/>
<path d="M64.6 55h2.3v2.2h-2.3z" fill="none" stroke="#231f20" stroke-width=".16"/>
<path d="M60 55h2.3v2.2h-2.3z" fill="#231f20"/>
<path d="M60 55h2.3v2.2h-2.3z" fill="none" stroke="#231f20" stroke-width=".16"/>
<path d="M55.4 55h2.3v2.2h-2.3z" fill="#231f20"/>
<path d="M55.4 55h2.3v2.2h-2.3z" fill="none" stroke="#231f20" stroke-width=".16"/>
<path d="M50.8 55h2.3v2.2h-2.3z" fill="#231f20"/>
<path d="M50.8 55h2.3v2.2h-2.3z" fill="none" stroke="#231f20" stroke-width=".16"/>
<path d="M46.2 55h2.3v2.2h-2.3z" fill="#231f20"/>
<path d="M46.2 55h2.3v2.2h-2.3z" fill="none" stroke="#231f20" stroke-width=".16"/>
<path d="M41.6 56.1l1.1-1.1h1.2v2.2h-2.3z" fill="#231f20"/>
<path d="M41.6 56.1l1.1-1.1h1.2v2.2h-2.3z" fill="none" stroke="#231f20" stroke-width=".16"/>
<path d="M41.8 105.7h2.2v2.3h-1.1l-1.1-1.1z" fill="#231f20"/>
<path d="M41.8 105.7h2.2v2.3h-1.1l-1.1-1.1z" fill="none" stroke="#231f20" stroke-width=".16"/>
<path d="M92.2 105.6h2.2v1.2l-1.1 1.1h-1.1z" fill="#231f20"/>
<path d="M92.2 105.6h2.2v1.2l-1.1 1.1h-1.1z" fill="none" stroke="#231f20" stroke-width=".16"/>
<circle cx="93.3" cy="56.1" r="1.13" fill="#231f20"/>
<circle cx="93.3" cy="56.1" r="1.13" fill="none" stroke="#231f20" stroke-width=".16"/>
<path d="M93.3 166.1l.4 .2 .3-.2-.3 1.3z" fill="#231f20"/>
<path d="M93.6 170.8v2" fill="none" stroke="#231f20" stroke-width=".16"/>
<g fill="#231f20">
<path d="M93.7 169.9l.3 1.3-.3-.2-.4 .2z"/>
<path d="M99.1 167.5h2.3v2.3h-2.3z"/>
</g>
<path d="M99.1 167.5h2.3v2.3h-2.3z" fill="none" stroke="#231f20" stroke-width=".16"/>
<path d="M99.1 163h2.2v2.2h-2.2z" fill="#231f20"/>
<path d="M99.1 163h2.2v2.2h-2.2z" fill="none" stroke="#231f20" stroke-width=".16"/>
<path d="M103.7 167.5h2.3v2.3h-2.3z" fill="#231f20"/>
<path d="M103.7 167.5h2.3v2.3h-2.3z" fill="none" stroke="#231f20" stroke-width=".16"/>
<path d="M103.7 158.4h2.3v2.2h-2.3z" fill="#231f20"/>
<path d="M103.7 158.4h2.3v2.2h-2.3z" fill="none" stroke="#231f20" stroke-width=".16"/>
<path d="M103.7 163h2.3v2.2h-2.3z" fill="#231f20"/>
<path d="M103.7 163h2.3v2.2h-2.3z" fill="none" stroke="#231f20" stroke-width=".16"/>
<path d="M108.3 158.4h2.3v2.2h-2.3z" fill="#231f20"/>
<path d="M108.3 158.4h2.3v2.2h-2.3z" fill="none" stroke="#231f20" stroke-width=".16"/>
<path d="M108.3 163h2.3v2.2h-2.3z" fill="#231f20"/>
<g fill="none" stroke="#231f20" stroke-width=".16">
<path d="M93.7 154h2.3M93.7 155.8h2.3M93.7 158.3h2.3M93.3 169.8h5.3M93.3 167.5h5.3M93.7 163.3h2.3v-11.1h-2.3v14.2M93.7 161h2.3M93.8 162.1h1.9M94.8 161.2v1.9M108.3 163h2.3v2.2h-2.3z"/>
<circle cx="94.8" cy="157.1" r=".93"/>
<circle cx="94.8" cy="162.2" r=".67"/>
</g>
<path d="M113 157h-15.4v14.5" fill="none" stroke="#231f20" stroke-width=".35"/>
<path d="M99.1 159.5l1.1-1.1h1.1v2.2h-2.2z" fill="#231f20"/>
<g fill="none" stroke="#231f20" stroke-width=".16">
<path d="M33.7 47.6l3.6 3.5M37 40.6v5.2l-2.6-2.6zM99.1 159.5l1.1-1.1h1.1v2.2h-2.2z"/>
<circle cx="44.6" cy="58" r="8.9"/>
</g>
<path d="M40.6 54h55v55.1h-55z" fill="none" stroke="#231f20" stroke-width=".35"/>
<path d="M36.8 51.1l.4-.1 .1-.4 .7 1.2z" fill="#231f20"/>
<path d="M146 107.3v7l-3.4-3.5z" fill="none" stroke="#231f20" stroke-width=".16"/>
<path d="M144.1 104.6l3.9-2.2v4.5z" fill="#fff"/>
<path d="M144.1 104.6l3.9-2.2v4.5z" fill="none" stroke="#231f20" stroke-width=".59"/>
<use href="#words"/>
</svg>
